VERSION 5.8 ;
BUSBITCHARS "[]" ;
DIVIDERCHAR "/" ;
UNITS
    DATABASE MICRONS 1000 ;
END UNITS

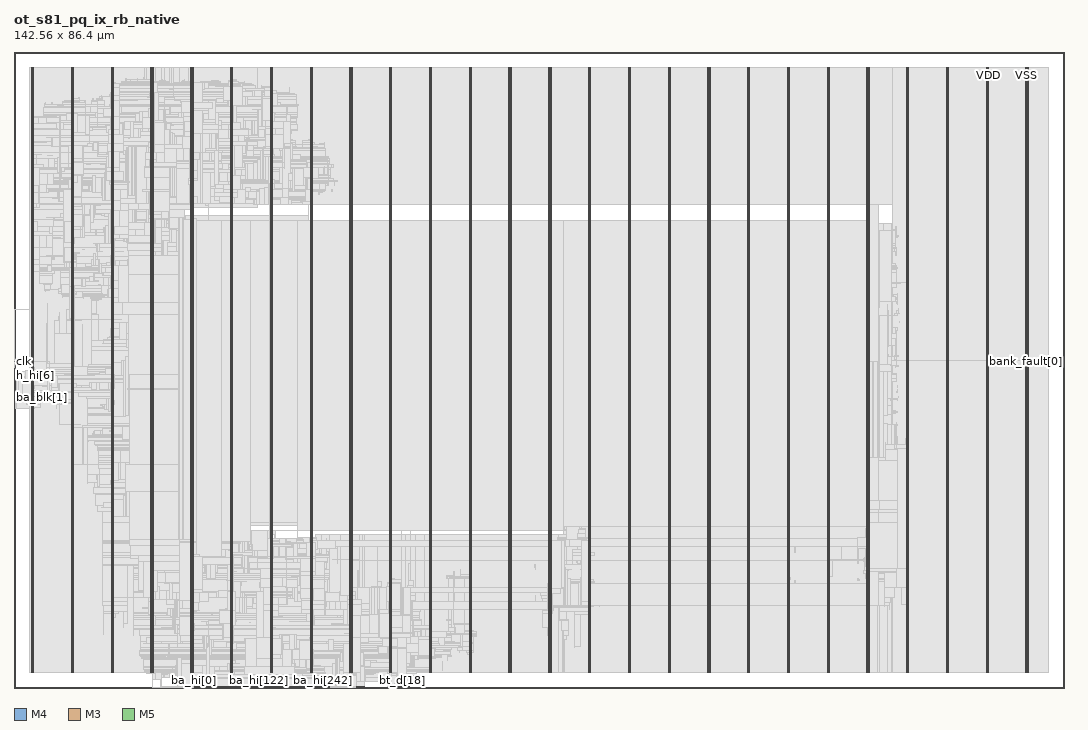
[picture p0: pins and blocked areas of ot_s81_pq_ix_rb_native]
MACRO ot_s81_pq_ix_rb_native
  FOREIGN ot_s81_pq_ix_rb_native 0 0 ;
  CLASS BLOCK ;
  SIZE 142.56 BY 86.4 ;
  PIN ba_blk[0]
    DIRECTION INPUT ;
    USE SIGNAL ;
    PORT
      LAYER M4 ;
        RECT  0 39.312 0.192 39.336 ;
    END
  END ba_blk[0]
  PIN ba_blk[1]
    DIRECTION INPUT ;
    USE SIGNAL ;
    PORT
      LAYER M4 ;
        RECT  0 39.456 0.192 39.48 ;
    END
  END ba_blk[1]
  PIN ba_blk[2]
    DIRECTION INPUT ;
    USE SIGNAL ;
    PORT
      LAYER M4 ;
        RECT  0 39.6 0.192 39.624 ;
    END
  END ba_blk[2]
  PIN ba_blk[3]
    DIRECTION INPUT ;
    USE SIGNAL ;
    PORT
      LAYER M4 ;
        RECT  0 39.744 0.192 39.768 ;
    END
  END ba_blk[3]
  PIN ba_blk[4]
    DIRECTION INPUT ;
    USE SIGNAL ;
    PORT
      LAYER M4 ;
        RECT  0 39.888 0.192 39.912 ;
    END
  END ba_blk[4]
  PIN ba_blk[5]
    DIRECTION INPUT ;
    USE SIGNAL ;
    PORT
      LAYER M4 ;
        RECT  0 40.032 0.192 40.056 ;
    END
  END ba_blk[5]
  PIN ba_blk[6]
    DIRECTION INPUT ;
    USE SIGNAL ;
    PORT
      LAYER M4 ;
        RECT  0 40.176 0.192 40.2 ;
    END
  END ba_blk[6]
  PIN ba_blk[7]
    DIRECTION INPUT ;
    USE SIGNAL ;
    PORT
      LAYER M4 ;
        RECT  0 40.32 0.192 40.344 ;
    END
  END ba_blk[7]
  PIN ba_hi[0]
    DIRECTION INPUT ;
    USE SIGNAL ;
    PORT
      LAYER M3 ;
        RECT  24.48 0 24.498 0.144 ;
    END
  END ba_hi[0]
  PIN ba_hi[100]
    DIRECTION INPUT ;
    USE SIGNAL ;
    PORT
      LAYER M3 ;
        RECT  31.68 0 31.698 0.144 ;
    END
  END ba_hi[100]
  PIN ba_hi[101]
    DIRECTION INPUT ;
    USE SIGNAL ;
    PORT
      LAYER M5 ;
        RECT  31.728 0 31.752 0.192 ;
    END
  END ba_hi[101]
  PIN ba_hi[102]
    DIRECTION INPUT ;
    USE SIGNAL ;
    PORT
      LAYER M3 ;
        RECT  31.824 0 31.842 0.144 ;
    END
  END ba_hi[102]
  PIN ba_hi[103]
    DIRECTION INPUT ;
    USE SIGNAL ;
    PORT
      LAYER M5 ;
        RECT  31.872 0 31.896 0.192 ;
    END
  END ba_hi[103]
  PIN ba_hi[104]
    DIRECTION INPUT ;
    USE SIGNAL ;
    PORT
      LAYER M3 ;
        RECT  31.968 0 31.986 0.144 ;
    END
  END ba_hi[104]
  PIN ba_hi[105]
    DIRECTION INPUT ;
    USE SIGNAL ;
    PORT
      LAYER M5 ;
        RECT  32.016 0 32.04 0.192 ;
    END
  END ba_hi[105]
  PIN ba_hi[106]
    DIRECTION INPUT ;
    USE SIGNAL ;
    PORT
      LAYER M3 ;
        RECT  32.112 0 32.13 0.144 ;
    END
  END ba_hi[106]
  PIN ba_hi[107]
    DIRECTION INPUT ;
    USE SIGNAL ;
    PORT
      LAYER M5 ;
        RECT  32.16 0 32.184 0.192 ;
    END
  END ba_hi[107]
  PIN ba_hi[108]
    DIRECTION INPUT ;
    USE SIGNAL ;
    PORT
      LAYER M3 ;
        RECT  32.256 0 32.274 0.144 ;
    END
  END ba_hi[108]
  PIN ba_hi[109]
    DIRECTION INPUT ;
    USE SIGNAL ;
    PORT
      LAYER M5 ;
        RECT  32.304 0 32.328 0.192 ;
    END
  END ba_hi[109]
  PIN ba_hi[10]
    DIRECTION INPUT ;
    USE SIGNAL ;
    PORT
      LAYER M3 ;
        RECT  25.2 0 25.218 0.144 ;
    END
  END ba_hi[10]
  PIN ba_hi[110]
    DIRECTION INPUT ;
    USE SIGNAL ;
    PORT
      LAYER M3 ;
        RECT  32.4 0 32.418 0.144 ;
    END
  END ba_hi[110]
  PIN ba_hi[111]
    DIRECTION INPUT ;
    USE SIGNAL ;
    PORT
      LAYER M5 ;
        RECT  32.448 0 32.472 0.192 ;
    END
  END ba_hi[111]
  PIN ba_hi[112]
    DIRECTION INPUT ;
    USE SIGNAL ;
    PORT
      LAYER M3 ;
        RECT  32.544 0 32.562 0.144 ;
    END
  END ba_hi[112]
  PIN ba_hi[113]
    DIRECTION INPUT ;
    USE SIGNAL ;
    PORT
      LAYER M5 ;
        RECT  32.592 0 32.616 0.192 ;
    END
  END ba_hi[113]
  PIN ba_hi[114]
    DIRECTION INPUT ;
    USE SIGNAL ;
    PORT
      LAYER M3 ;
        RECT  32.688 0 32.706 0.144 ;
    END
  END ba_hi[114]
  PIN ba_hi[115]
    DIRECTION INPUT ;
    USE SIGNAL ;
    PORT
      LAYER M5 ;
        RECT  32.736 0 32.76 0.192 ;
    END
  END ba_hi[115]
  PIN ba_hi[116]
    DIRECTION INPUT ;
    USE SIGNAL ;
    PORT
      LAYER M3 ;
        RECT  32.832 0 32.85 0.144 ;
    END
  END ba_hi[116]
  PIN ba_hi[117]
    DIRECTION INPUT ;
    USE SIGNAL ;
    PORT
      LAYER M5 ;
        RECT  32.88 0 32.904 0.192 ;
    END
  END ba_hi[117]
  PIN ba_hi[118]
    DIRECTION INPUT ;
    USE SIGNAL ;
    PORT
      LAYER M3 ;
        RECT  32.976 0 32.994 0.144 ;
    END
  END ba_hi[118]
  PIN ba_hi[119]
    DIRECTION INPUT ;
    USE SIGNAL ;
    PORT
      LAYER M5 ;
        RECT  33.024 0 33.048 0.192 ;
    END
  END ba_hi[119]
  PIN ba_hi[11]
    DIRECTION INPUT ;
    USE SIGNAL ;
    PORT
      LAYER M5 ;
        RECT  25.248 0 25.272 0.192 ;
    END
  END ba_hi[11]
  PIN ba_hi[120]
    DIRECTION INPUT ;
    USE SIGNAL ;
    PORT
      LAYER M3 ;
        RECT  33.12 0 33.138 0.144 ;
    END
  END ba_hi[120]
  PIN ba_hi[121]
    DIRECTION INPUT ;
    USE SIGNAL ;
    PORT
      LAYER M5 ;
        RECT  33.168 0 33.192 0.192 ;
    END
  END ba_hi[121]
  PIN ba_hi[122]
    DIRECTION INPUT ;
    USE SIGNAL ;
    PORT
      LAYER M3 ;
        RECT  33.264 0 33.282 0.144 ;
    END
  END ba_hi[122]
  PIN ba_hi[123]
    DIRECTION INPUT ;
    USE SIGNAL ;
    PORT
      LAYER M5 ;
        RECT  33.312 0 33.336 0.192 ;
    END
  END ba_hi[123]
  PIN ba_hi[124]
    DIRECTION INPUT ;
    USE SIGNAL ;
    PORT
      LAYER M3 ;
        RECT  33.408 0 33.426 0.144 ;
    END
  END ba_hi[124]
  PIN ba_hi[125]
    DIRECTION INPUT ;
    USE SIGNAL ;
    PORT
      LAYER M5 ;
        RECT  33.456 0 33.48 0.192 ;
    END
  END ba_hi[125]
  PIN ba_hi[126]
    DIRECTION INPUT ;
    USE SIGNAL ;
    PORT
      LAYER M3 ;
        RECT  33.552 0 33.57 0.144 ;
    END
  END ba_hi[126]
  PIN ba_hi[127]
    DIRECTION INPUT ;
    USE SIGNAL ;
    PORT
      LAYER M5 ;
        RECT  33.6 0 33.624 0.192 ;
    END
  END ba_hi[127]
  PIN ba_hi[128]
    DIRECTION INPUT ;
    USE SIGNAL ;
    PORT
      LAYER M3 ;
        RECT  33.696 0 33.714 0.144 ;
    END
  END ba_hi[128]
  PIN ba_hi[129]
    DIRECTION INPUT ;
    USE SIGNAL ;
    PORT
      LAYER M5 ;
        RECT  33.744 0 33.768 0.192 ;
    END
  END ba_hi[129]
  PIN ba_hi[12]
    DIRECTION INPUT ;
    USE SIGNAL ;
    PORT
      LAYER M3 ;
        RECT  25.344 0 25.362 0.144 ;
    END
  END ba_hi[12]
  PIN ba_hi[130]
    DIRECTION INPUT ;
    USE SIGNAL ;
    PORT
      LAYER M3 ;
        RECT  33.84 0 33.858 0.144 ;
    END
  END ba_hi[130]
  PIN ba_hi[131]
    DIRECTION INPUT ;
    USE SIGNAL ;
    PORT
      LAYER M5 ;
        RECT  33.888 0 33.912 0.192 ;
    END
  END ba_hi[131]
  PIN ba_hi[132]
    DIRECTION INPUT ;
    USE SIGNAL ;
    PORT
      LAYER M3 ;
        RECT  33.984 0 34.002 0.144 ;
    END
  END ba_hi[132]
  PIN ba_hi[133]
    DIRECTION INPUT ;
    USE SIGNAL ;
    PORT
      LAYER M5 ;
        RECT  34.032 0 34.056 0.192 ;
    END
  END ba_hi[133]
  PIN ba_hi[134]
    DIRECTION INPUT ;
    USE SIGNAL ;
    PORT
      LAYER M3 ;
        RECT  34.128 0 34.146 0.144 ;
    END
  END ba_hi[134]
  PIN ba_hi[135]
    DIRECTION INPUT ;
    USE SIGNAL ;
    PORT
      LAYER M5 ;
        RECT  34.176 0 34.2 0.192 ;
    END
  END ba_hi[135]
  PIN ba_hi[136]
    DIRECTION INPUT ;
    USE SIGNAL ;
    PORT
      LAYER M3 ;
        RECT  34.272 0 34.29 0.144 ;
    END
  END ba_hi[136]
  PIN ba_hi[137]
    DIRECTION INPUT ;
    USE SIGNAL ;
    PORT
      LAYER M5 ;
        RECT  34.32 0 34.344 0.192 ;
    END
  END ba_hi[137]
  PIN ba_hi[138]
    DIRECTION INPUT ;
    USE SIGNAL ;
    PORT
      LAYER M3 ;
        RECT  34.416 0 34.434 0.144 ;
    END
  END ba_hi[138]
  PIN ba_hi[139]
    DIRECTION INPUT ;
    USE SIGNAL ;
    PORT
      LAYER M5 ;
        RECT  34.464 0 34.488 0.192 ;
    END
  END ba_hi[139]
  PIN ba_hi[13]
    DIRECTION INPUT ;
    USE SIGNAL ;
    PORT
      LAYER M5 ;
        RECT  25.392 0 25.416 0.192 ;
    END
  END ba_hi[13]
  PIN ba_hi[140]
    DIRECTION INPUT ;
    USE SIGNAL ;
    PORT
      LAYER M3 ;
        RECT  34.56 0 34.578 0.144 ;
    END
  END ba_hi[140]
  PIN ba_hi[141]
    DIRECTION INPUT ;
    USE SIGNAL ;
    PORT
      LAYER M5 ;
        RECT  34.608 0 34.632 0.192 ;
    END
  END ba_hi[141]
  PIN ba_hi[142]
    DIRECTION INPUT ;
    USE SIGNAL ;
    PORT
      LAYER M3 ;
        RECT  34.704 0 34.722 0.144 ;
    END
  END ba_hi[142]
  PIN ba_hi[143]
    DIRECTION INPUT ;
    USE SIGNAL ;
    PORT
      LAYER M5 ;
        RECT  34.752 0 34.776 0.192 ;
    END
  END ba_hi[143]
  PIN ba_hi[144]
    DIRECTION INPUT ;
    USE SIGNAL ;
    PORT
      LAYER M3 ;
        RECT  34.848 0 34.866 0.144 ;
    END
  END ba_hi[144]
  PIN ba_hi[145]
    DIRECTION INPUT ;
    USE SIGNAL ;
    PORT
      LAYER M5 ;
        RECT  34.896 0 34.92 0.192 ;
    END
  END ba_hi[145]
  PIN ba_hi[146]
    DIRECTION INPUT ;
    USE SIGNAL ;
    PORT
      LAYER M3 ;
        RECT  34.992 0 35.01 0.144 ;
    END
  END ba_hi[146]
  PIN ba_hi[147]
    DIRECTION INPUT ;
    USE SIGNAL ;
    PORT
      LAYER M5 ;
        RECT  35.04 0 35.064 0.192 ;
    END
  END ba_hi[147]
  PIN ba_hi[148]
    DIRECTION INPUT ;
    USE SIGNAL ;
    PORT
      LAYER M3 ;
        RECT  35.136 0 35.154 0.144 ;
    END
  END ba_hi[148]
  PIN ba_hi[149]
    DIRECTION INPUT ;
    USE SIGNAL ;
    PORT
      LAYER M5 ;
        RECT  35.184 0 35.208 0.192 ;
    END
  END ba_hi[149]
  PIN ba_hi[14]
    DIRECTION INPUT ;
    USE SIGNAL ;
    PORT
      LAYER M3 ;
        RECT  25.488 0 25.506 0.144 ;
    END
  END ba_hi[14]
  PIN ba_hi[150]
    DIRECTION INPUT ;
    USE SIGNAL ;
    PORT
      LAYER M3 ;
        RECT  35.28 0 35.298 0.144 ;
    END
  END ba_hi[150]
  PIN ba_hi[151]
    DIRECTION INPUT ;
    USE SIGNAL ;
    PORT
      LAYER M5 ;
        RECT  35.328 0 35.352 0.192 ;
    END
  END ba_hi[151]
  PIN ba_hi[152]
    DIRECTION INPUT ;
    USE SIGNAL ;
    PORT
      LAYER M3 ;
        RECT  35.424 0 35.442 0.144 ;
    END
  END ba_hi[152]
  PIN ba_hi[153]
    DIRECTION INPUT ;
    USE SIGNAL ;
    PORT
      LAYER M5 ;
        RECT  35.472 0 35.496 0.192 ;
    END
  END ba_hi[153]
  PIN ba_hi[154]
    DIRECTION INPUT ;
    USE SIGNAL ;
    PORT
      LAYER M3 ;
        RECT  35.568 0 35.586 0.144 ;
    END
  END ba_hi[154]
  PIN ba_hi[155]
    DIRECTION INPUT ;
    USE SIGNAL ;
    PORT
      LAYER M5 ;
        RECT  35.616 0 35.64 0.192 ;
    END
  END ba_hi[155]
  PIN ba_hi[156]
    DIRECTION INPUT ;
    USE SIGNAL ;
    PORT
      LAYER M3 ;
        RECT  35.712 0 35.73 0.144 ;
    END
  END ba_hi[156]
  PIN ba_hi[157]
    DIRECTION INPUT ;
    USE SIGNAL ;
    PORT
      LAYER M5 ;
        RECT  35.76 0 35.784 0.192 ;
    END
  END ba_hi[157]
  PIN ba_hi[158]
    DIRECTION INPUT ;
    USE SIGNAL ;
    PORT
      LAYER M3 ;
        RECT  35.856 0 35.874 0.144 ;
    END
  END ba_hi[158]
  PIN ba_hi[159]
    DIRECTION INPUT ;
    USE SIGNAL ;
    PORT
      LAYER M5 ;
        RECT  35.904 0 35.928 0.192 ;
    END
  END ba_hi[159]
  PIN ba_hi[15]
    DIRECTION INPUT ;
    USE SIGNAL ;
    PORT
      LAYER M5 ;
        RECT  25.536 0 25.56 0.192 ;
    END
  END ba_hi[15]
  PIN ba_hi[160]
    DIRECTION INPUT ;
    USE SIGNAL ;
    PORT
      LAYER M3 ;
        RECT  36 0 36.018 0.144 ;
    END
  END ba_hi[160]
  PIN ba_hi[161]
    DIRECTION INPUT ;
    USE SIGNAL ;
    PORT
      LAYER M5 ;
        RECT  36.048 0 36.072 0.192 ;
    END
  END ba_hi[161]
  PIN ba_hi[162]
    DIRECTION INPUT ;
    USE SIGNAL ;
    PORT
      LAYER M3 ;
        RECT  36.144 0 36.162 0.144 ;
    END
  END ba_hi[162]
  PIN ba_hi[163]
    DIRECTION INPUT ;
    USE SIGNAL ;
    PORT
      LAYER M5 ;
        RECT  36.192 0 36.216 0.192 ;
    END
  END ba_hi[163]
  PIN ba_hi[164]
    DIRECTION INPUT ;
    USE SIGNAL ;
    PORT
      LAYER M3 ;
        RECT  36.288 0 36.306 0.144 ;
    END
  END ba_hi[164]
  PIN ba_hi[165]
    DIRECTION INPUT ;
    USE SIGNAL ;
    PORT
      LAYER M5 ;
        RECT  36.336 0 36.36 0.192 ;
    END
  END ba_hi[165]
  PIN ba_hi[166]
    DIRECTION INPUT ;
    USE SIGNAL ;
    PORT
      LAYER M3 ;
        RECT  36.432 0 36.45 0.144 ;
    END
  END ba_hi[166]
  PIN ba_hi[167]
    DIRECTION INPUT ;
    USE SIGNAL ;
    PORT
      LAYER M5 ;
        RECT  36.48 0 36.504 0.192 ;
    END
  END ba_hi[167]
  PIN ba_hi[168]
    DIRECTION INPUT ;
    USE SIGNAL ;
    PORT
      LAYER M3 ;
        RECT  36.576 0 36.594 0.144 ;
    END
  END ba_hi[168]
  PIN ba_hi[169]
    DIRECTION INPUT ;
    USE SIGNAL ;
    PORT
      LAYER M5 ;
        RECT  36.624 0 36.648 0.192 ;
    END
  END ba_hi[169]
  PIN ba_hi[16]
    DIRECTION INPUT ;
    USE SIGNAL ;
    PORT
      LAYER M3 ;
        RECT  25.632 0 25.65 0.144 ;
    END
  END ba_hi[16]
  PIN ba_hi[170]
    DIRECTION INPUT ;
    USE SIGNAL ;
    PORT
      LAYER M3 ;
        RECT  36.72 0 36.738 0.144 ;
    END
  END ba_hi[170]
  PIN ba_hi[171]
    DIRECTION INPUT ;
    USE SIGNAL ;
    PORT
      LAYER M5 ;
        RECT  36.768 0 36.792 0.192 ;
    END
  END ba_hi[171]
  PIN ba_hi[172]
    DIRECTION INPUT ;
    USE SIGNAL ;
    PORT
      LAYER M3 ;
        RECT  36.864 0 36.882 0.144 ;
    END
  END ba_hi[172]
  PIN ba_hi[173]
    DIRECTION INPUT ;
    USE SIGNAL ;
    PORT
      LAYER M5 ;
        RECT  36.912 0 36.936 0.192 ;
    END
  END ba_hi[173]
  PIN ba_hi[174]
    DIRECTION INPUT ;
    USE SIGNAL ;
    PORT
      LAYER M3 ;
        RECT  37.008 0 37.026 0.144 ;
    END
  END ba_hi[174]
  PIN ba_hi[175]
    DIRECTION INPUT ;
    USE SIGNAL ;
    PORT
      LAYER M5 ;
        RECT  37.056 0 37.08 0.192 ;
    END
  END ba_hi[175]
  PIN ba_hi[176]
    DIRECTION INPUT ;
    USE SIGNAL ;
    PORT
      LAYER M3 ;
        RECT  37.152 0 37.17 0.144 ;
    END
  END ba_hi[176]
  PIN ba_hi[177]
    DIRECTION INPUT ;
    USE SIGNAL ;
    PORT
      LAYER M5 ;
        RECT  37.2 0 37.224 0.192 ;
    END
  END ba_hi[177]
  PIN ba_hi[178]
    DIRECTION INPUT ;
    USE SIGNAL ;
    PORT
      LAYER M3 ;
        RECT  37.296 0 37.314 0.144 ;
    END
  END ba_hi[178]
  PIN ba_hi[179]
    DIRECTION INPUT ;
    USE SIGNAL ;
    PORT
      LAYER M5 ;
        RECT  37.344 0 37.368 0.192 ;
    END
  END ba_hi[179]
  PIN ba_hi[17]
    DIRECTION INPUT ;
    USE SIGNAL ;
    PORT
      LAYER M5 ;
        RECT  25.68 0 25.704 0.192 ;
    END
  END ba_hi[17]
  PIN ba_hi[180]
    DIRECTION INPUT ;
    USE SIGNAL ;
    PORT
      LAYER M3 ;
        RECT  37.44 0 37.458 0.144 ;
    END
  END ba_hi[180]
  PIN ba_hi[181]
    DIRECTION INPUT ;
    USE SIGNAL ;
    PORT
      LAYER M5 ;
        RECT  37.488 0 37.512 0.192 ;
    END
  END ba_hi[181]
  PIN ba_hi[182]
    DIRECTION INPUT ;
    USE SIGNAL ;
    PORT
      LAYER M3 ;
        RECT  37.584 0 37.602 0.144 ;
    END
  END ba_hi[182]
  PIN ba_hi[183]
    DIRECTION INPUT ;
    USE SIGNAL ;
    PORT
      LAYER M5 ;
        RECT  37.632 0 37.656 0.192 ;
    END
  END ba_hi[183]
  PIN ba_hi[184]
    DIRECTION INPUT ;
    USE SIGNAL ;
    PORT
      LAYER M3 ;
        RECT  37.728 0 37.746 0.144 ;
    END
  END ba_hi[184]
  PIN ba_hi[185]
    DIRECTION INPUT ;
    USE SIGNAL ;
    PORT
      LAYER M5 ;
        RECT  37.776 0 37.8 0.192 ;
    END
  END ba_hi[185]
  PIN ba_hi[186]
    DIRECTION INPUT ;
    USE SIGNAL ;
    PORT
      LAYER M3 ;
        RECT  37.872 0 37.89 0.144 ;
    END
  END ba_hi[186]
  PIN ba_hi[187]
    DIRECTION INPUT ;
    USE SIGNAL ;
    PORT
      LAYER M5 ;
        RECT  37.92 0 37.944 0.192 ;
    END
  END ba_hi[187]
  PIN ba_hi[188]
    DIRECTION INPUT ;
    USE SIGNAL ;
    PORT
      LAYER M3 ;
        RECT  38.016 0 38.034 0.144 ;
    END
  END ba_hi[188]
  PIN ba_hi[189]
    DIRECTION INPUT ;
    USE SIGNAL ;
    PORT
      LAYER M5 ;
        RECT  38.064 0 38.088 0.192 ;
    END
  END ba_hi[189]
  PIN ba_hi[18]
    DIRECTION INPUT ;
    USE SIGNAL ;
    PORT
      LAYER M3 ;
        RECT  25.776 0 25.794 0.144 ;
    END
  END ba_hi[18]
  PIN ba_hi[190]
    DIRECTION INPUT ;
    USE SIGNAL ;
    PORT
      LAYER M3 ;
        RECT  38.16 0 38.178 0.144 ;
    END
  END ba_hi[190]
  PIN ba_hi[191]
    DIRECTION INPUT ;
    USE SIGNAL ;
    PORT
      LAYER M5 ;
        RECT  38.208 0 38.232 0.192 ;
    END
  END ba_hi[191]
  PIN ba_hi[192]
    DIRECTION INPUT ;
    USE SIGNAL ;
    PORT
      LAYER M3 ;
        RECT  38.304 0 38.322 0.144 ;
    END
  END ba_hi[192]
  PIN ba_hi[193]
    DIRECTION INPUT ;
    USE SIGNAL ;
    PORT
      LAYER M5 ;
        RECT  38.352 0 38.376 0.192 ;
    END
  END ba_hi[193]
  PIN ba_hi[194]
    DIRECTION INPUT ;
    USE SIGNAL ;
    PORT
      LAYER M3 ;
        RECT  38.448 0 38.466 0.144 ;
    END
  END ba_hi[194]
  PIN ba_hi[195]
    DIRECTION INPUT ;
    USE SIGNAL ;
    PORT
      LAYER M5 ;
        RECT  38.496 0 38.52 0.192 ;
    END
  END ba_hi[195]
  PIN ba_hi[196]
    DIRECTION INPUT ;
    USE SIGNAL ;
    PORT
      LAYER M3 ;
        RECT  38.592 0 38.61 0.144 ;
    END
  END ba_hi[196]
  PIN ba_hi[197]
    DIRECTION INPUT ;
    USE SIGNAL ;
    PORT
      LAYER M5 ;
        RECT  38.64 0 38.664 0.192 ;
    END
  END ba_hi[197]
  PIN ba_hi[198]
    DIRECTION INPUT ;
    USE SIGNAL ;
    PORT
      LAYER M3 ;
        RECT  38.736 0 38.754 0.144 ;
    END
  END ba_hi[198]
  PIN ba_hi[199]
    DIRECTION INPUT ;
    USE SIGNAL ;
    PORT
      LAYER M5 ;
        RECT  38.784 0 38.808 0.192 ;
    END
  END ba_hi[199]
  PIN ba_hi[19]
    DIRECTION INPUT ;
    USE SIGNAL ;
    PORT
      LAYER M5 ;
        RECT  25.824 0 25.848 0.192 ;
    END
  END ba_hi[19]
  PIN ba_hi[1]
    DIRECTION INPUT ;
    USE SIGNAL ;
    PORT
      LAYER M5 ;
        RECT  24.528 0 24.552 0.192 ;
    END
  END ba_hi[1]
  PIN ba_hi[200]
    DIRECTION INPUT ;
    USE SIGNAL ;
    PORT
      LAYER M3 ;
        RECT  38.88 0 38.898 0.144 ;
    END
  END ba_hi[200]
  PIN ba_hi[201]
    DIRECTION INPUT ;
    USE SIGNAL ;
    PORT
      LAYER M5 ;
        RECT  38.928 0 38.952 0.192 ;
    END
  END ba_hi[201]
  PIN ba_hi[202]
    DIRECTION INPUT ;
    USE SIGNAL ;
    PORT
      LAYER M3 ;
        RECT  39.024 0 39.042 0.144 ;
    END
  END ba_hi[202]
  PIN ba_hi[203]
    DIRECTION INPUT ;
    USE SIGNAL ;
    PORT
      LAYER M5 ;
        RECT  39.072 0 39.096 0.192 ;
    END
  END ba_hi[203]
  PIN ba_hi[204]
    DIRECTION INPUT ;
    USE SIGNAL ;
    PORT
      LAYER M3 ;
        RECT  39.168 0 39.186 0.144 ;
    END
  END ba_hi[204]
  PIN ba_hi[205]
    DIRECTION INPUT ;
    USE SIGNAL ;
    PORT
      LAYER M5 ;
        RECT  39.216 0 39.24 0.192 ;
    END
  END ba_hi[205]
  PIN ba_hi[206]
    DIRECTION INPUT ;
    USE SIGNAL ;
    PORT
      LAYER M3 ;
        RECT  39.312 0 39.33 0.144 ;
    END
  END ba_hi[206]
  PIN ba_hi[207]
    DIRECTION INPUT ;
    USE SIGNAL ;
    PORT
      LAYER M5 ;
        RECT  39.36 0 39.384 0.192 ;
    END
  END ba_hi[207]
  PIN ba_hi[208]
    DIRECTION INPUT ;
    USE SIGNAL ;
    PORT
      LAYER M3 ;
        RECT  39.456 0 39.474 0.144 ;
    END
  END ba_hi[208]
  PIN ba_hi[209]
    DIRECTION INPUT ;
    USE SIGNAL ;
    PORT
      LAYER M5 ;
        RECT  39.504 0 39.528 0.192 ;
    END
  END ba_hi[209]
  PIN ba_hi[20]
    DIRECTION INPUT ;
    USE SIGNAL ;
    PORT
      LAYER M3 ;
        RECT  25.92 0 25.938 0.144 ;
    END
  END ba_hi[20]
  PIN ba_hi[210]
    DIRECTION INPUT ;
    USE SIGNAL ;
    PORT
      LAYER M3 ;
        RECT  39.6 0 39.618 0.144 ;
    END
  END ba_hi[210]
  PIN ba_hi[211]
    DIRECTION INPUT ;
    USE SIGNAL ;
    PORT
      LAYER M5 ;
        RECT  39.648 0 39.672 0.192 ;
    END
  END ba_hi[211]
  PIN ba_hi[212]
    DIRECTION INPUT ;
    USE SIGNAL ;
    PORT
      LAYER M3 ;
        RECT  39.744 0 39.762 0.144 ;
    END
  END ba_hi[212]
  PIN ba_hi[213]
    DIRECTION INPUT ;
    USE SIGNAL ;
    PORT
      LAYER M5 ;
        RECT  39.792 0 39.816 0.192 ;
    END
  END ba_hi[213]
  PIN ba_hi[214]
    DIRECTION INPUT ;
    USE SIGNAL ;
    PORT
      LAYER M3 ;
        RECT  39.888 0 39.906 0.144 ;
    END
  END ba_hi[214]
  PIN ba_hi[215]
    DIRECTION INPUT ;
    USE SIGNAL ;
    PORT
      LAYER M5 ;
        RECT  39.936 0 39.96 0.192 ;
    END
  END ba_hi[215]
  PIN ba_hi[216]
    DIRECTION INPUT ;
    USE SIGNAL ;
    PORT
      LAYER M3 ;
        RECT  40.032 0 40.05 0.144 ;
    END
  END ba_hi[216]
  PIN ba_hi[217]
    DIRECTION INPUT ;
    USE SIGNAL ;
    PORT
      LAYER M5 ;
        RECT  40.08 0 40.104 0.192 ;
    END
  END ba_hi[217]
  PIN ba_hi[218]
    DIRECTION INPUT ;
    USE SIGNAL ;
    PORT
      LAYER M3 ;
        RECT  40.176 0 40.194 0.144 ;
    END
  END ba_hi[218]
  PIN ba_hi[219]
    DIRECTION INPUT ;
    USE SIGNAL ;
    PORT
      LAYER M5 ;
        RECT  40.224 0 40.248 0.192 ;
    END
  END ba_hi[219]
  PIN ba_hi[21]
    DIRECTION INPUT ;
    USE SIGNAL ;
    PORT
      LAYER M5 ;
        RECT  25.968 0 25.992 0.192 ;
    END
  END ba_hi[21]
  PIN ba_hi[220]
    DIRECTION INPUT ;
    USE SIGNAL ;
    PORT
      LAYER M3 ;
        RECT  40.32 0 40.338 0.144 ;
    END
  END ba_hi[220]
  PIN ba_hi[221]
    DIRECTION INPUT ;
    USE SIGNAL ;
    PORT
      LAYER M5 ;
        RECT  40.368 0 40.392 0.192 ;
    END
  END ba_hi[221]
  PIN ba_hi[222]
    DIRECTION INPUT ;
    USE SIGNAL ;
    PORT
      LAYER M3 ;
        RECT  40.464 0 40.482 0.144 ;
    END
  END ba_hi[222]
  PIN ba_hi[223]
    DIRECTION INPUT ;
    USE SIGNAL ;
    PORT
      LAYER M5 ;
        RECT  40.512 0 40.536 0.192 ;
    END
  END ba_hi[223]
  PIN ba_hi[224]
    DIRECTION INPUT ;
    USE SIGNAL ;
    PORT
      LAYER M3 ;
        RECT  40.608 0 40.626 0.144 ;
    END
  END ba_hi[224]
  PIN ba_hi[225]
    DIRECTION INPUT ;
    USE SIGNAL ;
    PORT
      LAYER M5 ;
        RECT  40.656 0 40.68 0.192 ;
    END
  END ba_hi[225]
  PIN ba_hi[226]
    DIRECTION INPUT ;
    USE SIGNAL ;
    PORT
      LAYER M3 ;
        RECT  40.752 0 40.77 0.144 ;
    END
  END ba_hi[226]
  PIN ba_hi[227]
    DIRECTION INPUT ;
    USE SIGNAL ;
    PORT
      LAYER M5 ;
        RECT  40.8 0 40.824 0.192 ;
    END
  END ba_hi[227]
  PIN ba_hi[228]
    DIRECTION INPUT ;
    USE SIGNAL ;
    PORT
      LAYER M3 ;
        RECT  40.896 0 40.914 0.144 ;
    END
  END ba_hi[228]
  PIN ba_hi[229]
    DIRECTION INPUT ;
    USE SIGNAL ;
    PORT
      LAYER M5 ;
        RECT  40.944 0 40.968 0.192 ;
    END
  END ba_hi[229]
  PIN ba_hi[22]
    DIRECTION INPUT ;
    USE SIGNAL ;
    PORT
      LAYER M3 ;
        RECT  26.064 0 26.082 0.144 ;
    END
  END ba_hi[22]
  PIN ba_hi[230]
    DIRECTION INPUT ;
    USE SIGNAL ;
    PORT
      LAYER M3 ;
        RECT  41.04 0 41.058 0.144 ;
    END
  END ba_hi[230]
  PIN ba_hi[231]
    DIRECTION INPUT ;
    USE SIGNAL ;
    PORT
      LAYER M5 ;
        RECT  41.088 0 41.112 0.192 ;
    END
  END ba_hi[231]
  PIN ba_hi[232]
    DIRECTION INPUT ;
    USE SIGNAL ;
    PORT
      LAYER M3 ;
        RECT  41.184 0 41.202 0.144 ;
    END
  END ba_hi[232]
  PIN ba_hi[233]
    DIRECTION INPUT ;
    USE SIGNAL ;
    PORT
      LAYER M5 ;
        RECT  41.232 0 41.256 0.192 ;
    END
  END ba_hi[233]
  PIN ba_hi[234]
    DIRECTION INPUT ;
    USE SIGNAL ;
    PORT
      LAYER M3 ;
        RECT  41.328 0 41.346 0.144 ;
    END
  END ba_hi[234]
  PIN ba_hi[235]
    DIRECTION INPUT ;
    USE SIGNAL ;
    PORT
      LAYER M5 ;
        RECT  41.376 0 41.4 0.192 ;
    END
  END ba_hi[235]
  PIN ba_hi[236]
    DIRECTION INPUT ;
    USE SIGNAL ;
    PORT
      LAYER M3 ;
        RECT  41.472 0 41.49 0.144 ;
    END
  END ba_hi[236]
  PIN ba_hi[237]
    DIRECTION INPUT ;
    USE SIGNAL ;
    PORT
      LAYER M5 ;
        RECT  41.52 0 41.544 0.192 ;
    END
  END ba_hi[237]
  PIN ba_hi[238]
    DIRECTION INPUT ;
    USE SIGNAL ;
    PORT
      LAYER M3 ;
        RECT  41.616 0 41.634 0.144 ;
    END
  END ba_hi[238]
  PIN ba_hi[239]
    DIRECTION INPUT ;
    USE SIGNAL ;
    PORT
      LAYER M5 ;
        RECT  41.664 0 41.688 0.192 ;
    END
  END ba_hi[239]
  PIN ba_hi[23]
    DIRECTION INPUT ;
    USE SIGNAL ;
    PORT
      LAYER M5 ;
        RECT  26.112 0 26.136 0.192 ;
    END
  END ba_hi[23]
  PIN ba_hi[240]
    DIRECTION INPUT ;
    USE SIGNAL ;
    PORT
      LAYER M3 ;
        RECT  41.76 0 41.778 0.144 ;
    END
  END ba_hi[240]
  PIN ba_hi[241]
    DIRECTION INPUT ;
    USE SIGNAL ;
    PORT
      LAYER M5 ;
        RECT  41.808 0 41.832 0.192 ;
    END
  END ba_hi[241]
  PIN ba_hi[242]
    DIRECTION INPUT ;
    USE SIGNAL ;
    PORT
      LAYER M3 ;
        RECT  41.904 0 41.922 0.144 ;
    END
  END ba_hi[242]
  PIN ba_hi[243]
    DIRECTION INPUT ;
    USE SIGNAL ;
    PORT
      LAYER M5 ;
        RECT  41.952 0 41.976 0.192 ;
    END
  END ba_hi[243]
  PIN ba_hi[244]
    DIRECTION INPUT ;
    USE SIGNAL ;
    PORT
      LAYER M3 ;
        RECT  42.048 0 42.066 0.144 ;
    END
  END ba_hi[244]
  PIN ba_hi[245]
    DIRECTION INPUT ;
    USE SIGNAL ;
    PORT
      LAYER M5 ;
        RECT  42.096 0 42.12 0.192 ;
    END
  END ba_hi[245]
  PIN ba_hi[246]
    DIRECTION INPUT ;
    USE SIGNAL ;
    PORT
      LAYER M3 ;
        RECT  42.192 0 42.21 0.144 ;
    END
  END ba_hi[246]
  PIN ba_hi[247]
    DIRECTION INPUT ;
    USE SIGNAL ;
    PORT
      LAYER M5 ;
        RECT  42.24 0 42.264 0.192 ;
    END
  END ba_hi[247]
  PIN ba_hi[248]
    DIRECTION INPUT ;
    USE SIGNAL ;
    PORT
      LAYER M3 ;
        RECT  42.336 0 42.354 0.144 ;
    END
  END ba_hi[248]
  PIN ba_hi[249]
    DIRECTION INPUT ;
    USE SIGNAL ;
    PORT
      LAYER M5 ;
        RECT  42.384 0 42.408 0.192 ;
    END
  END ba_hi[249]
  PIN ba_hi[24]
    DIRECTION INPUT ;
    USE SIGNAL ;
    PORT
      LAYER M3 ;
        RECT  26.208 0 26.226 0.144 ;
    END
  END ba_hi[24]
  PIN ba_hi[250]
    DIRECTION INPUT ;
    USE SIGNAL ;
    PORT
      LAYER M3 ;
        RECT  42.48 0 42.498 0.144 ;
    END
  END ba_hi[250]
  PIN ba_hi[251]
    DIRECTION INPUT ;
    USE SIGNAL ;
    PORT
      LAYER M5 ;
        RECT  42.528 0 42.552 0.192 ;
    END
  END ba_hi[251]
  PIN ba_hi[252]
    DIRECTION INPUT ;
    USE SIGNAL ;
    PORT
      LAYER M3 ;
        RECT  42.624 0 42.642 0.144 ;
    END
  END ba_hi[252]
  PIN ba_hi[253]
    DIRECTION INPUT ;
    USE SIGNAL ;
    PORT
      LAYER M5 ;
        RECT  42.672 0 42.696 0.192 ;
    END
  END ba_hi[253]
  PIN ba_hi[254]
    DIRECTION INPUT ;
    USE SIGNAL ;
    PORT
      LAYER M3 ;
        RECT  42.768 0 42.786 0.144 ;
    END
  END ba_hi[254]
  PIN ba_hi[255]
    DIRECTION INPUT ;
    USE SIGNAL ;
    PORT
      LAYER M5 ;
        RECT  42.816 0 42.84 0.192 ;
    END
  END ba_hi[255]
  PIN ba_hi[25]
    DIRECTION INPUT ;
    USE SIGNAL ;
    PORT
      LAYER M5 ;
        RECT  26.256 0 26.28 0.192 ;
    END
  END ba_hi[25]
  PIN ba_hi[26]
    DIRECTION INPUT ;
    USE SIGNAL ;
    PORT
      LAYER M3 ;
        RECT  26.352 0 26.37 0.144 ;
    END
  END ba_hi[26]
  PIN ba_hi[27]
    DIRECTION INPUT ;
    USE SIGNAL ;
    PORT
      LAYER M5 ;
        RECT  26.4 0 26.424 0.192 ;
    END
  END ba_hi[27]
  PIN ba_hi[28]
    DIRECTION INPUT ;
    USE SIGNAL ;
    PORT
      LAYER M3 ;
        RECT  26.496 0 26.514 0.144 ;
    END
  END ba_hi[28]
  PIN ba_hi[29]
    DIRECTION INPUT ;
    USE SIGNAL ;
    PORT
      LAYER M5 ;
        RECT  26.544 0 26.568 0.192 ;
    END
  END ba_hi[29]
  PIN ba_hi[2]
    DIRECTION INPUT ;
    USE SIGNAL ;
    PORT
      LAYER M3 ;
        RECT  24.624 0 24.642 0.144 ;
    END
  END ba_hi[2]
  PIN ba_hi[30]
    DIRECTION INPUT ;
    USE SIGNAL ;
    PORT
      LAYER M3 ;
        RECT  26.64 0 26.658 0.144 ;
    END
  END ba_hi[30]
  PIN ba_hi[31]
    DIRECTION INPUT ;
    USE SIGNAL ;
    PORT
      LAYER M5 ;
        RECT  26.688 0 26.712 0.192 ;
    END
  END ba_hi[31]
  PIN ba_hi[32]
    DIRECTION INPUT ;
    USE SIGNAL ;
    PORT
      LAYER M3 ;
        RECT  26.784 0 26.802 0.144 ;
    END
  END ba_hi[32]
  PIN ba_hi[33]
    DIRECTION INPUT ;
    USE SIGNAL ;
    PORT
      LAYER M5 ;
        RECT  26.832 0 26.856 0.192 ;
    END
  END ba_hi[33]
  PIN ba_hi[34]
    DIRECTION INPUT ;
    USE SIGNAL ;
    PORT
      LAYER M3 ;
        RECT  26.928 0 26.946 0.144 ;
    END
  END ba_hi[34]
  PIN ba_hi[35]
    DIRECTION INPUT ;
    USE SIGNAL ;
    PORT
      LAYER M5 ;
        RECT  26.976 0 27 0.192 ;
    END
  END ba_hi[35]
  PIN ba_hi[36]
    DIRECTION INPUT ;
    USE SIGNAL ;
    PORT
      LAYER M3 ;
        RECT  27.072 0 27.09 0.144 ;
    END
  END ba_hi[36]
  PIN ba_hi[37]
    DIRECTION INPUT ;
    USE SIGNAL ;
    PORT
      LAYER M5 ;
        RECT  27.12 0 27.144 0.192 ;
    END
  END ba_hi[37]
  PIN ba_hi[38]
    DIRECTION INPUT ;
    USE SIGNAL ;
    PORT
      LAYER M3 ;
        RECT  27.216 0 27.234 0.144 ;
    END
  END ba_hi[38]
  PIN ba_hi[39]
    DIRECTION INPUT ;
    USE SIGNAL ;
    PORT
      LAYER M5 ;
        RECT  27.264 0 27.288 0.192 ;
    END
  END ba_hi[39]
  PIN ba_hi[3]
    DIRECTION INPUT ;
    USE SIGNAL ;
    PORT
      LAYER M5 ;
        RECT  24.672 0 24.696 0.192 ;
    END
  END ba_hi[3]
  PIN ba_hi[40]
    DIRECTION INPUT ;
    USE SIGNAL ;
    PORT
      LAYER M3 ;
        RECT  27.36 0 27.378 0.144 ;
    END
  END ba_hi[40]
  PIN ba_hi[41]
    DIRECTION INPUT ;
    USE SIGNAL ;
    PORT
      LAYER M5 ;
        RECT  27.408 0 27.432 0.192 ;
    END
  END ba_hi[41]
  PIN ba_hi[42]
    DIRECTION INPUT ;
    USE SIGNAL ;
    PORT
      LAYER M3 ;
        RECT  27.504 0 27.522 0.144 ;
    END
  END ba_hi[42]
  PIN ba_hi[43]
    DIRECTION INPUT ;
    USE SIGNAL ;
    PORT
      LAYER M5 ;
        RECT  27.552 0 27.576 0.192 ;
    END
  END ba_hi[43]
  PIN ba_hi[44]
    DIRECTION INPUT ;
    USE SIGNAL ;
    PORT
      LAYER M3 ;
        RECT  27.648 0 27.666 0.144 ;
    END
  END ba_hi[44]
  PIN ba_hi[45]
    DIRECTION INPUT ;
    USE SIGNAL ;
    PORT
      LAYER M5 ;
        RECT  27.696 0 27.72 0.192 ;
    END
  END ba_hi[45]
  PIN ba_hi[46]
    DIRECTION INPUT ;
    USE SIGNAL ;
    PORT
      LAYER M3 ;
        RECT  27.792 0 27.81 0.144 ;
    END
  END ba_hi[46]
  PIN ba_hi[47]
    DIRECTION INPUT ;
    USE SIGNAL ;
    PORT
      LAYER M5 ;
        RECT  27.84 0 27.864 0.192 ;
    END
  END ba_hi[47]
  PIN ba_hi[48]
    DIRECTION INPUT ;
    USE SIGNAL ;
    PORT
      LAYER M3 ;
        RECT  27.936 0 27.954 0.144 ;
    END
  END ba_hi[48]
  PIN ba_hi[49]
    DIRECTION INPUT ;
    USE SIGNAL ;
    PORT
      LAYER M5 ;
        RECT  27.984 0 28.008 0.192 ;
    END
  END ba_hi[49]
  PIN ba_hi[4]
    DIRECTION INPUT ;
    USE SIGNAL ;
    PORT
      LAYER M3 ;
        RECT  24.768 0 24.786 0.144 ;
    END
  END ba_hi[4]
  PIN ba_hi[50]
    DIRECTION INPUT ;
    USE SIGNAL ;
    PORT
      LAYER M3 ;
        RECT  28.08 0 28.098 0.144 ;
    END
  END ba_hi[50]
  PIN ba_hi[51]
    DIRECTION INPUT ;
    USE SIGNAL ;
    PORT
      LAYER M5 ;
        RECT  28.128 0 28.152 0.192 ;
    END
  END ba_hi[51]
  PIN ba_hi[52]
    DIRECTION INPUT ;
    USE SIGNAL ;
    PORT
      LAYER M3 ;
        RECT  28.224 0 28.242 0.144 ;
    END
  END ba_hi[52]
  PIN ba_hi[53]
    DIRECTION INPUT ;
    USE SIGNAL ;
    PORT
      LAYER M5 ;
        RECT  28.272 0 28.296 0.192 ;
    END
  END ba_hi[53]
  PIN ba_hi[54]
    DIRECTION INPUT ;
    USE SIGNAL ;
    PORT
      LAYER M3 ;
        RECT  28.368 0 28.386 0.144 ;
    END
  END ba_hi[54]
  PIN ba_hi[55]
    DIRECTION INPUT ;
    USE SIGNAL ;
    PORT
      LAYER M5 ;
        RECT  28.416 0 28.44 0.192 ;
    END
  END ba_hi[55]
  PIN ba_hi[56]
    DIRECTION INPUT ;
    USE SIGNAL ;
    PORT
      LAYER M3 ;
        RECT  28.512 0 28.53 0.144 ;
    END
  END ba_hi[56]
  PIN ba_hi[57]
    DIRECTION INPUT ;
    USE SIGNAL ;
    PORT
      LAYER M5 ;
        RECT  28.56 0 28.584 0.192 ;
    END
  END ba_hi[57]
  PIN ba_hi[58]
    DIRECTION INPUT ;
    USE SIGNAL ;
    PORT
      LAYER M3 ;
        RECT  28.656 0 28.674 0.144 ;
    END
  END ba_hi[58]
  PIN ba_hi[59]
    DIRECTION INPUT ;
    USE SIGNAL ;
    PORT
      LAYER M5 ;
        RECT  28.704 0 28.728 0.192 ;
    END
  END ba_hi[59]
  PIN ba_hi[5]
    DIRECTION INPUT ;
    USE SIGNAL ;
    PORT
      LAYER M5 ;
        RECT  24.816 0 24.84 0.192 ;
    END
  END ba_hi[5]
  PIN ba_hi[60]
    DIRECTION INPUT ;
    USE SIGNAL ;
    PORT
      LAYER M3 ;
        RECT  28.8 0 28.818 0.144 ;
    END
  END ba_hi[60]
  PIN ba_hi[61]
    DIRECTION INPUT ;
    USE SIGNAL ;
    PORT
      LAYER M5 ;
        RECT  28.848 0 28.872 0.192 ;
    END
  END ba_hi[61]
  PIN ba_hi[62]
    DIRECTION INPUT ;
    USE SIGNAL ;
    PORT
      LAYER M3 ;
        RECT  28.944 0 28.962 0.144 ;
    END
  END ba_hi[62]
  PIN ba_hi[63]
    DIRECTION INPUT ;
    USE SIGNAL ;
    PORT
      LAYER M5 ;
        RECT  28.992 0 29.016 0.192 ;
    END
  END ba_hi[63]
  PIN ba_hi[64]
    DIRECTION INPUT ;
    USE SIGNAL ;
    PORT
      LAYER M3 ;
        RECT  29.088 0 29.106 0.144 ;
    END
  END ba_hi[64]
  PIN ba_hi[65]
    DIRECTION INPUT ;
    USE SIGNAL ;
    PORT
      LAYER M5 ;
        RECT  29.136 0 29.16 0.192 ;
    END
  END ba_hi[65]
  PIN ba_hi[66]
    DIRECTION INPUT ;
    USE SIGNAL ;
    PORT
      LAYER M3 ;
        RECT  29.232 0 29.25 0.144 ;
    END
  END ba_hi[66]
  PIN ba_hi[67]
    DIRECTION INPUT ;
    USE SIGNAL ;
    PORT
      LAYER M5 ;
        RECT  29.28 0 29.304 0.192 ;
    END
  END ba_hi[67]
  PIN ba_hi[68]
    DIRECTION INPUT ;
    USE SIGNAL ;
    PORT
      LAYER M3 ;
        RECT  29.376 0 29.394 0.144 ;
    END
  END ba_hi[68]
  PIN ba_hi[69]
    DIRECTION INPUT ;
    USE SIGNAL ;
    PORT
      LAYER M5 ;
        RECT  29.424 0 29.448 0.192 ;
    END
  END ba_hi[69]
  PIN ba_hi[6]
    DIRECTION INPUT ;
    USE SIGNAL ;
    PORT
      LAYER M3 ;
        RECT  24.912 0 24.93 0.144 ;
    END
  END ba_hi[6]
  PIN ba_hi[70]
    DIRECTION INPUT ;
    USE SIGNAL ;
    PORT
      LAYER M3 ;
        RECT  29.52 0 29.538 0.144 ;
    END
  END ba_hi[70]
  PIN ba_hi[71]
    DIRECTION INPUT ;
    USE SIGNAL ;
    PORT
      LAYER M5 ;
        RECT  29.568 0 29.592 0.192 ;
    END
  END ba_hi[71]
  PIN ba_hi[72]
    DIRECTION INPUT ;
    USE SIGNAL ;
    PORT
      LAYER M3 ;
        RECT  29.664 0 29.682 0.144 ;
    END
  END ba_hi[72]
  PIN ba_hi[73]
    DIRECTION INPUT ;
    USE SIGNAL ;
    PORT
      LAYER M5 ;
        RECT  29.712 0 29.736 0.192 ;
    END
  END ba_hi[73]
  PIN ba_hi[74]
    DIRECTION INPUT ;
    USE SIGNAL ;
    PORT
      LAYER M3 ;
        RECT  29.808 0 29.826 0.144 ;
    END
  END ba_hi[74]
  PIN ba_hi[75]
    DIRECTION INPUT ;
    USE SIGNAL ;
    PORT
      LAYER M5 ;
        RECT  29.856 0 29.88 0.192 ;
    END
  END ba_hi[75]
  PIN ba_hi[76]
    DIRECTION INPUT ;
    USE SIGNAL ;
    PORT
      LAYER M3 ;
        RECT  29.952 0 29.97 0.144 ;
    END
  END ba_hi[76]
  PIN ba_hi[77]
    DIRECTION INPUT ;
    USE SIGNAL ;
    PORT
      LAYER M5 ;
        RECT  30 0 30.024 0.192 ;
    END
  END ba_hi[77]
  PIN ba_hi[78]
    DIRECTION INPUT ;
    USE SIGNAL ;
    PORT
      LAYER M3 ;
        RECT  30.096 0 30.114 0.144 ;
    END
  END ba_hi[78]
  PIN ba_hi[79]
    DIRECTION INPUT ;
    USE SIGNAL ;
    PORT
      LAYER M5 ;
        RECT  30.144 0 30.168 0.192 ;
    END
  END ba_hi[79]
  PIN ba_hi[7]
    DIRECTION INPUT ;
    USE SIGNAL ;
    PORT
      LAYER M5 ;
        RECT  24.96 0 24.984 0.192 ;
    END
  END ba_hi[7]
  PIN ba_hi[80]
    DIRECTION INPUT ;
    USE SIGNAL ;
    PORT
      LAYER M3 ;
        RECT  30.24 0 30.258 0.144 ;
    END
  END ba_hi[80]
  PIN ba_hi[81]
    DIRECTION INPUT ;
    USE SIGNAL ;
    PORT
      LAYER M5 ;
        RECT  30.288 0 30.312 0.192 ;
    END
  END ba_hi[81]
  PIN ba_hi[82]
    DIRECTION INPUT ;
    USE SIGNAL ;
    PORT
      LAYER M3 ;
        RECT  30.384 0 30.402 0.144 ;
    END
  END ba_hi[82]
  PIN ba_hi[83]
    DIRECTION INPUT ;
    USE SIGNAL ;
    PORT
      LAYER M5 ;
        RECT  30.432 0 30.456 0.192 ;
    END
  END ba_hi[83]
  PIN ba_hi[84]
    DIRECTION INPUT ;
    USE SIGNAL ;
    PORT
      LAYER M3 ;
        RECT  30.528 0 30.546 0.144 ;
    END
  END ba_hi[84]
  PIN ba_hi[85]
    DIRECTION INPUT ;
    USE SIGNAL ;
    PORT
      LAYER M5 ;
        RECT  30.576 0 30.6 0.192 ;
    END
  END ba_hi[85]
  PIN ba_hi[86]
    DIRECTION INPUT ;
    USE SIGNAL ;
    PORT
      LAYER M3 ;
        RECT  30.672 0 30.69 0.144 ;
    END
  END ba_hi[86]
  PIN ba_hi[87]
    DIRECTION INPUT ;
    USE SIGNAL ;
    PORT
      LAYER M5 ;
        RECT  30.72 0 30.744 0.192 ;
    END
  END ba_hi[87]
  PIN ba_hi[88]
    DIRECTION INPUT ;
    USE SIGNAL ;
    PORT
      LAYER M3 ;
        RECT  30.816 0 30.834 0.144 ;
    END
  END ba_hi[88]
  PIN ba_hi[89]
    DIRECTION INPUT ;
    USE SIGNAL ;
    PORT
      LAYER M5 ;
        RECT  30.864 0 30.888 0.192 ;
    END
  END ba_hi[89]
  PIN ba_hi[8]
    DIRECTION INPUT ;
    USE SIGNAL ;
    PORT
      LAYER M3 ;
        RECT  25.056 0 25.074 0.144 ;
    END
  END ba_hi[8]
  PIN ba_hi[90]
    DIRECTION INPUT ;
    USE SIGNAL ;
    PORT
      LAYER M3 ;
        RECT  30.96 0 30.978 0.144 ;
    END
  END ba_hi[90]
  PIN ba_hi[91]
    DIRECTION INPUT ;
    USE SIGNAL ;
    PORT
      LAYER M5 ;
        RECT  31.008 0 31.032 0.192 ;
    END
  END ba_hi[91]
  PIN ba_hi[92]
    DIRECTION INPUT ;
    USE SIGNAL ;
    PORT
      LAYER M3 ;
        RECT  31.104 0 31.122 0.144 ;
    END
  END ba_hi[92]
  PIN ba_hi[93]
    DIRECTION INPUT ;
    USE SIGNAL ;
    PORT
      LAYER M5 ;
        RECT  31.152 0 31.176 0.192 ;
    END
  END ba_hi[93]
  PIN ba_hi[94]
    DIRECTION INPUT ;
    USE SIGNAL ;
    PORT
      LAYER M3 ;
        RECT  31.248 0 31.266 0.144 ;
    END
  END ba_hi[94]
  PIN ba_hi[95]
    DIRECTION INPUT ;
    USE SIGNAL ;
    PORT
      LAYER M5 ;
        RECT  31.296 0 31.32 0.192 ;
    END
  END ba_hi[95]
  PIN ba_hi[96]
    DIRECTION INPUT ;
    USE SIGNAL ;
    PORT
      LAYER M3 ;
        RECT  31.392 0 31.41 0.144 ;
    END
  END ba_hi[96]
  PIN ba_hi[97]
    DIRECTION INPUT ;
    USE SIGNAL ;
    PORT
      LAYER M5 ;
        RECT  31.44 0 31.464 0.192 ;
    END
  END ba_hi[97]
  PIN ba_hi[98]
    DIRECTION INPUT ;
    USE SIGNAL ;
    PORT
      LAYER M3 ;
        RECT  31.536 0 31.554 0.144 ;
    END
  END ba_hi[98]
  PIN ba_hi[99]
    DIRECTION INPUT ;
    USE SIGNAL ;
    PORT
      LAYER M5 ;
        RECT  31.584 0 31.608 0.192 ;
    END
  END ba_hi[99]
  PIN ba_hi[9]
    DIRECTION INPUT ;
    USE SIGNAL ;
    PORT
      LAYER M5 ;
        RECT  25.104 0 25.128 0.192 ;
    END
  END ba_hi[9]
  PIN ba_inc[0]
    DIRECTION INPUT ;
    USE SIGNAL ;
    PORT
      LAYER M3 ;
        RECT  46.512 0 46.53 0.144 ;
    END
  END ba_inc[0]
  PIN ba_inc[10]
    DIRECTION INPUT ;
    USE SIGNAL ;
    PORT
      LAYER M3 ;
        RECT  47.232 0 47.25 0.144 ;
    END
  END ba_inc[10]
  PIN ba_inc[11]
    DIRECTION INPUT ;
    USE SIGNAL ;
    PORT
      LAYER M5 ;
        RECT  47.28 0 47.304 0.192 ;
    END
  END ba_inc[11]
  PIN ba_inc[12]
    DIRECTION INPUT ;
    USE SIGNAL ;
    PORT
      LAYER M3 ;
        RECT  47.376 0 47.394 0.144 ;
    END
  END ba_inc[12]
  PIN ba_inc[13]
    DIRECTION INPUT ;
    USE SIGNAL ;
    PORT
      LAYER M5 ;
        RECT  47.424 0 47.448 0.192 ;
    END
  END ba_inc[13]
  PIN ba_inc[14]
    DIRECTION INPUT ;
    USE SIGNAL ;
    PORT
      LAYER M3 ;
        RECT  47.52 0 47.538 0.144 ;
    END
  END ba_inc[14]
  PIN ba_inc[15]
    DIRECTION INPUT ;
    USE SIGNAL ;
    PORT
      LAYER M5 ;
        RECT  47.568 0 47.592 0.192 ;
    END
  END ba_inc[15]
  PIN ba_inc[1]
    DIRECTION INPUT ;
    USE SIGNAL ;
    PORT
      LAYER M5 ;
        RECT  46.56 0 46.584 0.192 ;
    END
  END ba_inc[1]
  PIN ba_inc[2]
    DIRECTION INPUT ;
    USE SIGNAL ;
    PORT
      LAYER M3 ;
        RECT  46.656 0 46.674 0.144 ;
    END
  END ba_inc[2]
  PIN ba_inc[3]
    DIRECTION INPUT ;
    USE SIGNAL ;
    PORT
      LAYER M5 ;
        RECT  46.704 0 46.728 0.192 ;
    END
  END ba_inc[3]
  PIN ba_inc[4]
    DIRECTION INPUT ;
    USE SIGNAL ;
    PORT
      LAYER M3 ;
        RECT  46.8 0 46.818 0.144 ;
    END
  END ba_inc[4]
  PIN ba_inc[5]
    DIRECTION INPUT ;
    USE SIGNAL ;
    PORT
      LAYER M5 ;
        RECT  46.848 0 46.872 0.192 ;
    END
  END ba_inc[5]
  PIN ba_inc[6]
    DIRECTION INPUT ;
    USE SIGNAL ;
    PORT
      LAYER M3 ;
        RECT  46.944 0 46.962 0.144 ;
    END
  END ba_inc[6]
  PIN ba_inc[7]
    DIRECTION INPUT ;
    USE SIGNAL ;
    PORT
      LAYER M5 ;
        RECT  46.992 0 47.016 0.192 ;
    END
  END ba_inc[7]
  PIN ba_inc[8]
    DIRECTION INPUT ;
    USE SIGNAL ;
    PORT
      LAYER M3 ;
        RECT  47.088 0 47.106 0.144 ;
    END
  END ba_inc[8]
  PIN ba_inc[9]
    DIRECTION INPUT ;
    USE SIGNAL ;
    PORT
      LAYER M5 ;
        RECT  47.136 0 47.16 0.192 ;
    END
  END ba_inc[9]
  PIN ba_v
    DIRECTION INPUT ;
    USE SIGNAL ;
    PORT
      LAYER M4 ;
        RECT  0 39.168 0.192 39.192 ;
    END
  END ba_v
  PIN bank_fault[0]
    DIRECTION OUTPUT ;
    USE SIGNAL ;
    PORT
      LAYER M4 ;
        RECT  142.368 44.304 142.56 44.328 ;
    END
    PORT
      LAYER M4 ;
        RECT  140.785 44.304 142.38 44.328 ;
    END
  END bank_fault[0]
  PIN bt_d[0]
    DIRECTION OUTPUT ;
    USE SIGNAL ;
    PORT
      LAYER M3 ;
        RECT  51.48 0 51.498 0.144 ;
    END
  END bt_d[0]
  PIN bt_d[10]
    DIRECTION OUTPUT ;
    USE SIGNAL ;
    PORT
      LAYER M3 ;
        RECT  52.2 0 52.218 0.144 ;
    END
  END bt_d[10]
  PIN bt_d[11]
    DIRECTION OUTPUT ;
    USE SIGNAL ;
    PORT
      LAYER M5 ;
        RECT  52.224 0 52.248 0.192 ;
    END
  END bt_d[11]
  PIN bt_d[12]
    DIRECTION OUTPUT ;
    USE SIGNAL ;
    PORT
      LAYER M3 ;
        RECT  52.344 0 52.362 0.144 ;
    END
  END bt_d[12]
  PIN bt_d[13]
    DIRECTION OUTPUT ;
    USE SIGNAL ;
    PORT
      LAYER M5 ;
        RECT  52.368 0 52.392 0.192 ;
    END
  END bt_d[13]
  PIN bt_d[14]
    DIRECTION OUTPUT ;
    USE SIGNAL ;
    PORT
      LAYER M3 ;
        RECT  52.488 0 52.506 0.144 ;
    END
  END bt_d[14]
  PIN bt_d[15]
    DIRECTION OUTPUT ;
    USE SIGNAL ;
    PORT
      LAYER M5 ;
        RECT  52.512 0 52.536 0.192 ;
    END
  END bt_d[15]
  PIN bt_d[16]
    DIRECTION OUTPUT ;
    USE SIGNAL ;
    PORT
      LAYER M3 ;
        RECT  52.632 0 52.65 0.144 ;
    END
  END bt_d[16]
  PIN bt_d[17]
    DIRECTION OUTPUT ;
    USE SIGNAL ;
    PORT
      LAYER M5 ;
        RECT  52.656 0 52.68 0.192 ;
    END
  END bt_d[17]
  PIN bt_d[18]
    DIRECTION OUTPUT ;
    USE SIGNAL ;
    PORT
      LAYER M3 ;
        RECT  52.776 0 52.794 0.144 ;
    END
  END bt_d[18]
  PIN bt_d[19]
    DIRECTION OUTPUT ;
    USE SIGNAL ;
    PORT
      LAYER M5 ;
        RECT  52.8 0 52.824 0.192 ;
    END
  END bt_d[19]
  PIN bt_d[1]
    DIRECTION OUTPUT ;
    USE SIGNAL ;
    PORT
      LAYER M5 ;
        RECT  51.504 0 51.528 0.192 ;
    END
  END bt_d[1]
  PIN bt_d[20]
    DIRECTION OUTPUT ;
    USE SIGNAL ;
    PORT
      LAYER M3 ;
        RECT  52.92 0 52.938 0.144 ;
    END
  END bt_d[20]
  PIN bt_d[21]
    DIRECTION OUTPUT ;
    USE SIGNAL ;
    PORT
      LAYER M5 ;
        RECT  52.944 0 52.968 0.192 ;
    END
  END bt_d[21]
  PIN bt_d[22]
    DIRECTION OUTPUT ;
    USE SIGNAL ;
    PORT
      LAYER M3 ;
        RECT  53.064 0 53.082 0.144 ;
    END
  END bt_d[22]
  PIN bt_d[23]
    DIRECTION OUTPUT ;
    USE SIGNAL ;
    PORT
      LAYER M5 ;
        RECT  53.088 0 53.112 0.192 ;
    END
  END bt_d[23]
  PIN bt_d[24]
    DIRECTION OUTPUT ;
    USE SIGNAL ;
    PORT
      LAYER M3 ;
        RECT  53.208 0 53.226 0.144 ;
    END
  END bt_d[24]
  PIN bt_d[25]
    DIRECTION OUTPUT ;
    USE SIGNAL ;
    PORT
      LAYER M5 ;
        RECT  53.232 0 53.256 0.192 ;
    END
  END bt_d[25]
  PIN bt_d[26]
    DIRECTION OUTPUT ;
    USE SIGNAL ;
    PORT
      LAYER M3 ;
        RECT  53.352 0 53.37 0.144 ;
    END
  END bt_d[26]
  PIN bt_d[27]
    DIRECTION OUTPUT ;
    USE SIGNAL ;
    PORT
      LAYER M5 ;
        RECT  53.376 0 53.4 0.192 ;
    END
  END bt_d[27]
  PIN bt_d[28]
    DIRECTION OUTPUT ;
    USE SIGNAL ;
    PORT
      LAYER M3 ;
        RECT  53.496 0 53.514 0.144 ;
    END
  END bt_d[28]
  PIN bt_d[29]
    DIRECTION OUTPUT ;
    USE SIGNAL ;
    PORT
      LAYER M5 ;
        RECT  53.52 0 53.544 0.192 ;
    END
  END bt_d[29]
  PIN bt_d[2]
    DIRECTION OUTPUT ;
    USE SIGNAL ;
    PORT
      LAYER M3 ;
        RECT  51.624 0 51.642 0.144 ;
    END
  END bt_d[2]
  PIN bt_d[30]
    DIRECTION OUTPUT ;
    USE SIGNAL ;
    PORT
      LAYER M3 ;
        RECT  53.64 0 53.658 0.144 ;
    END
  END bt_d[30]
  PIN bt_d[31]
    DIRECTION OUTPUT ;
    USE SIGNAL ;
    PORT
      LAYER M5 ;
        RECT  53.664 0 53.688 0.192 ;
    END
  END bt_d[31]
  PIN bt_d[3]
    DIRECTION OUTPUT ;
    USE SIGNAL ;
    PORT
      LAYER M5 ;
        RECT  51.648 0 51.672 0.192 ;
    END
  END bt_d[3]
  PIN bt_d[4]
    DIRECTION OUTPUT ;
    USE SIGNAL ;
    PORT
      LAYER M3 ;
        RECT  51.768 0 51.786 0.144 ;
    END
  END bt_d[4]
  PIN bt_d[5]
    DIRECTION OUTPUT ;
    USE SIGNAL ;
    PORT
      LAYER M5 ;
        RECT  51.792 0 51.816 0.192 ;
    END
  END bt_d[5]
  PIN bt_d[6]
    DIRECTION OUTPUT ;
    USE SIGNAL ;
    PORT
      LAYER M3 ;
        RECT  51.912 0 51.93 0.144 ;
    END
  END bt_d[6]
  PIN bt_d[7]
    DIRECTION OUTPUT ;
    USE SIGNAL ;
    PORT
      LAYER M5 ;
        RECT  51.936 0 51.96 0.192 ;
    END
  END bt_d[7]
  PIN bt_d[8]
    DIRECTION OUTPUT ;
    USE SIGNAL ;
    PORT
      LAYER M3 ;
        RECT  52.056 0 52.074 0.144 ;
    END
  END bt_d[8]
  PIN bt_d[9]
    DIRECTION OUTPUT ;
    USE SIGNAL ;
    PORT
      LAYER M5 ;
        RECT  52.08 0 52.104 0.192 ;
    END
  END bt_d[9]
  PIN clk
    DIRECTION INPUT ;
    USE SIGNAL ;
    PORT
      LAYER M4 ;
        RECT  0 44.304 0.192 44.328 ;
    END
    PORT
      LAYER M4 ;
        RECT  0.156 44.304 0.205 44.328 ;
    END
  END clk
  PIN consume
    DIRECTION INPUT ;
    USE SIGNAL ;
    PORT
      LAYER M4 ;
        RECT  0 38.88 0.192 38.904 ;
    END
  END consume
  PIN h_hi[0]
    DIRECTION INPUT ;
    USE SIGNAL ;
    PORT
      LAYER M4 ;
        RECT  0 40.464 0.192 40.488 ;
    END
  END h_hi[0]
  PIN h_hi[1]
    DIRECTION INPUT ;
    USE SIGNAL ;
    PORT
      LAYER M4 ;
        RECT  0 40.608 0.192 40.632 ;
    END
  END h_hi[1]
  PIN h_hi[2]
    DIRECTION INPUT ;
    USE SIGNAL ;
    PORT
      LAYER M4 ;
        RECT  0 40.752 0.192 40.776 ;
    END
  END h_hi[2]
  PIN h_hi[3]
    DIRECTION INPUT ;
    USE SIGNAL ;
    PORT
      LAYER M4 ;
        RECT  0 40.896 0.192 40.92 ;
    END
  END h_hi[3]
  PIN h_hi[4]
    DIRECTION INPUT ;
    USE SIGNAL ;
    PORT
      LAYER M4 ;
        RECT  0 41.04 0.192 41.064 ;
    END
  END h_hi[4]
  PIN h_hi[5]
    DIRECTION INPUT ;
    USE SIGNAL ;
    PORT
      LAYER M4 ;
        RECT  0 41.184 0.192 41.208 ;
    END
  END h_hi[5]
  PIN h_hi[6]
    DIRECTION INPUT ;
    USE SIGNAL ;
    PORT
      LAYER M4 ;
        RECT  0 41.328 0.192 41.352 ;
    END
  END h_hi[6]
  PIN h_hi[7]
    DIRECTION INPUT ;
    USE SIGNAL ;
    PORT
      LAYER M4 ;
        RECT  0 41.472 0.192 41.496 ;
    END
  END h_hi[7]
  PIN h_hi[8]
    DIRECTION INPUT ;
    USE SIGNAL ;
    PORT
      LAYER M4 ;
        RECT  0 41.616 0.192 41.64 ;
    END
  END h_hi[8]
  PIN hw_gate
    DIRECTION INPUT ;
    USE SIGNAL ;
    PORT
      LAYER M4 ;
        RECT  0 42.192 0.192 42.216 ;
    END
  END hw_gate
  PIN hw_low[0]
    DIRECTION INPUT ;
    USE SIGNAL ;
    PORT
      LAYER M4 ;
        RECT  0 41.76 0.192 41.784 ;
    END
  END hw_low[0]
  PIN hw_low[1]
    DIRECTION INPUT ;
    USE SIGNAL ;
    PORT
      LAYER M4 ;
        RECT  0 41.904 0.192 41.928 ;
    END
  END hw_low[1]
  PIN hw_low[2]
    DIRECTION INPUT ;
    USE SIGNAL ;
    PORT
      LAYER M4 ;
        RECT  0 42.048 0.192 42.072 ;
    END
  END hw_low[2]
  PIN par
    DIRECTION INPUT ;
    USE SIGNAL ;
    PORT
      LAYER M4 ;
        RECT  0 39.024 0.192 39.048 ;
    END
  END par
  PIN rst_n
    DIRECTION INPUT ;
    USE SIGNAL ;
    PORT
      LAYER M4 ;
        RECT  0 43.296 0.192 43.32 ;
    END
    PORT
      LAYER M4 ;
        RECT  0.156 43.2 0.245 43.32 ;
    END
  END rst_n
  PIN VSS
    DIRECTION INOUT ;
    USE GROUND ;
    PORT
      LAYER M5 ;
        RECT  137.4 2.137 137.52 84.263 ;
        RECT  132 2.137 132.12 84.263 ;
        RECT  126.6 2.137 126.72 84.263 ;
        RECT  121.2 2.137 121.32 84.263 ;
        RECT  115.8 2.137 115.92 84.263 ;
        RECT  110.4 2.137 110.52 84.263 ;
        RECT  105 2.137 105.12 84.263 ;
        RECT  99.6 2.137 99.72 84.263 ;
        RECT  94.2 2.137 94.32 84.263 ;
        RECT  88.8 2.137 88.92 84.263 ;
        RECT  83.4 2.137 83.52 84.263 ;
        RECT  78 2.137 78.12 84.263 ;
        RECT  72.6 2.137 72.72 84.263 ;
        RECT  67.2 2.137 67.32 84.263 ;
        RECT  61.8 2.137 61.92 84.263 ;
        RECT  56.4 2.137 56.52 84.263 ;
        RECT  51 2.137 51.12 84.263 ;
        RECT  45.6 2.137 45.72 84.263 ;
        RECT  40.2 2.137 40.32 84.263 ;
        RECT  34.8 2.137 34.92 84.263 ;
        RECT  29.4 2.137 29.52 84.263 ;
        RECT  24 2.137 24.12 84.263 ;
        RECT  18.6 2.137 18.72 84.263 ;
        RECT  13.2 2.137 13.32 84.263 ;
        RECT  7.8 2.137 7.92 84.263 ;
        RECT  2.4 2.137 2.52 84.263 ;
    END
  END VSS
  PIN VDD
    DIRECTION INOUT ;
    USE POWER ;
    PORT
      LAYER M5 ;
        RECT  137.592 2.151 137.712 84.249 ;
        RECT  132.192 2.151 132.312 84.249 ;
        RECT  126.792 2.151 126.912 84.249 ;
        RECT  121.392 2.151 121.512 84.249 ;
        RECT  115.992 2.151 116.112 84.249 ;
        RECT  110.592 2.151 110.712 84.249 ;
        RECT  105.192 2.151 105.312 84.249 ;
        RECT  99.792 2.151 99.912 84.249 ;
        RECT  94.392 2.151 94.512 84.249 ;
        RECT  88.992 2.151 89.112 84.249 ;
        RECT  83.592 2.151 83.712 84.249 ;
        RECT  78.192 2.151 78.312 84.249 ;
        RECT  72.792 2.151 72.912 84.249 ;
        RECT  67.392 2.151 67.512 84.249 ;
        RECT  61.992 2.151 62.112 84.249 ;
        RECT  56.592 2.151 56.712 84.249 ;
        RECT  51.192 2.151 51.312 84.249 ;
        RECT  45.792 2.151 45.912 84.249 ;
        RECT  40.392 2.151 40.512 84.249 ;
        RECT  34.992 2.151 35.112 84.249 ;
        RECT  29.592 2.151 29.712 84.249 ;
        RECT  24.192 2.151 24.312 84.249 ;
        RECT  18.792 2.151 18.912 84.249 ;
        RECT  13.392 2.151 13.512 84.249 ;
        RECT  7.992 2.151 8.112 84.249 ;
        RECT  2.592 2.151 2.712 84.249 ;
    END
  END VDD
  # OT_OBS_CLOSED layer=M5 d_um=1.536 added=170
  OBS
    LAYER RVTN ;
     RECT  2.16 2.16 140.4 2.295 ;
     RECT  2.16 2.565 140.4 2.835 ;
     RECT  2.16 3.105 140.4 3.375 ;
     RECT  2.16 3.645 140.4 3.915 ;
     RECT  2.16 4.185 140.4 4.455 ;
     RECT  2.16 4.725 140.4 4.995 ;
     RECT  2.16 5.265 140.4 5.535 ;
     RECT  2.16 5.805 140.4 6.075 ;
     RECT  2.16 6.345 140.4 6.615 ;
     RECT  2.16 6.885 140.4 7.155 ;
     RECT  2.16 7.425 140.4 7.695 ;
     RECT  2.16 7.965 140.4 8.235 ;
     RECT  2.16 8.505 140.4 8.775 ;
     RECT  2.16 9.045 140.4 9.315 ;
     RECT  2.16 9.585 140.4 9.855 ;
     RECT  2.16 10.125 140.4 10.395 ;
     RECT  2.16 10.665 140.4 10.935 ;
     RECT  2.16 11.205 140.4 11.475 ;
     RECT  2.16 11.745 140.4 12.015 ;
     RECT  2.16 12.285 140.4 12.555 ;
     RECT  2.16 12.825 140.4 13.095 ;
     RECT  2.16 13.365 140.4 13.635 ;
     RECT  2.16 13.905 140.4 14.175 ;
     RECT  2.16 14.445 140.4 14.715 ;
     RECT  2.16 14.985 140.4 15.255 ;
     RECT  2.16 15.525 140.4 15.795 ;
     RECT  2.16 16.065 140.4 16.335 ;
     RECT  2.16 16.605 140.4 16.875 ;
     RECT  2.16 17.145 140.4 17.415 ;
     RECT  2.16 17.685 140.4 17.955 ;
     RECT  2.16 18.225 140.4 18.495 ;
     RECT  2.16 18.765 140.4 19.035 ;
     RECT  2.16 19.305 140.4 19.575 ;
     RECT  2.16 19.845 140.4 20.115 ;
     RECT  2.16 20.385 20.412 20.655 ;
     RECT  119.34 20.385 140.4 20.655 ;
     RECT  2.16 20.925 20.412 21.195 ;
     RECT  119.34 20.925 140.4 21.195 ;
     RECT  2.16 21.465 20.412 21.735 ;
     RECT  119.34 21.465 140.4 21.735 ;
     RECT  2.16 22.005 20.412 22.275 ;
     RECT  119.34 22.005 140.4 22.275 ;
     RECT  2.16 22.545 20.412 22.815 ;
     RECT  119.34 22.545 140.4 22.815 ;
     RECT  2.16 23.085 20.412 23.355 ;
     RECT  119.34 23.085 140.4 23.355 ;
     RECT  2.16 23.625 20.412 23.895 ;
     RECT  119.34 23.625 140.4 23.895 ;
     RECT  2.16 24.165 20.412 24.435 ;
     RECT  119.34 24.165 140.4 24.435 ;
     RECT  2.16 24.705 20.412 24.975 ;
     RECT  119.34 24.705 140.4 24.975 ;
     RECT  2.16 25.245 20.412 25.515 ;
     RECT  119.34 25.245 140.4 25.515 ;
     RECT  2.16 25.785 20.412 26.055 ;
     RECT  119.34 25.785 140.4 26.055 ;
     RECT  2.16 26.325 20.412 26.595 ;
     RECT  119.34 26.325 140.4 26.595 ;
     RECT  2.16 26.865 20.412 27.135 ;
     RECT  119.34 26.865 140.4 27.135 ;
     RECT  2.16 27.405 20.412 27.675 ;
     RECT  119.34 27.405 140.4 27.675 ;
     RECT  2.16 27.945 20.412 28.215 ;
     RECT  119.34 27.945 140.4 28.215 ;
     RECT  2.16 28.485 20.412 28.755 ;
     RECT  119.34 28.485 140.4 28.755 ;
     RECT  2.16 29.025 20.412 29.295 ;
     RECT  119.34 29.025 140.4 29.295 ;
     RECT  2.16 29.565 20.412 29.835 ;
     RECT  119.34 29.565 140.4 29.835 ;
     RECT  2.16 30.105 20.412 30.375 ;
     RECT  119.34 30.105 140.4 30.375 ;
     RECT  2.16 30.645 20.412 30.915 ;
     RECT  119.34 30.645 140.4 30.915 ;
     RECT  2.16 31.185 20.412 31.455 ;
     RECT  119.34 31.185 140.4 31.455 ;
     RECT  2.16 31.725 20.412 31.995 ;
     RECT  119.34 31.725 140.4 31.995 ;
     RECT  2.16 32.265 20.412 32.535 ;
     RECT  119.34 32.265 140.4 32.535 ;
     RECT  2.16 32.805 20.412 33.075 ;
     RECT  119.34 32.805 140.4 33.075 ;
     RECT  2.16 33.345 20.412 33.615 ;
     RECT  119.34 33.345 140.4 33.615 ;
     RECT  2.16 33.885 20.412 34.155 ;
     RECT  119.34 33.885 140.4 34.155 ;
     RECT  2.16 34.425 20.412 34.695 ;
     RECT  119.34 34.425 140.4 34.695 ;
     RECT  2.16 34.965 20.412 35.235 ;
     RECT  119.34 34.965 140.4 35.235 ;
     RECT  2.16 35.505 20.412 35.775 ;
     RECT  119.34 35.505 140.4 35.775 ;
     RECT  2.16 36.045 20.412 36.315 ;
     RECT  119.34 36.045 140.4 36.315 ;
     RECT  2.16 36.585 20.412 36.855 ;
     RECT  119.34 36.585 140.4 36.855 ;
     RECT  2.16 37.125 20.412 37.395 ;
     RECT  119.34 37.125 140.4 37.395 ;
     RECT  2.16 37.665 20.412 37.935 ;
     RECT  119.34 37.665 140.4 37.935 ;
     RECT  2.16 38.205 20.412 38.475 ;
     RECT  119.34 38.205 140.4 38.475 ;
     RECT  2.16 38.745 20.412 39.015 ;
     RECT  119.34 38.745 140.4 39.015 ;
     RECT  2.16 39.285 20.412 39.555 ;
     RECT  119.34 39.285 140.4 39.555 ;
     RECT  2.16 39.825 20.412 40.095 ;
     RECT  119.34 39.825 140.4 40.095 ;
     RECT  2.16 40.365 20.412 40.635 ;
     RECT  119.34 40.365 140.4 40.635 ;
     RECT  2.16 40.905 20.412 41.175 ;
     RECT  119.34 40.905 140.4 41.175 ;
     RECT  2.16 41.445 20.412 41.715 ;
     RECT  119.34 41.445 140.4 41.715 ;
     RECT  2.16 41.985 20.412 42.255 ;
     RECT  119.34 41.985 140.4 42.255 ;
     RECT  2.16 42.525 20.412 42.795 ;
     RECT  119.34 42.525 140.4 42.795 ;
     RECT  2.16 43.065 20.412 43.335 ;
     RECT  119.34 43.065 140.4 43.335 ;
     RECT  2.16 43.605 20.412 43.875 ;
     RECT  119.34 43.605 140.4 43.875 ;
     RECT  2.16 44.145 20.412 44.415 ;
     RECT  119.34 44.145 140.4 44.415 ;
     RECT  2.16 44.685 20.412 44.955 ;
     RECT  119.34 44.685 140.4 44.955 ;
     RECT  2.16 45.225 20.412 45.495 ;
     RECT  119.34 45.225 140.4 45.495 ;
     RECT  2.16 45.765 20.412 46.035 ;
     RECT  119.34 45.765 140.4 46.035 ;
     RECT  2.16 46.305 20.412 46.575 ;
     RECT  119.34 46.305 140.4 46.575 ;
     RECT  2.16 46.845 20.412 47.115 ;
     RECT  119.34 46.845 140.4 47.115 ;
     RECT  2.16 47.385 20.412 47.655 ;
     RECT  119.34 47.385 140.4 47.655 ;
     RECT  2.16 47.925 20.412 48.195 ;
     RECT  119.34 47.925 140.4 48.195 ;
     RECT  2.16 48.465 20.412 48.735 ;
     RECT  119.34 48.465 140.4 48.735 ;
     RECT  2.16 49.005 20.412 49.275 ;
     RECT  119.34 49.005 140.4 49.275 ;
     RECT  2.16 49.545 20.412 49.815 ;
     RECT  119.34 49.545 140.4 49.815 ;
     RECT  2.16 50.085 20.412 50.355 ;
     RECT  119.34 50.085 140.4 50.355 ;
     RECT  2.16 50.625 20.412 50.895 ;
     RECT  119.34 50.625 140.4 50.895 ;
     RECT  2.16 51.165 20.412 51.435 ;
     RECT  119.34 51.165 140.4 51.435 ;
     RECT  2.16 51.705 20.412 51.975 ;
     RECT  119.34 51.705 140.4 51.975 ;
     RECT  2.16 52.245 20.412 52.515 ;
     RECT  119.34 52.245 140.4 52.515 ;
     RECT  2.16 52.785 20.412 53.055 ;
     RECT  119.34 52.785 140.4 53.055 ;
     RECT  2.16 53.325 20.412 53.595 ;
     RECT  119.34 53.325 140.4 53.595 ;
     RECT  2.16 53.865 20.412 54.135 ;
     RECT  119.34 53.865 140.4 54.135 ;
     RECT  2.16 54.405 20.412 54.675 ;
     RECT  119.34 54.405 140.4 54.675 ;
     RECT  2.16 54.945 20.412 55.215 ;
     RECT  119.34 54.945 140.4 55.215 ;
     RECT  2.16 55.485 20.412 55.755 ;
     RECT  119.34 55.485 140.4 55.755 ;
     RECT  2.16 56.025 20.412 56.295 ;
     RECT  119.34 56.025 140.4 56.295 ;
     RECT  2.16 56.565 20.412 56.835 ;
     RECT  119.34 56.565 140.4 56.835 ;
     RECT  2.16 57.105 20.412 57.375 ;
     RECT  119.34 57.105 140.4 57.375 ;
     RECT  2.16 57.645 20.412 57.915 ;
     RECT  119.34 57.645 140.4 57.915 ;
     RECT  2.16 58.185 20.412 58.455 ;
     RECT  119.34 58.185 140.4 58.455 ;
     RECT  2.16 58.725 20.412 58.995 ;
     RECT  119.34 58.725 140.4 58.995 ;
     RECT  2.16 59.265 20.412 59.535 ;
     RECT  119.34 59.265 140.4 59.535 ;
     RECT  2.16 59.805 20.412 60.075 ;
     RECT  119.34 59.805 140.4 60.075 ;
     RECT  2.16 60.345 20.412 60.615 ;
     RECT  119.34 60.345 140.4 60.615 ;
     RECT  2.16 60.885 20.412 61.155 ;
     RECT  119.34 60.885 140.4 61.155 ;
     RECT  2.16 61.425 20.412 61.695 ;
     RECT  119.34 61.425 140.4 61.695 ;
     RECT  2.16 61.965 20.412 62.235 ;
     RECT  119.34 61.965 140.4 62.235 ;
     RECT  2.16 62.505 20.412 62.775 ;
     RECT  119.34 62.505 140.4 62.775 ;
     RECT  2.16 63.045 20.412 63.315 ;
     RECT  119.34 63.045 140.4 63.315 ;
     RECT  2.16 63.585 20.412 63.855 ;
     RECT  119.34 63.585 140.4 63.855 ;
     RECT  2.16 64.125 20.412 64.395 ;
     RECT  119.34 64.125 140.4 64.395 ;
     RECT  2.16 64.665 20.412 64.935 ;
     RECT  119.34 64.665 140.4 64.935 ;
     RECT  2.16 65.205 20.412 65.475 ;
     RECT  119.34 65.205 140.4 65.475 ;
     RECT  2.16 65.745 140.4 66.015 ;
     RECT  2.16 66.285 140.4 66.555 ;
     RECT  2.16 66.825 140.4 67.095 ;
     RECT  2.16 67.365 140.4 67.635 ;
     RECT  2.16 67.905 140.4 68.175 ;
     RECT  2.16 68.445 140.4 68.715 ;
     RECT  2.16 68.985 140.4 69.255 ;
     RECT  2.16 69.525 140.4 69.795 ;
     RECT  2.16 70.065 140.4 70.335 ;
     RECT  2.16 70.605 140.4 70.875 ;
     RECT  2.16 71.145 140.4 71.415 ;
     RECT  2.16 71.685 140.4 71.955 ;
     RECT  2.16 72.225 140.4 72.495 ;
     RECT  2.16 72.765 140.4 73.035 ;
     RECT  2.16 73.305 140.4 73.575 ;
     RECT  2.16 73.845 140.4 74.115 ;
     RECT  2.16 74.385 140.4 74.655 ;
     RECT  2.16 74.925 140.4 75.195 ;
     RECT  2.16 75.465 140.4 75.735 ;
     RECT  2.16 76.005 140.4 76.275 ;
     RECT  2.16 76.545 140.4 76.815 ;
     RECT  2.16 77.085 140.4 77.355 ;
     RECT  2.16 77.625 140.4 77.895 ;
     RECT  2.16 78.165 140.4 78.435 ;
     RECT  2.16 78.705 140.4 78.975 ;
     RECT  2.16 79.245 140.4 79.515 ;
     RECT  2.16 79.785 140.4 80.055 ;
     RECT  2.16 80.325 140.4 80.595 ;
     RECT  2.16 80.865 140.4 81.135 ;
     RECT  2.16 81.405 140.4 81.675 ;
     RECT  2.16 81.945 140.4 82.215 ;
     RECT  2.16 82.485 140.4 82.755 ;
     RECT  2.16 83.025 140.4 83.295 ;
     RECT  2.16 83.565 140.4 83.835 ;
     RECT  2.16 84.105 140.4 84.24 ;
    LAYER RVTP ;
     RECT  2.16 2.295 140.4 2.565 ;
     RECT  2.16 2.835 140.4 3.105 ;
     RECT  2.16 3.375 140.4 3.645 ;
     RECT  2.16 3.915 140.4 4.185 ;
     RECT  2.16 4.455 140.4 4.725 ;
     RECT  2.16 4.995 140.4 5.265 ;
     RECT  2.16 5.535 140.4 5.805 ;
     RECT  2.16 6.075 140.4 6.345 ;
     RECT  2.16 6.615 140.4 6.885 ;
     RECT  2.16 7.155 140.4 7.425 ;
     RECT  2.16 7.695 140.4 7.965 ;
     RECT  2.16 8.235 140.4 8.505 ;
     RECT  2.16 8.775 140.4 9.045 ;
     RECT  2.16 9.315 140.4 9.585 ;
     RECT  2.16 9.855 140.4 10.125 ;
     RECT  2.16 10.395 140.4 10.665 ;
     RECT  2.16 10.935 140.4 11.205 ;
     RECT  2.16 11.475 140.4 11.745 ;
     RECT  2.16 12.015 140.4 12.285 ;
     RECT  2.16 12.555 140.4 12.825 ;
     RECT  2.16 13.095 140.4 13.365 ;
     RECT  2.16 13.635 140.4 13.905 ;
     RECT  2.16 14.175 140.4 14.445 ;
     RECT  2.16 14.715 140.4 14.985 ;
     RECT  2.16 15.255 140.4 15.525 ;
     RECT  2.16 15.795 140.4 16.065 ;
     RECT  2.16 16.335 140.4 16.605 ;
     RECT  2.16 16.875 140.4 17.145 ;
     RECT  2.16 17.415 140.4 17.685 ;
     RECT  2.16 17.955 140.4 18.225 ;
     RECT  2.16 18.495 140.4 18.765 ;
     RECT  2.16 19.035 140.4 19.305 ;
     RECT  2.16 19.575 140.4 19.845 ;
     RECT  2.16 20.115 140.4 20.25 ;
     RECT  2.16 20.25 20.412 20.385 ;
     RECT  119.34 20.25 140.4 20.385 ;
     RECT  2.16 20.655 20.412 20.925 ;
     RECT  119.34 20.655 140.4 20.925 ;
     RECT  2.16 21.195 20.412 21.465 ;
     RECT  119.34 21.195 140.4 21.465 ;
     RECT  2.16 21.735 20.412 22.005 ;
     RECT  119.34 21.735 140.4 22.005 ;
     RECT  2.16 22.275 20.412 22.545 ;
     RECT  119.34 22.275 140.4 22.545 ;
     RECT  2.16 22.815 20.412 23.085 ;
     RECT  119.34 22.815 140.4 23.085 ;
     RECT  2.16 23.355 20.412 23.625 ;
     RECT  119.34 23.355 140.4 23.625 ;
     RECT  2.16 23.895 20.412 24.165 ;
     RECT  119.34 23.895 140.4 24.165 ;
     RECT  2.16 24.435 20.412 24.705 ;
     RECT  119.34 24.435 140.4 24.705 ;
     RECT  2.16 24.975 20.412 25.245 ;
     RECT  119.34 24.975 140.4 25.245 ;
     RECT  2.16 25.515 20.412 25.785 ;
     RECT  119.34 25.515 140.4 25.785 ;
     RECT  2.16 26.055 20.412 26.325 ;
     RECT  119.34 26.055 140.4 26.325 ;
     RECT  2.16 26.595 20.412 26.865 ;
     RECT  119.34 26.595 140.4 26.865 ;
     RECT  2.16 27.135 20.412 27.405 ;
     RECT  119.34 27.135 140.4 27.405 ;
     RECT  2.16 27.675 20.412 27.945 ;
     RECT  119.34 27.675 140.4 27.945 ;
     RECT  2.16 28.215 20.412 28.485 ;
     RECT  119.34 28.215 140.4 28.485 ;
     RECT  2.16 28.755 20.412 29.025 ;
     RECT  119.34 28.755 140.4 29.025 ;
     RECT  2.16 29.295 20.412 29.565 ;
     RECT  119.34 29.295 140.4 29.565 ;
     RECT  2.16 29.835 20.412 30.105 ;
     RECT  119.34 29.835 140.4 30.105 ;
     RECT  2.16 30.375 20.412 30.645 ;
     RECT  119.34 30.375 140.4 30.645 ;
     RECT  2.16 30.915 20.412 31.185 ;
     RECT  119.34 30.915 140.4 31.185 ;
     RECT  2.16 31.455 20.412 31.725 ;
     RECT  119.34 31.455 140.4 31.725 ;
     RECT  2.16 31.995 20.412 32.265 ;
     RECT  119.34 31.995 140.4 32.265 ;
     RECT  2.16 32.535 20.412 32.805 ;
     RECT  119.34 32.535 140.4 32.805 ;
     RECT  2.16 33.075 20.412 33.345 ;
     RECT  119.34 33.075 140.4 33.345 ;
     RECT  2.16 33.615 20.412 33.885 ;
     RECT  119.34 33.615 140.4 33.885 ;
     RECT  2.16 34.155 20.412 34.425 ;
     RECT  119.34 34.155 140.4 34.425 ;
     RECT  2.16 34.695 20.412 34.965 ;
     RECT  119.34 34.695 140.4 34.965 ;
     RECT  2.16 35.235 20.412 35.505 ;
     RECT  119.34 35.235 140.4 35.505 ;
     RECT  2.16 35.775 20.412 36.045 ;
     RECT  119.34 35.775 140.4 36.045 ;
     RECT  2.16 36.315 20.412 36.585 ;
     RECT  119.34 36.315 140.4 36.585 ;
     RECT  2.16 36.855 20.412 37.125 ;
     RECT  119.34 36.855 140.4 37.125 ;
     RECT  2.16 37.395 20.412 37.665 ;
     RECT  119.34 37.395 140.4 37.665 ;
     RECT  2.16 37.935 20.412 38.205 ;
     RECT  119.34 37.935 140.4 38.205 ;
     RECT  2.16 38.475 20.412 38.745 ;
     RECT  119.34 38.475 140.4 38.745 ;
     RECT  2.16 39.015 20.412 39.285 ;
     RECT  119.34 39.015 140.4 39.285 ;
     RECT  2.16 39.555 20.412 39.825 ;
     RECT  119.34 39.555 140.4 39.825 ;
     RECT  2.16 40.095 20.412 40.365 ;
     RECT  119.34 40.095 140.4 40.365 ;
     RECT  2.16 40.635 20.412 40.905 ;
     RECT  119.34 40.635 140.4 40.905 ;
     RECT  2.16 41.175 20.412 41.445 ;
     RECT  119.34 41.175 140.4 41.445 ;
     RECT  2.16 41.715 20.412 41.985 ;
     RECT  119.34 41.715 140.4 41.985 ;
     RECT  2.16 42.255 20.412 42.525 ;
     RECT  119.34 42.255 140.4 42.525 ;
     RECT  2.16 42.795 20.412 43.065 ;
     RECT  119.34 42.795 140.4 43.065 ;
     RECT  2.16 43.335 20.412 43.605 ;
     RECT  119.34 43.335 140.4 43.605 ;
     RECT  2.16 43.875 20.412 44.145 ;
     RECT  119.34 43.875 140.4 44.145 ;
     RECT  2.16 44.415 20.412 44.685 ;
     RECT  119.34 44.415 140.4 44.685 ;
     RECT  2.16 44.955 20.412 45.225 ;
     RECT  119.34 44.955 140.4 45.225 ;
     RECT  2.16 45.495 20.412 45.765 ;
     RECT  119.34 45.495 140.4 45.765 ;
     RECT  2.16 46.035 20.412 46.305 ;
     RECT  119.34 46.035 140.4 46.305 ;
     RECT  2.16 46.575 20.412 46.845 ;
     RECT  119.34 46.575 140.4 46.845 ;
     RECT  2.16 47.115 20.412 47.385 ;
     RECT  119.34 47.115 140.4 47.385 ;
     RECT  2.16 47.655 20.412 47.925 ;
     RECT  119.34 47.655 140.4 47.925 ;
     RECT  2.16 48.195 20.412 48.465 ;
     RECT  119.34 48.195 140.4 48.465 ;
     RECT  2.16 48.735 20.412 49.005 ;
     RECT  119.34 48.735 140.4 49.005 ;
     RECT  2.16 49.275 20.412 49.545 ;
     RECT  119.34 49.275 140.4 49.545 ;
     RECT  2.16 49.815 20.412 50.085 ;
     RECT  119.34 49.815 140.4 50.085 ;
     RECT  2.16 50.355 20.412 50.625 ;
     RECT  119.34 50.355 140.4 50.625 ;
     RECT  2.16 50.895 20.412 51.165 ;
     RECT  119.34 50.895 140.4 51.165 ;
     RECT  2.16 51.435 20.412 51.705 ;
     RECT  119.34 51.435 140.4 51.705 ;
     RECT  2.16 51.975 20.412 52.245 ;
     RECT  119.34 51.975 140.4 52.245 ;
     RECT  2.16 52.515 20.412 52.785 ;
     RECT  119.34 52.515 140.4 52.785 ;
     RECT  2.16 53.055 20.412 53.325 ;
     RECT  119.34 53.055 140.4 53.325 ;
     RECT  2.16 53.595 20.412 53.865 ;
     RECT  119.34 53.595 140.4 53.865 ;
     RECT  2.16 54.135 20.412 54.405 ;
     RECT  119.34 54.135 140.4 54.405 ;
     RECT  2.16 54.675 20.412 54.945 ;
     RECT  119.34 54.675 140.4 54.945 ;
     RECT  2.16 55.215 20.412 55.485 ;
     RECT  119.34 55.215 140.4 55.485 ;
     RECT  2.16 55.755 20.412 56.025 ;
     RECT  119.34 55.755 140.4 56.025 ;
     RECT  2.16 56.295 20.412 56.565 ;
     RECT  119.34 56.295 140.4 56.565 ;
     RECT  2.16 56.835 20.412 57.105 ;
     RECT  119.34 56.835 140.4 57.105 ;
     RECT  2.16 57.375 20.412 57.645 ;
     RECT  119.34 57.375 140.4 57.645 ;
     RECT  2.16 57.915 20.412 58.185 ;
     RECT  119.34 57.915 140.4 58.185 ;
     RECT  2.16 58.455 20.412 58.725 ;
     RECT  119.34 58.455 140.4 58.725 ;
     RECT  2.16 58.995 20.412 59.265 ;
     RECT  119.34 58.995 140.4 59.265 ;
     RECT  2.16 59.535 20.412 59.805 ;
     RECT  119.34 59.535 140.4 59.805 ;
     RECT  2.16 60.075 20.412 60.345 ;
     RECT  119.34 60.075 140.4 60.345 ;
     RECT  2.16 60.615 20.412 60.885 ;
     RECT  119.34 60.615 140.4 60.885 ;
     RECT  2.16 61.155 20.412 61.425 ;
     RECT  119.34 61.155 140.4 61.425 ;
     RECT  2.16 61.695 20.412 61.965 ;
     RECT  119.34 61.695 140.4 61.965 ;
     RECT  2.16 62.235 20.412 62.505 ;
     RECT  119.34 62.235 140.4 62.505 ;
     RECT  2.16 62.775 20.412 63.045 ;
     RECT  119.34 62.775 140.4 63.045 ;
     RECT  2.16 63.315 20.412 63.585 ;
     RECT  119.34 63.315 140.4 63.585 ;
     RECT  2.16 63.855 20.412 64.125 ;
     RECT  119.34 63.855 140.4 64.125 ;
     RECT  2.16 64.395 20.412 64.665 ;
     RECT  119.34 64.395 140.4 64.665 ;
     RECT  2.16 64.935 20.412 65.205 ;
     RECT  119.34 64.935 140.4 65.205 ;
     RECT  2.16 65.475 20.412 65.61 ;
     RECT  119.34 65.475 140.4 65.61 ;
     RECT  2.16 65.61 140.4 65.745 ;
     RECT  2.16 66.015 140.4 66.285 ;
     RECT  2.16 66.555 140.4 66.825 ;
     RECT  2.16 67.095 140.4 67.365 ;
     RECT  2.16 67.635 140.4 67.905 ;
     RECT  2.16 68.175 140.4 68.445 ;
     RECT  2.16 68.715 140.4 68.985 ;
     RECT  2.16 69.255 140.4 69.525 ;
     RECT  2.16 69.795 140.4 70.065 ;
     RECT  2.16 70.335 140.4 70.605 ;
     RECT  2.16 70.875 140.4 71.145 ;
     RECT  2.16 71.415 140.4 71.685 ;
     RECT  2.16 71.955 140.4 72.225 ;
     RECT  2.16 72.495 140.4 72.765 ;
     RECT  2.16 73.035 140.4 73.305 ;
     RECT  2.16 73.575 140.4 73.845 ;
     RECT  2.16 74.115 140.4 74.385 ;
     RECT  2.16 74.655 140.4 74.925 ;
     RECT  2.16 75.195 140.4 75.465 ;
     RECT  2.16 75.735 140.4 76.005 ;
     RECT  2.16 76.275 140.4 76.545 ;
     RECT  2.16 76.815 140.4 77.085 ;
     RECT  2.16 77.355 140.4 77.625 ;
     RECT  2.16 77.895 140.4 78.165 ;
     RECT  2.16 78.435 140.4 78.705 ;
     RECT  2.16 78.975 140.4 79.245 ;
     RECT  2.16 79.515 140.4 79.785 ;
     RECT  2.16 80.055 140.4 80.325 ;
     RECT  2.16 80.595 140.4 80.865 ;
     RECT  2.16 81.135 140.4 81.405 ;
     RECT  2.16 81.675 140.4 81.945 ;
     RECT  2.16 82.215 140.4 82.485 ;
     RECT  2.16 82.755 140.4 83.025 ;
     RECT  2.16 83.295 140.4 83.565 ;
     RECT  2.16 83.835 140.4 84.105 ;
    LAYER M1 ;
     RECT  2.16 2.151 140.4 20.259 ;
     RECT  22.464 22.464 117.288 63.528 ;
     RECT  2.16 20.259 20.412 65.601 ;
     RECT  119.34 20.259 140.4 65.601 ;
     RECT  2.16 65.601 140.4 84.249 ;
    LAYER M2 ;
     RECT  0.211 39.6 0.283 40.05 ;
     RECT  0.211 37.98 0.319 37.998 ;
     RECT  0.283 39.06 0.319 40.05 ;
     RECT  0.319 37.98 0.355 40.05 ;
     RECT  0.211 42.192 0.535 42.21 ;
     RECT  0.535 41.994 1.147 42.318 ;
     RECT  1.147 41.922 1.543 43.02 ;
     RECT  0.355 37.908 2.16 40.05 ;
     RECT  0.247 41.112 2.16 41.13 ;
     RECT  1.543 41.922 2.16 43.092 ;
     RECT  0.031 51.372 2.16 51.39 ;
     RECT  2.16 2.151 17.671 84.249 ;
     RECT  17.671 2.106 17.995 84.249 ;
     RECT  17.995 2.034 18.535 84.249 ;
     RECT  18.535 1.962 18.823 84.249 ;
     RECT  18.823 1.8 19.255 84.249 ;
     RECT  19.255 1.116 19.967 84.249 ;
     RECT  19.967 1.422 20.412 84.249 ;
     RECT  20.412 24.102 20.435 25.812 ;
     RECT  20.412 30.852 20.507 48.186 ;
     RECT  20.507 33.93 20.543 48.186 ;
     RECT  20.412 1.422 21.119 22.806 ;
     RECT  20.435 24.102 21.119 25.272 ;
     RECT  20.412 27.036 21.119 29.862 ;
     RECT  20.507 30.852 21.119 32.949 ;
     RECT  20.543 33.93 21.119 40.428 ;
     RECT  20.543 41.184 21.119 48.186 ;
     RECT  20.412 49.356 21.155 84.249 ;
     RECT  21.119 38.178 21.227 40.428 ;
     RECT  21.155 49.356 21.263 59.256 ;
     RECT  21.155 60.048 21.371 84.249 ;
     RECT  21.119 1.422 21.551 22.536 ;
     RECT  21.119 30.852 21.551 32.904 ;
     RECT  21.227 38.178 21.551 38.196 ;
     RECT  21.227 38.952 21.551 40.428 ;
     RECT  21.371 60.156 21.659 84.249 ;
     RECT  21.119 24.246 21.695 25.272 ;
     RECT  21.551 30.852 21.695 32.832 ;
     RECT  21.119 33.93 21.695 37.422 ;
     RECT  21.551 39.33 21.695 40.428 ;
     RECT  21.119 41.184 21.695 41.814 ;
     RECT  21.119 42.876 21.695 48.186 ;
     RECT  21.263 50.13 21.695 59.256 ;
     RECT  21.659 60.156 21.695 61.452 ;
     RECT  21.695 56.106 21.731 59.256 ;
     RECT  21.263 49.356 21.955 49.374 ;
     RECT  21.551 1.422 21.983 21.024 ;
     RECT  21.551 21.942 22.207 22.536 ;
     RECT  21.695 39.636 22.243 40.428 ;
     RECT  21.695 41.184 22.243 41.202 ;
     RECT  21.119 27.036 22.279 29.016 ;
     RECT  21.659 62.208 22.415 84.249 ;
     RECT  22.207 21.942 22.464 22.806 ;
     RECT  21.695 24.48 22.464 24.498 ;
     RECT  22.279 27.036 22.464 29.664 ;
     RECT  21.695 31.464 22.464 31.869 ;
     RECT  21.695 33.93 22.464 34.65 ;
     RECT  21.695 35.784 22.464 35.802 ;
     RECT  21.695 36.936 22.464 37.422 ;
     RECT  22.243 39.636 22.464 41.202 ;
     RECT  21.695 43.11 22.464 43.902 ;
     RECT  21.695 44.694 22.464 47.034 ;
     RECT  21.695 48.168 22.464 48.186 ;
     RECT  21.955 49.014 22.464 49.374 ;
     RECT  21.695 50.13 22.464 50.148 ;
     RECT  21.695 50.904 22.464 55.206 ;
     RECT  21.731 56.232 22.464 57.402 ;
     RECT  21.731 58.356 22.464 59.256 ;
     RECT  21.695 60.282 22.464 60.984 ;
     RECT  22.415 62.208 22.464 64.152 ;
     RECT  22.464 21.942 23.351 64.152 ;
     RECT  22.415 64.908 23.747 84.249 ;
     RECT  18.751 0.036 23.899 0.054 ;
     RECT  23.899 0.036 24.511 0.162 ;
     RECT  24.511 0.036 24.539 0.198 ;
     RECT  21.983 1.422 24.539 20.952 ;
     RECT  24.539 0.144 24.935 0.198 ;
     RECT  24.935 0.144 25.511 0.162 ;
     RECT  24.539 1.422 26.239 20.916 ;
     RECT  26.239 1.152 26.663 20.916 ;
     RECT  26.663 1.422 28.175 20.916 ;
     RECT  28.175 1.422 28.903 20.844 ;
     RECT  28.903 1.152 29.039 20.844 ;
     RECT  29.039 1.422 30.559 20.844 ;
     RECT  30.559 0.846 31.091 20.844 ;
     RECT  31.091 0.846 31.243 20.259 ;
     RECT  31.243 0.216 31.351 20.259 ;
     RECT  31.351 0.144 31.703 20.259 ;
     RECT  31.703 0.216 31.811 20.259 ;
     RECT  31.811 0.846 32.711 20.259 ;
     RECT  23.747 65.25 33.035 84.249 ;
     RECT  32.935 0.144 33.143 0.162 ;
     RECT  33.943 0.144 34.007 0.162 ;
     RECT  32.711 1.152 34.043 20.259 ;
     RECT  34.771 0.144 35.591 0.162 ;
     RECT  34.043 1.422 36.031 20.259 ;
     RECT  36.031 1.422 37.039 20.304 ;
     RECT  37.435 0.144 38.003 0.162 ;
     RECT  38.011 0.216 38.111 0.234 ;
     RECT  37.039 1.341 38.443 20.304 ;
     RECT  38.443 0.846 38.767 20.304 ;
     RECT  23.351 22.05 39.947 64.152 ;
     RECT  39.919 0.036 40.135 0.054 ;
     RECT  38.767 0.846 40.135 20.376 ;
     RECT  40.135 0.036 40.595 20.376 ;
     RECT  40.595 0.846 40.891 20.376 ;
     RECT  40.595 0.036 41.755 0.054 ;
     RECT  40.891 0.846 41.755 20.799 ;
     RECT  41.755 0.036 42.899 20.799 ;
     RECT  42.899 0.036 44.311 0.054 ;
     RECT  42.899 0.846 44.311 20.799 ;
     RECT  44.311 0.036 46.895 20.799 ;
     RECT  46.895 0.144 47.255 20.799 ;
     RECT  47.255 1.152 47.543 20.799 ;
     RECT  47.255 0.144 47.615 0.162 ;
     RECT  39.947 22.05 52.583 63.528 ;
     RECT  47.543 1.422 53.159 20.799 ;
     RECT  52.583 22.086 53.843 63.528 ;
     RECT  53.159 2.034 54.455 20.799 ;
     RECT  54.455 2.07 55.715 20.799 ;
     RECT  55.715 2.151 73.939 20.799 ;
     RECT  73.939 2.151 74.443 20.844 ;
     RECT  74.443 2.151 74.551 20.88 ;
     RECT  74.551 2.151 74.731 21.42 ;
     RECT  74.731 2.151 74.803 21.456 ;
     RECT  53.843 22.464 74.803 63.528 ;
     RECT  74.803 2.151 117.288 63.528 ;
     RECT  117.288 2.151 117.563 23.922 ;
     RECT  117.288 29.034 118.039 30.132 ;
     RECT  117.288 30.888 118.039 33.606 ;
     RECT  117.563 2.151 118.579 22.464 ;
     RECT  117.563 23.328 118.579 23.922 ;
     RECT  118.039 29.034 118.579 33.606 ;
     RECT  117.288 34.47 118.579 34.65 ;
     RECT  118.579 29.034 118.759 34.65 ;
     RECT  117.288 25.326 118.939 27.864 ;
     RECT  118.759 28.926 118.939 34.65 ;
     RECT  118.939 24.786 119.047 27.864 ;
     RECT  118.939 28.836 119.047 34.65 ;
     RECT  119.047 24.786 119.083 34.65 ;
     RECT  117.288 35.55 119.083 63 ;
     RECT  118.579 2.151 119.155 23.922 ;
     RECT  119.083 24.786 119.155 63 ;
     RECT  119.155 2.151 119.34 63 ;
     RECT  33.035 65.601 119.34 84.249 ;
     RECT  119.34 2.151 140.4 84.249 ;
     RECT  140.4 44.226 140.819 44.244 ;
    LAYER M3 ;
     RECT  24.516 0.031 24.534 0.108 ;
     RECT  39.924 0.031 39.942 0.108 ;
     RECT  46.872 0.031 46.89 0.108 ;
     RECT  24.48 0.108 42.786 0.139 ;
     RECT  46.512 0.108 47.538 0.139 ;
     RECT  23.904 0.139 42.894 0.187 ;
     RECT  43.704 0.139 43.722 0.187 ;
     RECT  51.48 0.108 53.658 0.187 ;
     RECT  46.512 0.139 47.61 0.283 ;
     RECT  23.904 0.187 43.722 0.331 ;
     RECT  23.868 0.331 43.722 0.571 ;
     RECT  45.972 0.283 47.61 0.877 ;
     RECT  23.868 0.571 44.334 0.955 ;
     RECT  18.756 0.031 18.774 1.111 ;
     RECT  19.944 0.187 19.962 1.111 ;
     RECT  18.756 1.111 19.962 1.139 ;
     RECT  22.932 1.099 22.95 1.147 ;
     RECT  23.868 0.955 44.442 1.147 ;
     RECT  45.756 0.877 47.61 1.147 ;
     RECT  50.76 0.187 53.658 1.147 ;
     RECT  50.76 1.147 53.694 1.195 ;
     RECT  21.78 0.859 21.798 1.387 ;
     RECT  22.932 1.147 44.514 1.387 ;
     RECT  21.78 1.387 44.514 1.489 ;
     RECT  45.576 1.147 47.61 1.489 ;
     RECT  21.78 1.489 47.61 1.723 ;
     RECT  50.76 1.195 54.378 1.723 ;
     RECT  20.052 1.417 20.25 1.831 ;
     RECT  21.78 1.723 47.718 1.876 ;
     RECT  48.78 1.831 48.798 1.876 ;
     RECT  18.756 1.139 19.278 1.957 ;
     RECT  50.76 1.723 54.702 1.957 ;
     RECT  20.052 1.831 20.826 1.993 ;
     RECT  21.78 1.876 48.798 1.993 ;
     RECT  18.54 1.957 19.278 2.029 ;
     RECT  20.052 1.993 48.798 2.029 ;
     RECT  18 2.029 19.278 2.101 ;
     RECT  20.052 2.029 49.014 2.101 ;
     RECT  55.692 2.065 55.71 2.143 ;
     RECT  50.724 1.957 54.702 2.191 ;
     RECT  17.676 2.101 49.554 2.263 ;
     RECT  50.724 2.191 54.774 2.263 ;
     RECT  55.692 2.143 56.505 2.263 ;
     RECT  2.415 2.143 2.505 2.413 ;
     RECT  7.815 2.143 7.905 2.413 ;
     RECT  13.215 2.143 13.305 2.413 ;
     RECT  17.676 2.263 56.505 2.413 ;
     RECT  61.815 2.143 61.905 2.413 ;
     RECT  67.215 2.143 67.305 2.413 ;
     RECT  72.615 2.143 72.705 2.413 ;
     RECT  78.015 2.143 78.105 2.413 ;
     RECT  83.415 2.143 83.505 2.413 ;
     RECT  88.815 2.143 88.905 2.413 ;
     RECT  94.215 2.143 94.305 2.413 ;
     RECT  99.615 2.143 99.705 2.413 ;
     RECT  105.015 2.143 105.105 2.413 ;
     RECT  110.415 2.143 110.505 2.413 ;
     RECT  115.815 2.143 115.905 2.413 ;
     RECT  121.215 2.143 121.305 2.413 ;
     RECT  126.615 2.143 126.705 2.413 ;
     RECT  132.015 2.143 132.105 2.413 ;
     RECT  137.415 2.143 137.505 2.413 ;
     RECT  17.676 2.413 56.697 2.497 ;
     RECT  17.568 2.497 56.697 2.795 ;
     RECT  17.568 2.795 38.79 2.911 ;
     RECT  58.176 2.371 58.194 3.605 ;
     RECT  17.532 2.911 38.79 3.811 ;
     RECT  17.532 3.811 38.826 3.991 ;
     RECT  39.6 2.795 56.697 3.991 ;
     RECT  17.316 3.991 38.826 4.081 ;
     RECT  39.6 3.991 57.294 4.081 ;
     RECT  17.316 4.081 58.086 4.225 ;
     RECT  58.896 3.721 58.914 4.261 ;
     RECT  58.896 4.261 59.382 4.415 ;
     RECT  17.208 4.225 58.086 4.459 ;
     RECT  17.064 4.459 58.086 4.495 ;
     RECT  17.064 4.495 58.122 4.531 ;
     RECT  58.896 4.415 59.274 4.531 ;
     RECT  61.815 2.413 62.097 4.531 ;
     RECT  61.524 4.531 62.097 4.765 ;
     RECT  61.416 4.765 62.097 4.801 ;
     RECT  17.064 4.531 59.274 4.991 ;
     RECT  60.444 4.801 60.462 5.071 ;
     RECT  60.228 5.071 60.462 5.083 ;
     RECT  61.416 4.801 62.406 5.083 ;
     RECT  17.1 4.991 59.274 5.099 ;
     RECT  60.228 5.083 62.406 5.117 ;
     RECT  17.136 5.099 59.274 5.179 ;
     RECT  17.136 5.179 59.454 5.225 ;
     RECT  43.164 5.225 59.454 5.431 ;
     RECT  60.228 5.117 60.894 5.431 ;
     RECT  17.136 5.225 42.426 5.495 ;
     RECT  76.068 5.431 76.086 5.701 ;
     RECT  76.896 5.611 76.914 5.701 ;
     RECT  43.164 5.431 60.894 5.729 ;
     RECT  58.5 5.729 60.894 6.043 ;
     RECT  61.632 5.117 62.406 6.043 ;
     RECT  43.164 5.729 57.726 6.107 ;
     RECT  58.5 6.043 62.406 6.143 ;
     RECT  58.5 6.143 59.814 6.269 ;
     RECT  17.208 5.495 42.426 6.277 ;
     RECT  43.164 6.107 57.69 6.277 ;
     RECT  58.5 6.269 59.454 6.341 ;
     RECT  74.628 6.241 74.646 6.547 ;
     RECT  58.5 6.341 59.418 6.907 ;
     RECT  60.66 6.143 62.406 6.961 ;
     RECT  17.208 6.277 57.69 7.079 ;
     RECT  60.66 6.961 62.766 7.087 ;
     RECT  72.615 2.413 72.897 7.087 ;
     RECT  17.208 7.079 56.754 7.115 ;
     RECT  58.464 6.907 59.418 7.115 ;
     RECT  74.628 6.547 75.078 7.123 ;
     RECT  17.208 7.115 55.458 7.151 ;
     RECT  17.208 7.151 55.386 7.195 ;
     RECT  58.572 7.115 59.418 7.231 ;
     RECT  60.624 7.087 62.766 7.231 ;
     RECT  56.196 7.115 56.754 7.259 ;
     RECT  58.572 7.231 62.838 7.259 ;
     RECT  58.68 7.259 62.838 7.349 ;
     RECT  58.752 7.349 59.922 7.421 ;
     RECT  60.66 7.349 62.766 7.421 ;
     RECT  57.672 7.079 57.69 7.493 ;
     RECT  56.304 7.259 56.754 7.619 ;
     RECT  58.932 7.421 59.922 7.691 ;
     RECT  61.164 7.421 62.766 7.727 ;
     RECT  61.164 7.727 62.406 7.763 ;
     RECT  74.628 7.123 75.258 7.861 ;
     RECT  16.272 7.159 16.29 7.933 ;
     RECT  17.028 7.195 55.386 7.933 ;
     RECT  16.272 7.933 55.386 8.041 ;
     RECT  56.304 7.619 56.697 8.041 ;
     RECT  58.932 7.691 59.886 8.267 ;
     RECT  72.396 7.087 72.897 8.275 ;
     RECT  16.272 8.041 56.697 8.465 ;
     RECT  61.164 7.763 62.097 8.581 ;
     RECT  58.932 8.267 59.418 8.609 ;
     RECT  60.66 8.581 62.097 8.683 ;
     RECT  60.516 8.683 62.097 8.735 ;
     RECT  14.904 8.239 14.922 8.815 ;
     RECT  58.932 8.609 59.346 9.121 ;
     RECT  74.304 7.861 75.258 9.211 ;
     RECT  58.68 9.121 59.346 9.239 ;
     RECT  74.016 9.211 75.258 9.239 ;
     RECT  16.272 8.465 55.314 9.275 ;
     RECT  16.272 9.275 55.062 9.545 ;
     RECT  16.272 9.545 44.154 9.581 ;
     RECT  13.215 2.413 13.497 9.589 ;
     RECT  45 9.545 55.062 9.815 ;
     RECT  16.272 9.581 43.902 9.869 ;
     RECT  76.068 5.701 76.914 10.021 ;
     RECT  78.015 2.413 78.297 10.021 ;
     RECT  16.272 9.869 41.886 10.049 ;
     RECT  42.66 9.869 43.902 10.085 ;
     RECT  42.768 10.085 43.902 10.121 ;
     RECT  13.215 9.589 13.77 10.129 ;
     RECT  71.712 8.275 72.897 10.129 ;
     RECT  12.096 7.231 12.114 10.165 ;
     RECT  13.215 10.129 14.166 10.165 ;
     RECT  16.272 10.049 30.798 10.193 ;
     RECT  43.596 10.121 43.902 10.229 ;
     RECT  74.016 9.239 75.078 10.327 ;
     RECT  76.068 10.021 78.297 10.327 ;
     RECT  12.096 10.165 14.166 10.363 ;
     RECT  14.904 8.815 15.354 10.363 ;
     RECT  45.216 9.815 55.062 10.363 ;
     RECT  71.712 10.129 73.17 10.471 ;
     RECT  45.216 10.363 55.134 10.661 ;
     RECT  42.768 10.121 42.786 10.697 ;
     RECT  45.216 10.661 55.062 10.697 ;
     RECT  71.712 10.471 73.242 10.741 ;
     RECT  58.932 9.239 59.346 10.895 ;
     RECT  71.712 10.741 73.278 10.903 ;
     RECT  74.016 10.327 78.297 10.903 ;
     RECT  31.608 10.049 41.886 11.011 ;
     RECT  71.712 10.903 78.297 11.128 ;
     RECT  71.712 11.128 78.678 11.165 ;
     RECT  79.452 11.128 79.47 11.165 ;
     RECT  12.096 10.363 15.354 11.209 ;
     RECT  121.215 2.413 121.497 11.281 ;
     RECT  70.704 11.209 70.722 11.309 ;
     RECT  88.815 2.413 89.097 11.371 ;
     RECT  99.615 2.413 99.897 11.371 ;
     RECT  110.415 2.413 110.697 11.371 ;
     RECT  120.6 11.281 121.497 11.371 ;
     RECT  114.588 11.227 114.606 11.405 ;
     RECT  88.704 11.371 89.097 11.435 ;
     RECT  99.504 11.371 99.897 11.435 ;
     RECT  110.304 11.371 110.697 11.435 ;
     RECT  12.06 11.209 15.354 11.749 ;
     RECT  45.216 10.697 54.558 11.849 ;
     RECT  70.74 11.749 70.794 11.984 ;
     RECT  71.712 11.165 78.642 12.091 ;
     RECT  114.588 12.187 114.606 12.317 ;
     RECT  115.815 2.413 116.097 12.361 ;
     RECT  115.815 12.361 116.334 12.487 ;
     RECT  43.596 10.229 43.614 12.523 ;
     RECT  70.74 11.984 70.758 12.551 ;
     RECT  31.608 11.011 42.39 12.559 ;
     RECT  71.64 12.091 78.642 12.559 ;
     RECT  45.54 11.849 54.558 12.587 ;
     RECT  45.54 12.587 50.058 12.659 ;
     RECT  31.392 12.559 42.39 12.721 ;
     RECT  70.704 12.631 70.722 12.749 ;
     RECT  118.836 10.705 118.854 12.793 ;
     RECT  43.596 12.523 44.154 12.929 ;
     RECT  71.532 12.559 78.642 12.929 ;
     RECT  16.272 10.193 30.582 12.991 ;
     RECT  31.356 12.721 42.39 12.991 ;
     RECT  56.415 8.465 56.697 12.991 ;
     RECT  67.215 2.413 67.497 12.991 ;
     RECT  45.615 12.659 50.058 13.019 ;
     RECT  44.136 12.929 44.154 13.037 ;
     RECT  56.304 12.991 56.697 13.037 ;
     RECT  67.104 12.991 67.497 13.037 ;
     RECT  72 12.929 78.642 13.055 ;
     RECT  16.272 12.991 42.39 13.063 ;
     RECT  72.216 13.055 78.642 13.091 ;
     RECT  118.008 11.677 118.026 13.133 ;
     RECT  45.615 13.019 47.322 13.199 ;
     RECT  72.396 13.091 78.642 13.261 ;
     RECT  115.815 12.487 116.874 13.333 ;
     RECT  72.396 13.261 78.678 13.361 ;
     RECT  51.015 12.587 54.558 13.397 ;
     RECT  51.015 13.397 54.234 13.433 ;
     RECT  118.836 12.793 119.538 13.441 ;
     RECT  72.396 13.361 78.642 13.469 ;
     RECT  45.615 13.199 46.854 13.559 ;
     RECT  48.492 13.019 50.058 13.559 ;
     RECT  51.015 13.433 52.65 13.603 ;
     RECT  46.692 13.559 46.854 13.667 ;
     RECT  70.704 13.531 70.722 13.667 ;
     RECT  50.616 13.603 52.65 13.709 ;
     RECT  48.492 13.559 49.878 13.829 ;
     RECT  53.388 13.433 54.234 13.973 ;
     RECT  50.724 13.709 52.65 14.099 ;
     RECT  115.815 13.333 117.198 14.107 ;
     RECT  118.26 13.441 119.538 14.107 ;
     RECT  72.396 13.469 78.354 14.144 ;
     RECT  50.76 14.099 52.65 14.237 ;
     RECT  72.396 14.144 72.99 14.243 ;
     RECT  73.728 14.144 78.354 14.341 ;
     RECT  50.76 14.237 52.578 14.369 ;
     RECT  115.815 14.107 119.538 14.449 ;
     RECT  73.728 14.341 78.75 14.477 ;
     RECT  49.356 13.829 49.878 14.513 ;
     RECT  115.74 14.449 119.538 14.521 ;
     RECT  120.564 11.371 121.497 14.521 ;
     RECT  106.02 13.711 106.038 14.549 ;
     RECT  46.692 13.667 46.782 14.639 ;
     RECT  53.604 13.973 54.234 14.639 ;
     RECT  72.615 14.243 72.99 14.639 ;
     RECT  114.588 14.611 114.606 14.647 ;
     RECT  16.272 13.063 42.57 14.683 ;
     RECT  105.015 2.413 105.297 14.683 ;
     RECT  51.015 14.369 52.578 14.711 ;
     RECT  73.728 14.477 78.678 14.711 ;
     RECT  114.588 14.647 114.75 14.747 ;
     RECT  115.74 14.521 121.497 14.791 ;
     RECT  51.015 14.711 51.678 14.819 ;
     RECT  114.588 14.747 114.678 14.819 ;
     RECT  115.704 14.791 121.497 14.881 ;
     RECT  58.932 10.895 58.95 14.917 ;
     RECT  59.76 11.011 59.778 14.917 ;
     RECT  61.164 8.735 62.097 14.923 ;
     RECT  16.272 14.683 42.642 14.953 ;
     RECT  105.015 14.683 105.462 14.981 ;
     RECT  58.716 14.917 59.778 14.989 ;
     RECT  60.984 14.923 62.097 14.989 ;
     RECT  58.716 14.989 62.097 15.089 ;
     RECT  110.415 11.435 110.697 15.187 ;
     RECT  58.716 15.089 59.814 15.215 ;
     RECT  16.272 14.953 42.858 15.251 ;
     RECT  59.724 15.215 59.814 15.359 ;
     RECT  60.588 15.089 62.097 15.359 ;
     RECT  16.272 15.251 42.822 15.485 ;
     RECT  115.56 14.881 121.497 15.565 ;
     RECT  59.724 15.359 59.742 15.755 ;
     RECT  46.692 14.639 46.71 15.899 ;
     RECT  61.815 15.359 62.097 15.961 ;
     RECT  115.38 15.565 121.497 15.989 ;
     RECT  31.968 15.485 42.822 16.097 ;
     RECT  60.588 15.359 60.606 16.133 ;
     RECT  16.272 15.485 31.158 16.219 ;
     RECT  31.968 16.097 42.39 16.219 ;
     RECT  16.272 16.219 42.39 16.259 ;
     RECT  70.74 16.141 70.758 16.303 ;
     RECT  16.272 16.259 31.158 16.331 ;
     RECT  70.74 16.303 70.794 16.411 ;
     RECT  70.704 16.411 70.794 16.439 ;
     RECT  61.815 15.961 62.154 16.673 ;
     RECT  12.06 11.749 15.39 16.681 ;
     RECT  16.272 16.331 30.942 16.681 ;
     RECT  12.06 16.681 30.942 16.799 ;
     RECT  70.704 16.439 70.758 16.799 ;
     RECT  70.74 16.799 70.758 16.835 ;
     RECT  73.728 14.711 78.297 16.835 ;
     RECT  53.604 14.639 53.838 16.871 ;
     RECT  31.932 16.259 42.39 17.077 ;
     RECT  31.896 17.077 42.39 17.083 ;
     RECT  115.452 15.989 121.497 17.221 ;
     RECT  56.415 13.037 56.697 17.311 ;
     RECT  67.215 13.037 67.497 17.311 ;
     RECT  88.815 11.435 89.097 17.311 ;
     RECT  99.615 11.435 99.897 17.311 ;
     RECT  110.415 15.187 111.186 17.311 ;
     RECT  56.304 17.311 56.697 17.357 ;
     RECT  67.104 17.311 67.497 17.357 ;
     RECT  88.704 17.311 89.097 17.357 ;
     RECT  99.504 17.311 99.897 17.357 ;
     RECT  110.304 17.311 111.186 17.357 ;
     RECT  110.415 17.357 111.186 17.405 ;
     RECT  43.884 16.879 43.902 17.419 ;
     RECT  46.728 17.323 46.746 17.453 ;
     RECT  43.272 17.419 43.902 17.456 ;
     RECT  115.38 17.221 121.497 17.609 ;
     RECT  31.896 17.083 42.498 17.681 ;
     RECT  36.9 17.681 42.498 17.689 ;
     RECT  115.452 17.609 121.497 17.693 ;
     RECT  12.06 16.799 30.87 17.725 ;
     RECT  31.896 17.681 36.09 17.915 ;
     RECT  75.78 16.835 78.297 17.923 ;
     RECT  114.588 16.879 114.606 17.959 ;
     RECT  36.9 17.689 42.786 18.023 ;
     RECT  12.06 17.725 30.978 18.031 ;
     RECT  31.896 17.915 32.418 18.031 ;
     RECT  36.9 18.023 42.678 18.185 ;
     RECT  36.9 18.185 41.634 18.221 ;
     RECT  12.06 18.031 32.418 18.419 ;
     RECT  75.78 17.923 78.75 18.419 ;
     RECT  42.372 18.185 42.678 18.491 ;
     RECT  114.588 17.959 114.678 18.499 ;
     RECT  31.356 18.419 32.418 18.667 ;
     RECT  33.156 17.915 36.09 18.667 ;
     RECT  31.356 18.667 36.09 18.725 ;
     RECT  75.78 18.419 78.297 18.761 ;
     RECT  31.932 18.725 36.09 18.797 ;
     RECT  114.588 18.499 114.714 18.967 ;
     RECT  115.56 17.693 121.497 18.967 ;
     RECT  43.884 17.456 43.902 19.003 ;
     RECT  36.9 18.221 41.526 19.111 ;
     RECT  42.372 18.491 42.39 19.111 ;
     RECT  32.04 18.797 36.09 19.201 ;
     RECT  36.864 19.111 42.39 19.201 ;
     RECT  43.596 19.003 43.902 19.201 ;
     RECT  32.04 19.201 42.39 19.229 ;
     RECT  43.596 19.201 44.298 19.229 ;
     RECT  112.284 17.491 112.302 19.229 ;
     RECT  43.812 19.229 44.298 19.277 ;
     RECT  49.356 14.513 49.374 19.309 ;
     RECT  106.02 18.463 106.038 19.409 ;
     RECT  45.615 13.559 45.897 19.471 ;
     RECT  56.415 17.357 56.697 19.471 ;
     RECT  67.215 17.357 67.497 19.471 ;
     RECT  88.815 17.357 89.097 19.471 ;
     RECT  99.615 17.357 99.897 19.471 ;
     RECT  110.415 17.405 110.697 19.471 ;
     RECT  32.04 19.229 41.526 19.499 ;
     RECT  43.812 19.277 43.938 19.571 ;
     RECT  32.148 19.499 41.49 19.607 ;
     RECT  12.06 18.419 30.546 19.615 ;
     RECT  43.812 19.571 43.83 19.616 ;
     RECT  72.615 14.639 72.954 19.661 ;
     RECT  49.356 19.309 49.518 19.679 ;
     RECT  49.5 19.679 49.518 19.741 ;
     RECT  12.06 19.615 30.798 19.769 ;
     RECT  36.9 19.607 41.49 19.769 ;
     RECT  49.5 19.741 49.59 19.769 ;
     RECT  12.06 19.769 29.697 19.841 ;
     RECT  36.9 19.769 37.494 19.841 ;
     RECT  32.148 19.607 36.054 19.853 ;
     RECT  49.572 19.769 49.59 19.853 ;
     RECT  36.9 19.841 37.386 19.877 ;
     RECT  30.528 19.769 30.798 19.921 ;
     RECT  12.06 19.841 28.458 19.949 ;
     RECT  12.06 19.949 26.874 19.997 ;
     RECT  34.092 19.853 36.054 19.997 ;
     RECT  51.015 14.819 51.297 19.997 ;
     RECT  61.815 16.673 62.097 19.997 ;
     RECT  72.615 19.661 72.897 19.997 ;
     RECT  83.415 2.413 83.697 19.997 ;
     RECT  94.215 2.413 94.497 19.997 ;
     RECT  105.015 14.981 105.297 19.997 ;
     RECT  38.304 19.769 39.366 20.039 ;
     RECT  40.104 19.769 41.49 20.039 ;
     RECT  114.588 18.967 121.497 20.039 ;
     RECT  110.304 19.471 110.697 20.045 ;
     RECT  32.148 19.853 33.246 20.048 ;
     RECT  45.504 19.471 45.897 20.048 ;
     RECT  56.304 19.471 56.697 20.048 ;
     RECT  67.104 19.471 67.497 20.048 ;
     RECT  88.704 19.471 89.097 20.048 ;
     RECT  99.504 19.471 99.897 20.048 ;
     RECT  33.228 20.048 33.246 20.075 ;
     RECT  40.407 20.039 41.49 20.093 ;
     RECT  30.528 19.921 31.086 20.111 ;
     RECT  73.728 16.835 74.97 20.119 ;
     RECT  24.192 19.997 26.874 20.147 ;
     RECT  36.9 19.877 36.918 20.147 ;
     RECT  38.304 20.039 39.258 20.147 ;
     RECT  24.192 20.147 25.11 20.189 ;
     RECT  73.728 20.119 75.474 20.189 ;
     RECT  38.304 20.147 39.222 20.219 ;
     RECT  34.092 19.997 34.11 20.237 ;
     RECT  24.207 20.189 25.11 20.267 ;
     RECT  29.196 19.841 29.697 20.267 ;
     RECT  35.007 19.997 36.054 20.267 ;
     RECT  40.407 20.093 41.13 20.267 ;
     RECT  45.807 20.048 45.897 20.267 ;
     RECT  51.207 19.997 51.297 20.267 ;
     RECT  56.607 20.048 56.697 20.267 ;
     RECT  62.007 19.997 62.097 20.267 ;
     RECT  67.407 20.048 67.497 20.267 ;
     RECT  72.807 19.997 72.897 20.267 ;
     RECT  76.5 18.761 78.297 20.267 ;
     RECT  83.607 19.997 83.697 20.267 ;
     RECT  89.007 20.048 89.097 20.267 ;
     RECT  94.407 19.997 94.497 20.267 ;
     RECT  99.807 20.048 99.897 20.267 ;
     RECT  105.207 19.997 105.297 20.267 ;
     RECT  110.607 20.045 110.697 20.267 ;
     RECT  115.56 20.039 121.497 20.267 ;
     RECT  35.424 20.267 36.054 20.309 ;
     RECT  38.448 20.219 39.222 20.309 ;
     RECT  42.372 19.229 42.39 20.309 ;
     RECT  27.684 19.949 28.386 20.333 ;
     RECT  73.728 20.189 74.97 20.345 ;
     RECT  38.448 20.309 38.79 20.381 ;
     RECT  40.896 20.267 41.13 20.381 ;
     RECT  73.764 20.345 74.97 20.381 ;
     RECT  76.5 20.267 77.814 20.381 ;
     RECT  114.588 20.039 114.606 20.381 ;
     RECT  25.992 20.147 26.874 20.417 ;
     RECT  40.896 20.381 40.914 20.804 ;
     RECT  35.424 20.309 35.442 20.813 ;
     RECT  31.068 20.111 31.086 20.849 ;
     RECT  73.944 20.381 74.97 20.849 ;
     RECT  26.244 20.417 26.874 20.861 ;
     RECT  74.448 20.849 74.97 20.885 ;
     RECT  27.864 20.333 28.386 20.909 ;
     RECT  27.864 20.909 28.17 20.921 ;
     RECT  76.5 20.381 77.598 20.921 ;
     RECT  24.516 20.267 25.11 20.957 ;
     RECT  116.424 20.267 121.497 21.299 ;
     RECT  74.556 20.885 74.97 21.425 ;
     RECT  29.196 20.267 29.394 21.437 ;
     RECT  74.736 21.425 74.97 21.461 ;
     RECT  27.864 20.921 27.882 21.485 ;
     RECT  76.608 20.921 77.598 21.497 ;
     RECT  76.788 21.497 77.598 21.533 ;
     RECT  76.824 21.533 77.598 21.659 ;
     RECT  24.696 20.957 24.714 21.677 ;
     RECT  115.56 20.267 115.578 21.695 ;
     RECT  12.06 19.997 23.346 22.464 ;
     RECT  26.244 20.861 26.262 22.464 ;
     RECT  29.376 21.437 29.394 22.464 ;
     RECT  32.148 20.048 32.166 22.464 ;
     RECT  38.448 20.381 38.466 22.464 ;
     RECT  52.56 14.711 52.578 22.464 ;
     RECT  53.82 16.871 53.838 22.464 ;
     RECT  74.808 21.461 74.97 22.464 ;
     RECT  76.824 21.659 77.022 22.464 ;
     RECT  116.46 21.299 121.497 22.464 ;
     RECT  12.06 22.464 121.497 23.899 ;
     RECT  11.7 23.899 121.497 23.971 ;
     RECT  11.304 23.971 121.497 24.781 ;
     RECT  11.124 24.781 121.497 26.293 ;
     RECT  11.088 26.293 121.497 26.401 ;
     RECT  10.836 26.401 121.497 27.167 ;
     RECT  9.936 27.751 9.954 27.913 ;
     RECT  10.872 27.167 121.497 27.913 ;
     RECT  9.936 27.913 121.497 29.021 ;
     RECT  11.556 29.021 121.497 29.839 ;
     RECT  11.52 29.839 121.497 30.577 ;
     RECT  11.484 30.577 121.497 30.941 ;
     RECT  11.484 30.941 120.078 31.261 ;
     RECT  11.412 31.261 120.078 31.517 ;
     RECT  118.584 31.517 120.078 31.915 ;
     RECT  11.412 31.517 117.738 32.197 ;
     RECT  11.304 32.197 117.738 32.341 ;
     RECT  118.584 31.915 120.15 32.341 ;
     RECT  11.304 32.341 120.15 32.459 ;
     RECT  11.304 32.459 120.078 32.603 ;
     RECT  11.304 32.603 119.97 32.669 ;
     RECT  11.304 32.669 117.954 32.881 ;
     RECT  11.088 32.881 117.954 33.115 ;
     RECT  9.936 29.021 9.954 33.421 ;
     RECT  10.98 33.115 117.954 33.421 ;
     RECT  9.936 33.421 10.17 33.583 ;
     RECT  10.98 33.421 118.062 33.583 ;
     RECT  121.032 30.941 121.497 33.809 ;
     RECT  9.936 33.583 118.062 33.961 ;
     RECT  118.872 32.669 119.97 33.961 ;
     RECT  9.936 33.961 119.97 34.079 ;
     RECT  9.936 34.079 119.826 34.301 ;
     RECT  119.052 34.301 119.826 34.493 ;
     RECT  119.124 34.493 119.826 34.781 ;
     RECT  119.124 34.781 119.754 35.311 ;
     RECT  9.936 34.301 117.99 35.323 ;
     RECT  119.088 35.311 119.754 35.357 ;
     RECT  119.736 35.357 119.754 35.465 ;
     RECT  9.36 35.323 117.99 35.699 ;
     RECT  9.936 35.699 117.99 35.707 ;
     RECT  119.844 35.515 119.862 35.707 ;
     RECT  119.844 35.707 119.934 35.744 ;
     RECT  9.036 35.743 9.054 35.789 ;
     RECT  9.936 35.707 118.602 35.933 ;
     RECT  119.844 35.744 119.862 36.113 ;
     RECT  9.936 35.933 117.99 37.021 ;
     RECT  9.936 37.021 118.602 37.147 ;
     RECT  9.936 37.147 119.106 37.277 ;
     RECT  118.584 37.277 119.106 37.327 ;
     RECT  118.584 37.327 119.646 37.435 ;
     RECT  118.584 37.435 119.898 37.589 ;
     RECT  118.584 37.589 119.646 37.625 ;
     RECT  0.36 37.903 0.378 37.975 ;
     RECT  9.936 37.277 117.414 38.005 ;
     RECT  118.584 37.625 119.106 38.005 ;
     RECT  2.415 2.413 2.697 38.011 ;
     RECT  9.936 38.005 119.106 38.045 ;
     RECT  2.415 38.011 2.754 38.137 ;
     RECT  3.6 38.101 3.618 38.137 ;
     RECT  118.584 38.045 119.106 38.333 ;
     RECT  2.415 38.137 3.618 38.515 ;
     RECT  5.724 38.011 5.742 38.551 ;
     RECT  7.815 2.413 8.097 38.677 ;
     RECT  5.724 38.551 6.426 38.713 ;
     RECT  7.272 38.677 8.097 38.713 ;
     RECT  118.584 38.333 118.602 38.813 ;
     RECT  1.728 38.515 3.618 39.019 ;
     RECT  0.216 37.975 0.378 39.053 ;
     RECT  1.728 39.019 4.194 39.091 ;
     RECT  1.728 39.091 4.626 39.163 ;
     RECT  119.052 39.055 119.07 39.181 ;
     RECT  119.988 39.055 120.006 39.181 ;
     RECT  1.728 39.163 4.878 39.217 ;
     RECT  5.652 38.713 8.097 39.217 ;
     RECT  119.052 39.181 120.006 39.281 ;
     RECT  9.936 38.045 117.414 39.289 ;
     RECT  119.052 39.281 119.106 39.485 ;
     RECT  120.06 39.487 120.078 39.587 ;
     RECT  8.928 39.559 8.946 39.595 ;
     RECT  0.216 39.053 0.342 39.629 ;
     RECT  8.82 39.595 8.946 39.631 ;
     RECT  9.9 39.289 117.414 39.631 ;
     RECT  0.216 39.629 0.306 39.917 ;
     RECT  0.216 39.917 0.234 40.064 ;
     RECT  1.728 39.217 8.097 40.171 ;
     RECT  8.82 39.631 117.414 40.171 ;
     RECT  119.88 40.063 119.898 40.199 ;
     RECT  119.088 39.485 119.106 40.261 ;
     RECT  1.728 40.171 117.414 40.349 ;
     RECT  119.952 40.369 119.97 40.469 ;
     RECT  119.052 40.261 119.106 40.541 ;
     RECT  119.052 40.541 119.07 40.733 ;
     RECT  119.988 40.801 120.006 41.009 ;
     RECT  0.216 40.891 0.234 41.035 ;
     RECT  1.152 40.747 1.17 41.179 ;
     RECT  1.152 41.179 1.422 41.611 ;
     RECT  119.124 41.563 119.142 41.647 ;
     RECT  0.216 41.035 0.27 41.755 ;
     RECT  1.152 41.611 1.566 41.755 ;
     RECT  2.304 40.349 117.414 41.881 ;
     RECT  119.124 41.647 119.862 41.981 ;
     RECT  2.304 41.881 117.45 42.077 ;
     RECT  0.216 41.755 1.566 42.215 ;
     RECT  0.54 42.215 1.566 42.323 ;
     RECT  119.124 41.981 119.754 42.601 ;
     RECT  2.304 42.077 117.414 42.755 ;
     RECT  119.088 42.601 119.754 42.755 ;
     RECT  119.088 42.755 119.106 42.941 ;
     RECT  2.415 42.755 117.414 42.961 ;
     RECT  1.152 42.323 1.566 43.025 ;
     RECT  1.548 43.025 1.566 43.097 ;
     RECT  2.415 42.961 117.45 43.259 ;
     RECT  0.036 43.195 0.234 43.325 ;
     RECT  4.428 43.259 117.45 43.501 ;
     RECT  2.415 43.259 2.754 43.529 ;
     RECT  4.428 43.501 117.486 43.529 ;
     RECT  8.82 43.529 9.306 43.565 ;
     RECT  119.628 43.501 119.646 43.681 ;
     RECT  8.928 43.565 9.306 43.709 ;
     RECT  10.116 43.529 117.486 43.709 ;
     RECT  119.628 43.681 120.15 43.835 ;
     RECT  119.628 43.835 119.754 43.843 ;
     RECT  10.116 43.709 117.414 43.871 ;
     RECT  4.428 43.529 8.097 44.069 ;
     RECT  0.036 43.325 0.054 44.299 ;
     RECT  139.464 44.221 139.482 44.311 ;
     RECT  140.796 44.221 140.814 44.333 ;
     RECT  138.96 44.311 139.482 44.339 ;
     RECT  138.96 44.339 138.978 44.383 ;
     RECT  138.528 44.383 138.978 44.411 ;
     RECT  0.036 44.299 0.234 44.429 ;
     RECT  138.528 44.411 138.546 44.429 ;
     RECT  119.052 43.843 119.754 44.573 ;
     RECT  119.556 44.573 119.754 45.031 ;
     RECT  119.556 45.031 120.114 45.149 ;
     RECT  118.584 44.959 118.71 45.329 ;
     RECT  118.584 45.329 118.638 45.527 ;
     RECT  10.584 43.871 117.414 45.769 ;
     RECT  119.7 45.149 119.79 46.301 ;
     RECT  118.584 45.527 118.602 46.345 ;
     RECT  10.584 45.769 117.45 46.397 ;
     RECT  119.7 46.301 119.754 46.459 ;
     RECT  118.584 46.345 118.674 46.615 ;
     RECT  119.628 46.459 119.754 46.615 ;
     RECT  10.584 46.397 117.414 47.183 ;
     RECT  118.584 46.615 119.754 47.281 ;
     RECT  12.168 47.183 117.414 47.345 ;
     RECT  12.672 47.345 117.414 47.381 ;
     RECT  118.584 47.281 119.826 47.453 ;
     RECT  12.672 47.381 14.274 47.615 ;
     RECT  12.744 47.615 14.274 47.651 ;
     RECT  12.996 47.651 14.274 47.723 ;
     RECT  118.584 47.453 119.754 48.125 ;
     RECT  15.264 47.381 117.414 48.163 ;
     RECT  5.472 44.069 8.097 48.191 ;
     RECT  119.736 48.125 119.754 48.541 ;
     RECT  4.428 44.069 4.554 48.767 ;
     RECT  13.104 47.723 14.274 48.839 ;
     RECT  118.584 48.125 118.602 48.901 ;
     RECT  119.736 48.541 119.97 48.901 ;
     RECT  118.584 48.901 120.006 48.929 ;
     RECT  119.988 48.929 120.006 49.001 ;
     RECT  9.288 43.709 9.306 49.379 ;
     RECT  4.428 48.767 4.518 49.469 ;
     RECT  13.215 48.839 14.274 49.621 ;
     RECT  15.228 48.163 117.414 49.621 ;
     RECT  118.584 48.929 119.106 49.661 ;
     RECT  120.168 49.621 120.186 49.775 ;
     RECT  5.472 48.191 6.21 49.919 ;
     RECT  7.092 48.191 8.097 49.963 ;
     RECT  118.584 49.661 118.71 49.964 ;
     RECT  7.092 49.963 9.126 50.009 ;
     RECT  9.108 50.009 9.126 50.045 ;
     RECT  6.012 49.919 6.21 50.459 ;
     RECT  119.52 50.587 119.538 50.629 ;
     RECT  10.584 47.183 11.43 50.657 ;
     RECT  119.52 50.629 119.97 50.791 ;
     RECT  10.584 50.657 11.25 50.819 ;
     RECT  119.52 50.791 120.186 50.855 ;
     RECT  119.844 50.855 120.186 50.891 ;
     RECT  118.62 49.964 118.674 50.923 ;
     RECT  6.192 50.459 6.21 50.999 ;
     RECT  13.215 49.621 117.414 51.089 ;
     RECT  118.584 50.923 118.71 51.097 ;
     RECT  118.584 51.097 118.746 51.233 ;
     RECT  119.844 50.891 120.078 51.269 ;
     RECT  7.092 50.009 8.097 51.359 ;
     RECT  0.036 44.429 0.054 51.395 ;
     RECT  7.56 51.359 8.097 51.503 ;
     RECT  120.06 51.269 120.078 51.503 ;
     RECT  2.415 43.529 2.697 51.511 ;
     RECT  15.012 51.089 117.414 51.601 ;
     RECT  118.62 51.233 118.638 52.043 ;
     RECT  119.952 52.051 119.97 52.141 ;
     RECT  4.5 49.469 4.518 52.205 ;
     RECT  15.012 51.601 117.45 52.349 ;
     RECT  13.215 51.089 14.202 52.363 ;
     RECT  15.012 52.349 117.414 52.363 ;
     RECT  119.772 52.141 119.97 52.411 ;
     RECT  10.584 50.819 11.178 52.555 ;
     RECT  10.584 52.555 11.322 52.591 ;
     RECT  119.592 52.411 119.97 52.681 ;
     RECT  10.584 52.591 11.43 52.717 ;
     RECT  119.592 52.681 120.006 52.817 ;
     RECT  10.584 52.717 11.898 52.861 ;
     RECT  13.215 52.363 117.414 52.861 ;
     RECT  119.592 52.817 119.97 52.951 ;
     RECT  9.468 52.861 9.486 52.981 ;
     RECT  10.404 52.861 11.898 52.981 ;
     RECT  9.036 52.981 9.486 53.021 ;
     RECT  13.176 52.861 117.414 53.059 ;
     RECT  7.815 51.503 8.097 53.083 ;
     RECT  9.288 53.021 9.486 53.095 ;
     RECT  10.404 52.981 12.042 53.095 ;
     RECT  9.288 53.095 12.042 53.131 ;
     RECT  13.104 53.059 117.414 53.131 ;
     RECT  6.588 53.083 6.606 53.329 ;
     RECT  7.668 53.083 8.097 53.329 ;
     RECT  9.288 53.131 12.222 53.329 ;
     RECT  12.96 53.131 117.414 53.329 ;
     RECT  6.552 53.329 8.097 53.365 ;
     RECT  9.288 53.329 117.414 53.429 ;
     RECT  119.448 52.951 119.97 53.429 ;
     RECT  6.552 53.365 8.55 53.491 ;
     RECT  118.584 52.987 118.602 53.491 ;
     RECT  9.288 53.429 12.006 53.519 ;
     RECT  6.408 53.491 8.55 53.563 ;
     RECT  119.952 53.429 119.97 53.591 ;
     RECT  9.288 53.519 11.898 53.789 ;
     RECT  6.048 53.563 8.55 53.833 ;
     RECT  9.288 53.789 11.862 53.833 ;
     RECT  4.284 53.869 4.302 53.941 ;
     RECT  118.584 53.491 119.106 53.969 ;
     RECT  4.176 53.941 4.77 54.067 ;
     RECT  6.048 53.833 11.862 54.173 ;
     RECT  119.052 53.969 119.106 54.373 ;
     RECT  6.372 54.173 11.862 54.607 ;
     RECT  12.78 53.429 117.414 54.607 ;
     RECT  6.372 54.607 117.414 54.701 ;
     RECT  4.176 54.067 5.022 54.751 ;
     RECT  4.032 54.751 5.058 54.985 ;
     RECT  119.052 54.373 119.826 54.985 ;
     RECT  119.052 54.985 120.294 55.037 ;
     RECT  119.052 55.037 119.862 55.219 ;
     RECT  119.016 55.219 119.862 55.517 ;
     RECT  6.372 54.701 12.15 55.795 ;
     RECT  12.888 54.701 117.414 55.795 ;
     RECT  118.62 55.651 118.746 55.831 ;
     RECT  3.528 54.985 5.202 56.065 ;
     RECT  119.592 55.517 119.862 56.093 ;
     RECT  3.528 56.065 5.238 56.299 ;
     RECT  6.372 55.795 117.414 56.399 ;
     RECT  118.584 55.831 118.746 56.461 ;
     RECT  119.592 56.093 119.754 56.461 ;
     RECT  3.528 56.299 5.526 56.641 ;
     RECT  6.372 56.399 11.718 56.641 ;
     RECT  3.528 56.641 11.718 56.767 ;
     RECT  118.584 56.461 119.754 56.795 ;
     RECT  3.456 56.767 11.718 56.911 ;
     RECT  118.62 56.795 119.754 57.001 ;
     RECT  118.62 57.001 120.006 57.137 ;
     RECT  2.376 51.511 2.697 57.145 ;
     RECT  3.42 56.911 11.718 57.145 ;
     RECT  12.456 56.399 117.414 57.145 ;
     RECT  118.62 57.137 119.79 57.209 ;
     RECT  118.62 57.209 119.754 57.407 ;
     RECT  2.376 57.145 117.45 57.485 ;
     RECT  3.456 57.485 117.45 57.533 ;
     RECT  118.62 57.407 119.646 57.629 ;
     RECT  118.62 57.629 119.106 57.847 ;
     RECT  118.584 57.847 119.106 58.493 ;
     RECT  3.456 57.533 117.378 58.531 ;
     RECT  119.736 58.657 119.754 59.227 ;
     RECT  118.584 58.493 118.674 59.567 ;
     RECT  2.376 57.485 2.697 59.611 ;
     RECT  118.62 59.567 118.674 59.611 ;
     RECT  119.556 59.227 119.754 59.611 ;
     RECT  2.34 59.611 2.697 59.809 ;
     RECT  3.456 58.531 117.414 59.809 ;
     RECT  2.34 59.809 117.414 59.837 ;
     RECT  118.62 59.611 119.754 59.837 ;
     RECT  118.62 59.837 119.682 60.071 ;
     RECT  119.628 60.071 119.682 60.305 ;
     RECT  118.62 60.071 118.674 60.313 ;
     RECT  118.584 60.313 118.674 60.917 ;
     RECT  118.584 60.917 118.602 60.989 ;
     RECT  119.628 60.305 119.646 61.231 ;
     RECT  119.628 61.231 119.934 61.357 ;
     RECT  2.34 59.837 3.402 61.465 ;
     RECT  4.356 59.837 117.414 61.465 ;
     RECT  119.628 61.357 120.078 61.493 ;
     RECT  2.34 61.465 117.414 61.915 ;
     RECT  2.34 61.915 118.026 61.961 ;
     RECT  119.628 61.493 119.754 62.011 ;
     RECT  119.16 62.011 119.754 62.303 ;
     RECT  119.736 62.303 119.754 62.699 ;
     RECT  20.772 61.961 118.026 63.005 ;
     RECT  20.772 63.005 117.288 63.528 ;
     RECT  2.34 61.961 19.962 63.625 ;
     RECT  20.772 63.528 23.094 63.625 ;
     RECT  2.34 63.625 23.094 64.903 ;
     RECT  23.904 63.528 23.922 64.903 ;
     RECT  26.352 63.528 26.37 65.551 ;
     RECT  2.34 64.903 23.922 65.593 ;
     RECT  39.924 63.528 39.942 65.593 ;
     RECT  29.607 65.593 29.697 65.641 ;
     RECT  33.012 65.245 33.03 65.641 ;
     RECT  2.34 65.593 24.297 65.785 ;
     RECT  29.556 65.641 29.697 65.785 ;
     RECT  2.34 65.785 24.354 65.821 ;
     RECT  25.992 65.551 26.37 65.821 ;
     RECT  35.007 65.593 35.097 65.863 ;
     RECT  45.807 65.593 45.897 65.863 ;
     RECT  51.207 65.593 51.297 65.863 ;
     RECT  56.607 65.593 56.697 65.863 ;
     RECT  62.007 65.593 62.097 65.863 ;
     RECT  67.407 65.593 67.497 65.863 ;
     RECT  72.807 65.593 72.897 65.863 ;
     RECT  78.207 65.593 78.297 65.863 ;
     RECT  83.607 65.593 83.697 65.863 ;
     RECT  89.007 65.593 89.097 65.863 ;
     RECT  94.407 65.593 94.497 65.863 ;
     RECT  99.807 65.593 99.897 65.863 ;
     RECT  105.207 65.593 105.297 65.863 ;
     RECT  110.607 65.593 110.697 65.863 ;
     RECT  116.007 65.593 116.097 65.863 ;
     RECT  34.815 65.863 35.097 65.941 ;
     RECT  25.992 65.821 26.73 65.947 ;
     RECT  31.608 65.749 31.626 65.947 ;
     RECT  34.815 65.941 35.262 65.947 ;
     RECT  39.924 65.593 40.497 65.947 ;
     RECT  29.376 65.785 29.697 65.983 ;
     RECT  39.132 65.947 40.497 66.055 ;
     RECT  31.608 65.947 31.698 66.091 ;
     RECT  32.472 65.641 33.03 66.091 ;
     RECT  34.164 65.947 35.262 66.091 ;
     RECT  36.792 65.941 36.81 66.091 ;
     RECT  27.72 65.911 27.738 66.181 ;
     RECT  29.34 65.983 29.697 66.181 ;
     RECT  34.164 66.091 35.946 66.187 ;
     RECT  36.792 66.091 37.314 66.187 ;
     RECT  25.992 65.947 26.766 66.217 ;
     RECT  27.648 66.181 27.738 66.217 ;
     RECT  30.78 66.181 30.798 66.217 ;
     RECT  34.164 66.187 37.314 66.217 ;
     RECT  38.844 66.055 40.497 66.217 ;
     RECT  33.768 66.217 37.314 66.235 ;
     RECT  33.768 66.235 37.494 66.253 ;
     RECT  38.376 66.217 40.497 66.253 ;
     RECT  31.608 66.091 33.03 66.283 ;
     RECT  33.768 66.253 40.497 66.283 ;
     RECT  25.992 66.217 27.738 66.289 ;
     RECT  29.304 66.181 29.697 66.289 ;
     RECT  30.708 66.217 30.87 66.289 ;
     RECT  31.608 66.283 40.497 66.289 ;
     RECT  30.708 66.289 40.497 66.325 ;
     RECT  25.992 66.289 29.697 66.451 ;
     RECT  30.492 66.325 40.497 66.451 ;
     RECT  25.992 66.451 40.497 66.515 ;
     RECT  2.34 65.821 25.146 66.595 ;
     RECT  25.992 66.515 31.842 66.595 ;
     RECT  32.976 66.515 40.497 66.623 ;
     RECT  33.012 66.623 40.497 66.701 ;
     RECT  41.4 67.063 41.418 67.261 ;
     RECT  2.34 66.595 31.842 67.369 ;
     RECT  41.4 67.261 41.922 67.369 ;
     RECT  41.292 67.369 41.922 67.405 ;
     RECT  2.34 67.369 31.986 67.441 ;
     RECT  33.048 66.701 40.497 67.441 ;
     RECT  41.292 67.405 42.21 67.441 ;
     RECT  32.868 67.441 42.21 67.567 ;
     RECT  2.34 67.441 32.13 67.595 ;
     RECT  2.415 67.595 32.13 67.675 ;
     RECT  32.868 67.567 42.318 67.675 ;
     RECT  43.164 67.441 43.182 67.703 ;
     RECT  2.415 67.675 42.318 67.709 ;
     RECT  2.415 67.709 41.526 67.739 ;
     RECT  42.3 67.709 42.318 68.251 ;
     RECT  2.415 67.739 30.006 68.405 ;
     RECT  30.996 67.739 41.526 68.449 ;
     RECT  42.3 68.251 42.714 68.449 ;
     RECT  5.364 68.405 30.006 68.521 ;
     RECT  30.996 68.449 42.714 68.521 ;
     RECT  5.364 68.521 42.714 68.683 ;
     RECT  5.364 68.683 42.75 68.719 ;
     RECT  43.524 68.251 43.542 68.719 ;
     RECT  5.364 68.719 43.866 68.909 ;
     RECT  5.364 68.909 43.362 69.215 ;
     RECT  5.364 69.215 43.038 69.323 ;
     RECT  30.816 69.323 43.038 69.581 ;
     RECT  2.415 68.405 4.554 69.835 ;
     RECT  5.364 69.323 30.042 69.835 ;
     RECT  30.888 69.581 43.038 70.375 ;
     RECT  2.415 69.835 30.042 70.403 ;
     RECT  29.124 70.403 30.042 70.411 ;
     RECT  30.78 70.375 43.038 70.411 ;
     RECT  2.415 70.403 28.242 70.601 ;
     RECT  29.124 70.411 43.038 70.681 ;
     RECT  29.124 70.681 43.362 71.117 ;
     RECT  5.544 70.601 28.242 71.149 ;
     RECT  29.124 71.117 42.894 71.149 ;
     RECT  5.544 71.149 42.894 71.447 ;
     RECT  28.188 71.447 42.894 71.609 ;
     RECT  28.224 71.609 42.894 71.879 ;
     RECT  2.415 70.601 4.698 71.887 ;
     RECT  5.544 71.447 27.45 71.887 ;
     RECT  28.224 71.879 42.75 71.987 ;
     RECT  28.224 71.987 35.37 72.149 ;
     RECT  36.18 71.987 42.75 72.149 ;
     RECT  28.224 72.149 31.734 72.185 ;
     RECT  28.224 72.185 31.554 72.257 ;
     RECT  32.472 72.149 35.37 72.419 ;
     RECT  2.415 71.887 27.45 72.667 ;
     RECT  28.224 72.257 31.518 72.667 ;
     RECT  2.415 72.667 31.518 72.689 ;
     RECT  32.472 72.419 35.262 73.003 ;
     RECT  36.18 72.149 42.282 73.039 ;
     RECT  32.4 73.003 35.262 73.229 ;
     RECT  36.036 73.039 42.282 73.229 ;
     RECT  25.92 72.689 31.518 73.243 ;
     RECT  32.4 73.229 34.038 73.243 ;
     RECT  34.776 73.229 35.262 73.291 ;
     RECT  36.036 73.229 42.21 73.291 ;
     RECT  34.776 73.291 42.21 73.301 ;
     RECT  25.92 73.243 34.038 73.373 ;
     RECT  36.36 73.301 42.21 73.409 ;
     RECT  33.912 73.373 34.038 73.499 ;
     RECT  36.36 73.409 38.394 73.499 ;
     RECT  34.02 73.499 34.038 73.522 ;
     RECT  2.415 72.689 25.146 73.615 ;
     RECT  25.92 73.373 33.102 73.615 ;
     RECT  39.132 73.409 42.21 73.805 ;
     RECT  39.132 73.805 40.806 73.811 ;
     RECT  41.544 73.805 42.21 73.949 ;
     RECT  42.12 73.949 42.21 74.039 ;
     RECT  36.36 73.499 38.286 74.075 ;
     RECT  39.168 73.811 40.806 74.075 ;
     RECT  42.12 74.039 42.138 74.075 ;
     RECT  34.776 73.301 35.622 74.107 ;
     RECT  39.168 74.075 40.662 74.111 ;
     RECT  2.415 73.615 33.102 74.219 ;
     RECT  36.36 74.075 38.214 74.309 ;
     RECT  39.168 74.111 40.497 74.309 ;
     RECT  34.272 74.107 35.622 74.317 ;
     RECT  36.36 74.309 38.034 74.317 ;
     RECT  34.128 74.317 38.034 74.345 ;
     RECT  39.168 74.309 39.186 74.381 ;
     RECT  31.32 74.219 33.102 74.389 ;
     RECT  34.128 74.345 37.854 74.389 ;
     RECT  31.32 74.389 37.854 74.417 ;
     RECT  39.96 74.309 40.497 74.453 ;
     RECT  31.32 74.417 37.602 74.759 ;
     RECT  2.415 74.219 30.546 74.965 ;
     RECT  31.32 74.759 33.21 74.965 ;
     RECT  34.02 74.759 37.602 75.271 ;
     RECT  34.02 75.271 37.638 75.739 ;
     RECT  38.484 75.631 38.502 75.739 ;
     RECT  2.415 74.965 33.21 75.775 ;
     RECT  34.02 75.739 38.502 75.775 ;
     RECT  2.412 75.775 38.502 75.839 ;
     RECT  2.412 75.839 5.886 75.929 ;
     RECT  2.412 75.929 5.706 75.965 ;
     RECT  6.66 75.839 38.502 76.505 ;
     RECT  2.415 75.965 5.706 76.613 ;
     RECT  4.356 76.613 5.706 76.819 ;
     RECT  6.66 76.505 38.322 76.819 ;
     RECT  2.415 76.613 3.294 77.395 ;
     RECT  4.356 76.819 38.322 77.395 ;
     RECT  2.415 77.395 38.502 77.521 ;
     RECT  2.376 77.521 38.502 77.549 ;
     RECT  2.376 77.549 3.186 77.585 ;
     RECT  2.376 77.585 3.15 77.597 ;
     RECT  2.415 77.597 3.15 77.621 ;
     RECT  3.996 77.549 38.502 77.855 ;
     RECT  3.996 77.855 13.77 78.089 ;
     RECT  14.544 77.855 38.502 78.089 ;
     RECT  3.996 78.089 9.702 78.773 ;
     RECT  10.44 78.089 13.77 78.907 ;
     RECT  14.544 78.089 38.43 78.907 ;
     RECT  10.44 78.907 38.43 78.935 ;
     RECT  4.14 78.773 9.702 78.979 ;
     RECT  10.44 78.935 12.222 78.979 ;
     RECT  12.996 78.935 38.43 79.051 ;
     RECT  12.996 79.051 38.574 79.079 ;
     RECT  4.14 78.979 12.222 79.169 ;
     RECT  13.032 79.079 38.574 79.169 ;
     RECT  5.112 79.169 12.222 79.181 ;
     RECT  13.032 79.169 38.322 79.205 ;
     RECT  6.624 79.181 12.222 79.241 ;
     RECT  4.14 79.169 4.302 79.313 ;
     RECT  5.112 79.181 5.274 79.439 ;
     RECT  6.624 79.241 9.774 79.439 ;
     RECT  4.284 79.313 4.302 79.475 ;
     RECT  6.624 79.439 8.838 79.619 ;
     RECT  9.576 79.439 9.774 79.709 ;
     RECT  10.584 79.241 12.222 79.709 ;
     RECT  10.584 79.709 12.042 79.715 ;
     RECT  6.804 79.619 8.838 79.745 ;
     RECT  9.576 79.709 9.702 79.745 ;
     RECT  10.62 79.715 12.042 79.745 ;
     RECT  6.804 79.745 6.822 79.757 ;
     RECT  9.684 79.745 9.702 79.757 ;
     RECT  13.215 79.205 38.322 79.853 ;
     RECT  7.815 79.745 8.838 79.979 ;
     RECT  10.62 79.745 10.854 79.979 ;
     RECT  11.628 79.745 12.042 79.979 ;
     RECT  10.62 79.979 10.638 80.015 ;
     RECT  8.82 79.979 8.838 80.123 ;
     RECT  11.628 79.979 11.97 80.285 ;
     RECT  14.22 79.853 38.322 80.321 ;
     RECT  13.215 79.853 13.497 80.347 ;
     RECT  34.812 80.321 38.322 80.357 ;
     RECT  11.844 80.285 11.862 80.381 ;
     RECT  34.815 80.357 38.322 80.519 ;
     RECT  12.924 80.347 13.497 80.591 ;
     RECT  13.104 80.591 13.497 80.599 ;
     RECT  14.22 80.321 34.002 80.599 ;
     RECT  34.815 80.519 38.106 80.663 ;
     RECT  34.815 80.663 37.458 80.789 ;
     RECT  36.468 80.789 36.594 80.825 ;
     RECT  13.104 80.599 34.002 80.861 ;
     RECT  36.576 80.825 36.594 80.861 ;
     RECT  13.215 80.861 34.002 80.933 ;
     RECT  34.815 80.789 35.622 81.101 ;
     RECT  14.292 80.933 34.002 81.329 ;
     RECT  33.588 81.329 34.002 81.481 ;
     RECT  34.815 81.101 35.097 81.481 ;
     RECT  37.44 80.789 37.458 81.509 ;
     RECT  33.588 81.481 35.097 81.707 ;
     RECT  14.292 81.329 32.742 81.779 ;
     RECT  33.588 81.707 33.606 81.779 ;
     RECT  14.292 81.779 32.562 81.941 ;
     RECT  14.292 81.941 32.274 82.013 ;
     RECT  14.292 82.013 31.77 82.049 ;
     RECT  13.215 80.933 13.497 82.075 ;
     RECT  14.292 82.049 21.15 82.075 ;
     RECT  13.215 82.075 21.15 82.139 ;
     RECT  21.888 82.049 31.77 82.139 ;
     RECT  14.652 82.139 21.15 82.175 ;
     RECT  13.215 82.139 13.806 82.211 ;
     RECT  21.888 82.139 21.906 82.211 ;
     RECT  22.752 82.139 28.062 82.211 ;
     RECT  29.088 82.139 31.266 82.247 ;
     RECT  14.652 82.175 21.078 82.283 ;
     RECT  22.752 82.211 24.39 82.283 ;
     RECT  25.38 82.211 28.062 82.283 ;
     RECT  31.248 82.247 31.266 82.283 ;
     RECT  29.088 82.247 30.51 82.301 ;
     RECT  14.76 82.283 15.786 82.409 ;
     RECT  19.8 82.283 21.078 82.409 ;
     RECT  25.38 82.283 25.398 82.409 ;
     RECT  26.244 82.283 28.062 82.409 ;
     RECT  19.8 82.409 20.61 82.445 ;
     RECT  26.856 82.409 27.738 82.445 ;
     RECT  29.088 82.301 30.186 82.445 ;
     RECT  22.86 82.283 23.202 82.481 ;
     RECT  23.976 82.283 24.297 82.481 ;
     RECT  27.432 82.445 27.45 82.481 ;
     RECT  23.184 82.481 23.202 82.553 ;
     RECT  15.156 82.409 15.786 82.589 ;
     RECT  16.812 82.283 18.99 82.589 ;
     RECT  20.088 82.445 20.106 82.589 ;
     RECT  29.415 82.445 30.186 82.589 ;
     RECT  15.156 82.589 15.318 82.679 ;
     RECT  16.812 82.589 18.897 82.679 ;
     RECT  15.156 82.679 15.21 82.685 ;
     RECT  15.156 82.685 15.174 82.715 ;
     RECT  16.812 82.679 16.83 82.751 ;
     RECT  17.568 82.679 17.694 82.787 ;
     RECT  17.568 82.787 17.586 82.823 ;
     RECT  2.415 77.621 2.697 83.987 ;
     RECT  7.815 79.979 8.097 83.987 ;
     RECT  13.215 82.211 13.497 83.987 ;
     RECT  18.615 82.679 18.897 83.987 ;
     RECT  24.015 82.481 24.297 83.987 ;
     RECT  29.415 82.589 29.697 83.987 ;
     RECT  34.815 81.707 35.097 83.987 ;
     RECT  40.215 74.453 40.497 83.987 ;
     RECT  45.615 65.863 45.897 83.987 ;
     RECT  51.015 65.863 51.297 83.987 ;
     RECT  56.415 65.863 56.697 83.987 ;
     RECT  61.815 65.863 62.097 83.987 ;
     RECT  67.215 65.863 67.497 83.987 ;
     RECT  72.615 65.863 72.897 83.987 ;
     RECT  78.015 65.863 78.297 83.987 ;
     RECT  83.415 65.863 83.697 83.987 ;
     RECT  88.815 65.863 89.097 83.987 ;
     RECT  94.215 65.863 94.497 83.987 ;
     RECT  99.615 65.863 99.897 83.987 ;
     RECT  105.015 65.863 105.297 83.987 ;
     RECT  110.415 65.863 110.697 83.987 ;
     RECT  115.815 65.863 116.097 83.987 ;
     RECT  121.215 33.809 121.497 83.987 ;
     RECT  126.615 2.413 126.897 83.987 ;
     RECT  132.015 2.413 132.297 83.987 ;
     RECT  137.415 2.413 137.697 83.987 ;
     RECT  2.415 83.987 2.505 84.257 ;
     RECT  7.815 83.987 7.905 84.257 ;
     RECT  13.215 83.987 13.305 84.257 ;
     RECT  18.615 83.987 18.705 84.257 ;
     RECT  24.015 83.987 24.105 84.257 ;
     RECT  29.415 83.987 29.505 84.257 ;
     RECT  34.815 83.987 34.905 84.257 ;
     RECT  40.215 83.987 40.305 84.257 ;
     RECT  45.615 83.987 45.705 84.257 ;
     RECT  51.015 83.987 51.105 84.257 ;
     RECT  56.415 83.987 56.505 84.257 ;
     RECT  61.815 83.987 61.905 84.257 ;
     RECT  67.215 83.987 67.305 84.257 ;
     RECT  72.615 83.987 72.705 84.257 ;
     RECT  78.015 83.987 78.105 84.257 ;
     RECT  83.415 83.987 83.505 84.257 ;
     RECT  88.815 83.987 88.905 84.257 ;
     RECT  94.215 83.987 94.305 84.257 ;
     RECT  99.615 83.987 99.705 84.257 ;
     RECT  105.015 83.987 105.105 84.257 ;
     RECT  110.415 83.987 110.505 84.257 ;
     RECT  115.815 83.987 115.905 84.257 ;
     RECT  121.215 83.987 121.305 84.257 ;
     RECT  126.615 83.987 126.705 84.257 ;
     RECT  132.015 83.987 132.105 84.257 ;
     RECT  137.415 83.987 137.505 84.257 ;
    LAYER M4 ;
     RECT  0.025 43.2 0.156 43.224 ;
     RECT  0.156 38.88 0.245 42.216 ;
     RECT  0.205 44.304 0.245 44.424 ;
     RECT  0.245 39.024 0.389 42.216 ;
     RECT  0.389 39.072 0.569 42.216 ;
     RECT  0.569 39.072 1.181 42.072 ;
     RECT  1.181 39.072 2.408 41.928 ;
     RECT  0.245 44.4 2.408 44.424 ;
     RECT  2.365 77.568 2.408 77.592 ;
     RECT  2.408 2.148 2.512 84.252 ;
     RECT  2.512 2.418 2.704 83.982 ;
     RECT  2.704 40.608 2.765 41.064 ;
     RECT  2.704 65.232 3.017 72.456 ;
     RECT  2.704 39.072 3.197 39.576 ;
     RECT  3.197 39.552 3.233 39.576 ;
     RECT  2.704 62.016 3.233 63.288 ;
     RECT  2.704 56.496 3.443 58.152 ;
     RECT  3.017 65.232 3.443 71.112 ;
     RECT  3.443 69.504 3.484 69.528 ;
     RECT  3.443 58.128 3.485 58.152 ;
     RECT  3.443 65.232 3.485 68.424 ;
     RECT  3.017 72.432 3.737 72.456 ;
     RECT  2.765 41.04 3.805 41.064 ;
     RECT  3.443 70.656 3.971 71.112 ;
     RECT  2.704 77.568 4.129 77.592 ;
     RECT  4.129 77.568 4.169 77.688 ;
     RECT  2.704 74.112 4.421 74.136 ;
     RECT  3.485 67.248 4.457 68.424 ;
     RECT  3.443 56.496 4.525 56.52 ;
     RECT  3.805 40.992 4.561 41.064 ;
     RECT  4.453 42.192 4.561 42.216 ;
     RECT  4.457 67.248 4.709 67.8 ;
     RECT  4.561 40.368 4.837 42.216 ;
     RECT  4.837 40.368 4.849 42.456 ;
     RECT  2.704 44.304 4.883 44.328 ;
     RECT  3.233 62.016 4.885 62.664 ;
     RECT  4.525 56.496 5.101 57.336 ;
     RECT  4.381 58.656 5.101 58.68 ;
     RECT  4.849 39.168 5.123 42.456 ;
     RECT  5.065 73.536 5.125 73.56 ;
     RECT  5.101 56.496 5.141 58.728 ;
     RECT  4.885 61.728 5.209 62.664 ;
     RECT  5.209 61.008 5.213 62.664 ;
     RECT  5.141 58.128 5.221 58.728 ;
     RECT  4.489 72.24 5.249 72.264 ;
     RECT  5.221 58.128 5.308 59.64 ;
     RECT  5.125 73.488 5.357 73.56 ;
     RECT  5.213 62.64 5.365 62.664 ;
     RECT  4.453 63.84 5.365 63.864 ;
     RECT  5.365 62.64 5.452 63.864 ;
     RECT  5.308 58.128 5.465 59.064 ;
     RECT  5.452 62.64 5.645 62.664 ;
     RECT  5.213 61.008 5.713 61.224 ;
     RECT  5.357 73.536 5.713 73.56 ;
     RECT  4.169 77.664 5.749 77.688 ;
     RECT  3.971 70.656 5.857 70.68 ;
     RECT  5.857 70.656 5.893 71.976 ;
     RECT  5.123 40.8 5.897 42.456 ;
     RECT  5.245 66.528 5.929 66.552 ;
     RECT  4.709 67.776 5.929 67.8 ;
     RECT  5.713 73.536 6.005 73.608 ;
     RECT  4.201 54.144 6.037 54.168 ;
     RECT  6.037 53.568 6.077 54.168 ;
     RECT  5.123 39.168 6.109 39.192 ;
     RECT  5.897 40.8 6.109 41.4 ;
     RECT  5.929 66.528 6.109 67.8 ;
     RECT  5.893 69.936 6.133 71.976 ;
     RECT  6.109 39.168 6.193 41.4 ;
     RECT  6.109 66.096 6.221 67.8 ;
     RECT  5.749 77.52 6.229 77.688 ;
     RECT  5.452 63.84 6.253 63.864 ;
     RECT  4.453 74.688 6.275 74.808 ;
     RECT  6.193 39.168 6.293 39.192 ;
     RECT  5.713 60.384 6.293 61.224 ;
     RECT  6.133 69.264 6.293 71.976 ;
     RECT  6.332 54.672 6.419 54.84 ;
     RECT  6.293 69.264 6.437 70.68 ;
     RECT  6.077 53.568 6.577 53.592 ;
     RECT  5.465 58.656 6.577 59.064 ;
     RECT  6.577 53.088 6.617 53.592 ;
     RECT  5.929 79.152 6.653 79.176 ;
     RECT  6.253 63.84 6.716 64.392 ;
     RECT  6.577 58.656 6.757 59.208 ;
     RECT  6.757 57.84 6.793 59.208 ;
     RECT  6.293 71.904 6.793 71.976 ;
     RECT  6.437 70.128 6.833 70.68 ;
     RECT  5.897 42.432 6.865 42.456 ;
     RECT  6.793 71.904 7.009 72.12 ;
     RECT  6.793 57.12 7.141 59.208 ;
     RECT  6.293 60.384 7.141 60.408 ;
     RECT  6.221 66.096 7.189 66.6 ;
     RECT  6.221 67.776 7.189 67.8 ;
     RECT  6.229 77.088 7.189 77.688 ;
     RECT  6.716 63.792 7.244 64.392 ;
     RECT  7.244 63.36 7.285 64.392 ;
     RECT  7.189 66.096 7.285 67.848 ;
     RECT  7.285 63.36 7.369 67.848 ;
     RECT  6.685 68.976 7.369 69 ;
     RECT  6.833 70.656 7.429 70.68 ;
     RECT  7.009 71.904 7.429 72.36 ;
     RECT  6.005 73.584 7.429 73.608 ;
     RECT  6.419 54.672 7.585 54.696 ;
     RECT  6.685 55.68 7.585 55.704 ;
     RECT  7.333 62.16 7.657 62.184 ;
     RECT  7.657 61.92 7.765 62.184 ;
     RECT  7.369 63.36 7.765 69 ;
     RECT  7.189 77.088 7.765 77.976 ;
     RECT  6.133 35.76 7.808 35.784 ;
     RECT  6.193 40.272 7.808 41.4 ;
     RECT  6.865 42.432 7.808 42.552 ;
     RECT  5.281 43.536 7.808 43.56 ;
     RECT  7.477 50.112 7.808 50.424 ;
     RECT  6.617 53.088 7.808 53.112 ;
     RECT  7.585 54.672 7.808 55.704 ;
     RECT  7.141 57.12 7.808 60.408 ;
     RECT  7.765 61.92 7.808 69 ;
     RECT  7.429 70.656 7.808 73.608 ;
     RECT  6.275 74.688 7.808 74.712 ;
     RECT  7.765 76.32 7.808 77.976 ;
     RECT  6.793 79.728 7.808 79.752 ;
     RECT  7.808 2.148 7.912 84.252 ;
     RECT  7.912 2.418 8.104 83.982 ;
     RECT  8.104 60.384 8.201 62.184 ;
     RECT  8.104 49.968 8.243 50.424 ;
     RECT  8.104 52.992 8.243 53.112 ;
     RECT  8.104 54.48 8.243 54.504 ;
     RECT  8.104 56.976 8.381 59.064 ;
     RECT  8.381 57.12 8.476 59.064 ;
     RECT  8.104 40.8 8.489 41.4 ;
     RECT  8.243 49.968 8.597 50.04 ;
     RECT  8.104 75.408 8.597 77.976 ;
     RECT  8.476 59.04 8.921 59.064 ;
     RECT  8.104 35.76 9.065 35.784 ;
     RECT  8.243 52.992 9.065 53.016 ;
     RECT  8.104 65.424 9.169 65.688 ;
     RECT  8.104 66.672 9.169 69.672 ;
     RECT  8.489 40.8 9.173 41.112 ;
     RECT  9.169 65.424 9.173 69.672 ;
     RECT  8.104 55.536 9.205 55.56 ;
     RECT  8.104 63.744 9.241 64.344 ;
     RECT  9.173 65.424 9.241 65.832 ;
     RECT  8.104 71.904 9.313 73.608 ;
     RECT  8.201 61.2 9.349 62.184 ;
     RECT  9.241 63.216 9.349 65.832 ;
     RECT  9.349 61.2 9.353 65.832 ;
     RECT  9.173 67.68 9.353 69.672 ;
     RECT  9.313 71.28 9.389 73.608 ;
     RECT  9.353 69.6 9.425 69.672 ;
     RECT  9.349 35.328 9.433 35.352 ;
     RECT  9.425 69.648 9.445 69.672 ;
     RECT  9.445 69.648 9.491 69.912 ;
     RECT  9.389 71.28 9.491 71.304 ;
     RECT  9.277 59.52 9.533 59.544 ;
     RECT  9.353 61.2 9.605 65.592 ;
     RECT  9.205 54.576 9.677 55.56 ;
     RECT  8.476 57.12 9.677 57.576 ;
     RECT  8.104 79.728 9.713 79.752 ;
     RECT  8.597 75.408 9.745 77.688 ;
     RECT  9.491 69.888 9.929 69.912 ;
     RECT  9.389 73.584 9.997 73.608 ;
     RECT  8.104 42.432 10.037 43.656 ;
     RECT  9.353 67.68 10.141 68.232 ;
     RECT  10.037 43.632 10.145 43.656 ;
     RECT  9.173 40.848 10.213 41.112 ;
     RECT  10.141 67.536 10.213 68.232 ;
     RECT  9.745 75.216 10.22 77.688 ;
     RECT  9.677 55.248 10.249 55.56 ;
     RECT  10.22 75.024 10.289 77.688 ;
     RECT  10.289 75.024 10.307 76.296 ;
     RECT  9.817 71.04 10.361 71.064 ;
     RECT  9.605 61.872 10.433 65.592 ;
     RECT  10.213 40.848 10.465 41.448 ;
     RECT  9.677 57.264 10.465 57.576 ;
     RECT  10.465 57.264 10.469 57.912 ;
     RECT  10.469 57.312 10.501 57.912 ;
     RECT  10.213 67.392 10.549 68.232 ;
     RECT  10.549 67.392 10.645 68.904 ;
     RECT  10.645 67.392 10.681 69.624 ;
     RECT  9.997 73.584 10.681 73.944 ;
     RECT  10.307 75.696 10.685 76.296 ;
     RECT  10.249 55.248 10.789 55.896 ;
     RECT  10.681 72.96 10.789 73.944 ;
     RECT  10.433 63.168 10.829 65.592 ;
     RECT  10.609 34.464 10.861 34.488 ;
     RECT  10.501 57.312 10.861 58.152 ;
     RECT  10.037 42.432 10.865 42.552 ;
     RECT  10.829 63.888 10.865 65.592 ;
     RECT  10.861 34.464 10.969 34.872 ;
     RECT  10.789 55.248 10.973 56.28 ;
     RECT  10.289 77.424 11.005 77.688 ;
     RECT  10.825 60.288 11.041 60.312 ;
     RECT  10.865 64.224 11.045 65.592 ;
     RECT  10.681 67.296 11.081 69.624 ;
     RECT  10.861 57.312 11.117 59.016 ;
     RECT  10.433 61.872 11.132 62.184 ;
     RECT  11.132 61.392 11.219 62.184 ;
     RECT  10.537 28.992 11.221 29.016 ;
     RECT  11.041 60.144 11.221 60.312 ;
     RECT  10.465 40.56 11.257 41.448 ;
     RECT  10.573 79.68 11.269 79.704 ;
     RECT  11.221 59.232 11.293 60.312 ;
     RECT  11.269 79.68 11.315 79.992 ;
     RECT  10.789 72.96 11.324 74.088 ;
     RECT  11.324 72.384 11.365 74.088 ;
     RECT  11.221 28.272 11.401 29.016 ;
     RECT  11.005 77.424 11.401 78.072 ;
     RECT  10.973 55.248 11.405 55.272 ;
     RECT  11.365 72.144 11.405 74.088 ;
     RECT  11.405 72.144 11.411 72.408 ;
     RECT  10.973 56.256 11.509 56.28 ;
     RECT  11.117 57.312 11.509 58.152 ;
     RECT  11.405 73.92 11.513 74.088 ;
     RECT  10.865 42.528 11.545 42.552 ;
     RECT  11.293 59.232 11.549 60.36 ;
     RECT  11.509 56.256 11.585 58.152 ;
     RECT  11.257 40.416 11.621 41.448 ;
     RECT  11.401 27.36 11.657 29.016 ;
     RECT  10.969 34.464 11.725 34.92 ;
     RECT  11.045 65.568 11.765 65.592 ;
     RECT  11.473 54.72 11.801 54.744 ;
     RECT  11.315 79.968 11.833 79.992 ;
     RECT  11.585 56.256 11.837 57.576 ;
     RECT  11.833 79.968 11.873 80.376 ;
     RECT  11.045 64.224 11.905 64.44 ;
     RECT  11.081 67.296 11.941 69.288 ;
     RECT  11.329 33.024 11.945 33.048 ;
     RECT  11.725 34.464 11.977 35.016 ;
     RECT  11.725 38.4 11.977 38.424 ;
     RECT  11.837 56.256 11.977 56.28 ;
     RECT  11.941 66.864 11.977 69.288 ;
     RECT  11.549 59.232 12.017 59.256 ;
     RECT  11.401 77.424 12.077 78.168 ;
     RECT  11.905 24.48 12.121 24.504 ;
     RECT  11.219 61.872 12.121 62.184 ;
     RECT  12.077 77.424 12.131 78.696 ;
     RECT  12.013 46.8 12.157 46.824 ;
     RECT  11.977 55.968 12.161 56.28 ;
     RECT  11.549 60.288 12.161 60.36 ;
     RECT  12.131 77.52 12.161 78.696 ;
     RECT  12.161 60.336 12.229 60.36 ;
     RECT  12.121 61.872 12.229 62.52 ;
     RECT  11.905 64.176 12.229 64.44 ;
     RECT  11.977 66.24 12.301 69.288 ;
     RECT  11.977 38.208 12.337 38.424 ;
     RECT  12.229 64.128 12.337 64.44 ;
     RECT  11.545 42.528 12.373 42.84 ;
     RECT  12.301 66.24 12.373 70.008 ;
     RECT  11.725 71.088 12.373 71.112 ;
     RECT  10.685 76.08 12.409 76.296 ;
     RECT  12.229 60.336 12.481 62.52 ;
     RECT  11.411 72.144 12.553 72.168 ;
     RECT  12.409 76.08 12.553 76.344 ;
     RECT  11.837 57.312 12.589 57.576 ;
     RECT  12.337 37.872 12.625 38.424 ;
     RECT  12.553 75.792 12.625 76.344 ;
     RECT  12.553 72.144 12.661 72.504 ;
     RECT  10.825 52.992 12.757 53.016 ;
     RECT  12.757 52.992 12.769 54.168 ;
     RECT  11.621 40.56 12.841 41.448 ;
     RECT  12.481 60.336 12.841 62.76 ;
     RECT  12.337 64.032 12.841 64.44 ;
     RECT  12.625 37.872 12.877 39.288 ;
     RECT  11.873 80.352 13.045 80.376 ;
     RECT  12.589 57.312 13.057 57.72 ;
     RECT  12.877 37.584 13.093 39.288 ;
     RECT  12.841 40.56 13.093 41.496 ;
     RECT  12.769 52.992 13.093 54.696 ;
     RECT  12.161 55.968 13.093 55.992 ;
     RECT  12.373 66.24 13.093 71.112 ;
     RECT  12.661 72.144 13.093 72.936 ;
     RECT  11.513 73.92 13.093 73.944 ;
     RECT  12.625 75.408 13.093 76.344 ;
     RECT  12.161 77.52 13.093 78.072 ;
     RECT  12.841 60.336 13.129 64.44 ;
     RECT  13.129 60.336 13.201 64.968 ;
     RECT  13.093 66.24 13.201 72.936 ;
     RECT  12.121 24.48 13.208 25.224 ;
     RECT  11.657 27.648 13.208 29.016 ;
     RECT  9.349 30.336 13.208 30.36 ;
     RECT  11.977 34.464 13.208 35.208 ;
     RECT  13.093 37.584 13.208 41.496 ;
     RECT  12.373 42.528 13.208 43.32 ;
     RECT  12.157 46.8 13.208 47.16 ;
     RECT  8.597 50.016 13.208 50.04 ;
     RECT  13.093 52.992 13.208 55.992 ;
     RECT  13.057 57.312 13.208 58.68 ;
     RECT  13.201 60.336 13.208 72.936 ;
     RECT  13.093 73.92 13.208 78.072 ;
     RECT  13.045 79.824 13.208 80.376 ;
     RECT  13.208 2.148 13.312 84.252 ;
     RECT  13.312 2.418 13.504 83.982 ;
     RECT  13.504 60.816 13.565 76.632 ;
     RECT  13.565 73.632 13.601 76.632 ;
     RECT  13.565 60.816 13.619 72.504 ;
     RECT  13.504 53.568 13.637 59.832 ;
     RECT  13.637 53.568 13.667 59.256 ;
     RECT  13.619 66.144 13.673 72.504 ;
     RECT  13.667 53.568 13.709 58.104 ;
     RECT  13.504 79.776 13.709 79.848 ;
     RECT  13.619 60.816 13.745 65.16 ;
     RECT  13.673 72.48 13.781 72.504 ;
     RECT  13.709 54.72 13.817 58.104 ;
     RECT  13.601 74.4 13.889 76.632 ;
     RECT  13.673 66.144 14.105 71.4 ;
     RECT  13.504 52.416 14.147 52.44 ;
     RECT  13.504 28.176 14.249 32.28 ;
     RECT  13.817 56.448 14.285 58.104 ;
     RECT  13.504 81.504 14.365 82.104 ;
     RECT  14.249 28.272 14.501 32.28 ;
     RECT  13.817 54.72 14.501 54.936 ;
     RECT  14.501 54.72 14.537 54.744 ;
     RECT  13.504 50.016 14.573 50.04 ;
     RECT  13.504 42.432 14.605 44.136 ;
     RECT  13.889 74.688 14.713 76.632 ;
     RECT  13.504 34.464 14.785 35.496 ;
     RECT  13.745 60.816 14.821 64.968 ;
     RECT  14.741 52.368 14.825 52.392 ;
     RECT  13.504 23.328 14.857 25.608 ;
     RECT  13.667 59.232 14.861 59.256 ;
     RECT  14.749 80.928 14.861 80.952 ;
     RECT  14.713 74.688 14.869 76.824 ;
     RECT  13.504 36.912 14.893 41.448 ;
     RECT  14.605 42.432 14.893 44.472 ;
     RECT  14.821 72.864 14.929 72.984 ;
     RECT  14.821 60.576 15.037 64.968 ;
     RECT  14.869 75.792 15.037 76.824 ;
     RECT  13.709 53.568 15.073 53.592 ;
     RECT  14.893 36.912 15.077 44.472 ;
     RECT  14.857 23.328 15.109 26.088 ;
     RECT  13.504 27.12 15.109 27.144 ;
     RECT  15.077 37.056 15.145 44.472 ;
     RECT  14.105 66.432 15.145 71.4 ;
     RECT  14.929 72.432 15.145 72.984 ;
     RECT  14.365 82.08 15.181 82.104 ;
     RECT  13.504 46.752 15.217 47.352 ;
     RECT  14.501 28.272 15.221 31.992 ;
     RECT  15.181 82.08 15.221 82.68 ;
     RECT  15.109 23.328 15.289 27.144 ;
     RECT  15.221 28.272 15.289 29.88 ;
     RECT  15.037 60.576 15.308 65.016 ;
     RECT  15.145 66.432 15.325 72.984 ;
     RECT  15.073 53.376 15.397 53.592 ;
     RECT  14.285 56.448 15.397 58.056 ;
     RECT  15.325 66.432 15.469 73.32 ;
     RECT  15.145 37.056 15.509 45 ;
     RECT  15.308 60.48 15.541 65.016 ;
     RECT  15.469 66.384 15.541 73.32 ;
     RECT  14.869 74.688 15.577 74.76 ;
     RECT  15.541 60.48 15.613 73.32 ;
     RECT  14.785 33.696 15.649 35.496 ;
     RECT  15.649 33.408 15.685 35.496 ;
     RECT  15.289 23.328 15.689 29.88 ;
     RECT  15.577 74.64 15.725 74.76 ;
     RECT  15.685 33.408 15.761 35.544 ;
     RECT  15.221 31.008 15.829 31.992 ;
     RECT  15.397 53.376 15.829 53.688 ;
     RECT  15.509 37.056 15.833 44.76 ;
     RECT  15.725 74.688 15.865 74.76 ;
     RECT  15.037 75.792 15.865 76.92 ;
     RECT  15.349 59.424 15.877 59.448 ;
     RECT  15.397 56.448 15.973 58.152 ;
     RECT  15.877 59.184 15.973 59.448 ;
     RECT  15.613 60.48 15.973 73.56 ;
     RECT  15.833 39.84 15.977 44.76 ;
     RECT  15.217 46.176 16.045 47.352 ;
     RECT  15.973 56.448 16.045 73.56 ;
     RECT  14.773 50.736 16.085 50.76 ;
     RECT  15.649 55.344 16.153 55.368 ;
     RECT  16.045 56.4 16.153 73.56 ;
     RECT  15.833 37.056 16.189 38.712 ;
     RECT  16.045 46.176 16.193 47.736 ;
     RECT  15.733 19.296 16.213 19.32 ;
     RECT  15.865 74.688 16.229 76.92 ;
     RECT  16.213 18.96 16.261 19.32 ;
     RECT  16.261 18.96 16.297 19.848 ;
     RECT  15.877 20.832 16.297 20.856 ;
     RECT  16.153 55.344 16.297 73.56 ;
     RECT  15.781 22.032 16.309 22.056 ;
     RECT  15.829 17.568 16.357 17.592 ;
     RECT  15.829 53.088 16.357 53.688 ;
     RECT  15.689 28.224 16.369 29.88 ;
     RECT  15.829 31.008 16.369 32.232 ;
     RECT  16.189 36.912 16.369 38.712 ;
     RECT  16.193 46.32 16.441 47.736 ;
     RECT  16.441 46.32 16.477 47.928 ;
     RECT  16.229 76.896 16.477 76.92 ;
     RECT  13.504 77.952 16.477 77.976 ;
     RECT  16.369 36.528 16.481 38.712 ;
     RECT  16.297 55.152 16.481 73.56 ;
     RECT  16.481 55.152 16.508 58.152 ;
     RECT  16.477 46.32 16.549 48.504 ;
     RECT  15.761 33.408 16.589 33.432 ;
     RECT  16.481 59.184 16.589 73.56 ;
     RECT  16.508 55.104 16.633 58.152 ;
     RECT  16.357 53.088 16.729 53.832 ;
     RECT  16.633 55.104 16.729 56.52 ;
     RECT  13.709 79.776 16.733 79.8 ;
     RECT  16.481 36.768 16.801 38.712 ;
     RECT  16.357 17.568 16.837 17.976 ;
     RECT  16.297 18.96 16.837 20.856 ;
     RECT  16.729 53.088 16.837 56.52 ;
     RECT  16.837 52.704 16.841 56.52 ;
     RECT  15.221 82.656 16.841 82.68 ;
     RECT  16.229 74.688 16.877 75.912 ;
     RECT  16.549 46.32 16.933 48.696 ;
     RECT  16.309 21.984 16.981 22.056 ;
     RECT  15.689 23.328 16.981 26.76 ;
     RECT  15.977 40.032 16.981 44.76 ;
     RECT  16.477 76.896 16.981 77.976 ;
     RECT  16.837 17.568 17.089 20.856 ;
     RECT  16.981 21.984 17.089 26.76 ;
     RECT  15.761 34.464 17.089 35.544 ;
     RECT  16.801 36.768 17.089 39 ;
     RECT  16.981 40.032 17.089 44.904 ;
     RECT  16.633 57.696 17.129 58.152 ;
     RECT  16.877 74.736 17.165 75.912 ;
     RECT  17.089 17.088 17.173 20.856 ;
     RECT  17.173 17.136 17.273 20.856 ;
     RECT  16.933 13.296 17.305 13.32 ;
     RECT  17.165 75.504 17.413 75.912 ;
     RECT  16.981 76.896 17.413 78.216 ;
     RECT  16.369 28.224 17.449 32.232 ;
     RECT  17.089 34.224 17.449 35.544 ;
     RECT  17.089 36.768 17.449 44.904 ;
     RECT  17.365 50.832 17.452 50.856 ;
     RECT  13.504 12.288 17.557 12.312 ;
     RECT  17.305 13.296 17.557 13.848 ;
     RECT  16.841 52.704 17.557 53.832 ;
     RECT  17.089 21.984 17.629 27.048 ;
     RECT  17.449 28.224 17.629 32.28 ;
     RECT  17.629 21.984 17.701 32.664 ;
     RECT  16.841 55.104 17.701 56.52 ;
     RECT  17.129 57.696 17.701 57.72 ;
     RECT  17.273 20.832 17.737 20.856 ;
     RECT  17.701 21.936 17.737 32.664 ;
     RECT  17.737 20.832 17.773 32.76 ;
     RECT  16.589 59.184 17.845 63.528 ;
     RECT  16.933 46.32 17.917 49.608 ;
     RECT  17.557 6 17.953 6.024 ;
     RECT  17.773 20.832 17.953 33.048 ;
     RECT  17.953 6 18.025 6.84 ;
     RECT  17.953 20.832 18.025 33.096 ;
     RECT  17.449 34.224 18.025 44.904 ;
     RECT  17.845 59.184 18.025 63.624 ;
     RECT  16.589 64.656 18.025 73.56 ;
     RECT  18.025 20.832 18.061 44.904 ;
     RECT  17.917 46.272 18.061 49.608 ;
     RECT  17.557 52.032 18.085 53.832 ;
     RECT  18.025 59.184 18.205 73.56 ;
     RECT  17.413 75.504 18.205 78.216 ;
     RECT  17.485 10.848 18.229 10.872 ;
     RECT  17.557 12.288 18.229 13.848 ;
     RECT  18.229 9.936 18.241 13.848 ;
     RECT  18.205 59.184 18.241 73.608 ;
     RECT  17.273 17.136 18.277 19.848 ;
     RECT  18.061 20.832 18.277 49.608 ;
     RECT  18.085 51.888 18.277 53.832 ;
     RECT  17.701 55.104 18.277 57.72 ;
     RECT  18.169 80.112 18.385 80.136 ;
     RECT  18.277 17.136 18.421 49.608 ;
     RECT  18.313 50.88 18.421 50.904 ;
     RECT  18.241 59.184 18.493 74.088 ;
     RECT  18.025 6 18.608 6.888 ;
     RECT  18.241 9.792 18.608 13.848 ;
     RECT  17.485 15.552 18.608 15.576 ;
     RECT  18.421 17.136 18.608 50.904 ;
     RECT  18.277 51.888 18.608 57.72 ;
     RECT  18.493 59.184 18.608 74.328 ;
     RECT  18.205 75.504 18.608 78.696 ;
     RECT  18.385 80.112 18.608 80.904 ;
     RECT  17.521 82.272 18.608 82.296 ;
     RECT  18.608 2.148 18.712 84.252 ;
     RECT  18.712 2.418 18.904 83.982 ;
     RECT  18.904 6 18.965 6.6 ;
     RECT  18.904 60.384 19.139 80.904 ;
     RECT  19.139 60.384 19.145 76.056 ;
     RECT  19.145 63.504 19.181 76.056 ;
     RECT  18.904 8.496 19.217 8.52 ;
     RECT  18.904 11.952 19.235 59.208 ;
     RECT  19.139 77.04 19.577 80.904 ;
     RECT  19.577 77.04 19.613 80.328 ;
     RECT  19.235 11.952 19.793 13.848 ;
     RECT  18.904 82.224 19.829 82.248 ;
     RECT  19.235 14.928 19.969 59.208 ;
     RECT  19.145 60.384 19.969 62.472 ;
     RECT  19.969 14.928 19.973 62.472 ;
     RECT  19.181 63.792 20.003 64.68 ;
     RECT  18.965 6 20.009 6.36 ;
     RECT  19.973 14.928 20.153 60.696 ;
     RECT  20.153 14.928 20.257 15.912 ;
     RECT  19.181 65.76 20.257 76.056 ;
     RECT  19.613 77.04 20.257 78.504 ;
     RECT  20.153 16.896 20.297 60.696 ;
     RECT  20.257 65.76 20.297 78.504 ;
     RECT  20.003 64.656 20.339 64.68 ;
     RECT  20.257 14.832 20.401 15.912 ;
     RECT  19.613 79.536 20.483 80.328 ;
     RECT  20.297 66.768 20.531 78.504 ;
     RECT  20.545 4.368 20.581 4.392 ;
     RECT  18.904 9.792 20.653 9.816 ;
     RECT  19.793 11.952 20.684 13.224 ;
     RECT  20.531 66.768 20.729 76.872 ;
     RECT  20.684 11.328 20.771 13.224 ;
     RECT  20.653 9.792 20.833 10.296 ;
     RECT  20.581 4.176 20.869 4.392 ;
     RECT  20.869 4.08 20.941 4.392 ;
     RECT  20.009 6 20.941 6.024 ;
     RECT  20.771 12 21.049 13.224 ;
     RECT  20.401 14.256 21.049 15.912 ;
     RECT  19.973 61.968 21.059 62.472 ;
     RECT  20.297 17.28 21.085 60.696 ;
     RECT  21.059 61.968 21.085 62.28 ;
     RECT  20.531 77.856 21.085 78.504 ;
     RECT  20.941 4.08 21.125 6.024 ;
     RECT  21.125 5.232 21.161 6.024 ;
     RECT  20.833 9.792 21.301 10.776 ;
     RECT  20.729 66.768 21.305 76.584 ;
     RECT  21.085 77.856 21.305 78.984 ;
     RECT  21.085 17.28 21.373 62.28 ;
     RECT  21.305 76.368 21.449 76.584 ;
     RECT  21.049 2.736 21.481 2.76 ;
     RECT  20.005 8.16 21.481 8.184 ;
     RECT  21.301 9.648 21.481 10.776 ;
     RECT  21.049 12 21.481 15.912 ;
     RECT  21.305 66.768 21.485 75.384 ;
     RECT  21.481 8.16 21.625 10.776 ;
     RECT  20.483 80.208 21.637 80.328 ;
     RECT  21.085 81.312 21.637 81.336 ;
     RECT  21.637 80.208 21.683 82.2 ;
     RECT  21.449 76.368 21.701 76.392 ;
     RECT  21.683 80.208 21.733 80.376 ;
     RECT  21.625 7.92 21.74 10.776 ;
     RECT  19.933 0.192 21.769 0.216 ;
     RECT  21.485 66.768 21.773 75.24 ;
     RECT  21.733 79.776 21.773 80.376 ;
     RECT  21.74 7.92 21.781 10.872 ;
     RECT  21.481 12 21.781 15.96 ;
     RECT  21.781 7.92 21.841 15.96 ;
     RECT  21.841 7.392 21.881 15.96 ;
     RECT  21.481 2.496 21.913 2.76 ;
     RECT  21.773 66.768 22.033 74.856 ;
     RECT  21.881 9.6 22.057 15.96 ;
     RECT  21.373 16.944 22.057 62.28 ;
     RECT  20.297 65.76 22.057 65.784 ;
     RECT  22.033 66.768 22.057 70.536 ;
     RECT  21.913 2.496 22.129 3.048 ;
     RECT  21.125 4.08 22.129 4.2 ;
     RECT  22.057 9.6 22.129 62.28 ;
     RECT  22.129 9.6 22.133 62.424 ;
     RECT  22.129 2.208 22.165 4.2 ;
     RECT  21.161 5.472 22.165 6.024 ;
     RECT  21.881 7.392 22.165 8.616 ;
     RECT  21.769 0.192 22.201 0.888 ;
     RECT  22.165 1.968 22.201 4.2 ;
     RECT  22.165 5.472 22.205 8.616 ;
     RECT  22.205 5.472 22.241 7.416 ;
     RECT  21.305 77.856 22.273 78.168 ;
     RECT  22.133 14.352 22.357 62.424 ;
     RECT  22.309 63.84 22.357 63.864 ;
     RECT  22.357 14.352 22.457 62.52 ;
     RECT  22.133 9.6 22.493 13.32 ;
     RECT  22.457 14.784 22.536 62.52 ;
     RECT  22.357 63.648 22.536 63.864 ;
     RECT  22.493 9.6 22.547 9.672 ;
     RECT  22.241 6 22.588 7.416 ;
     RECT  21.773 79.776 22.597 79.8 ;
     RECT  22.597 79.536 22.637 79.8 ;
     RECT  22.201 0.192 22.709 4.2 ;
     RECT  22.273 77.52 22.741 78.168 ;
     RECT  22.637 79.536 22.741 79.56 ;
     RECT  22.588 7.392 22.745 7.416 ;
     RECT  22.741 77.52 22.787 79.56 ;
     RECT  22.588 6 22.817 6.264 ;
     RECT  22.493 10.8 22.925 13.32 ;
     RECT  22.536 14.784 22.925 63.864 ;
     RECT  22.787 77.52 22.957 79.272 ;
     RECT  22.925 16.896 22.997 63.864 ;
     RECT  22.033 71.616 23.029 74.856 ;
     RECT  22.957 76.848 23.029 79.272 ;
     RECT  23.029 71.616 23.036 75.144 ;
     RECT  23.029 76.368 23.036 79.272 ;
     RECT  22.205 8.592 23.389 8.616 ;
     RECT  22.057 65.76 23.785 70.536 ;
     RECT  23.036 71.616 23.785 79.272 ;
     RECT  22.547 9.6 23.929 9.624 ;
     RECT  22.925 10.8 23.929 12.312 ;
     RECT  22.709 0.192 24.008 3.336 ;
     RECT  22.817 6 24.008 6.024 ;
     RECT  23.389 7.968 24.008 8.616 ;
     RECT  23.929 9.6 24.008 12.312 ;
     RECT  22.925 13.296 24.008 13.32 ;
     RECT  22.925 14.784 24.008 15.768 ;
     RECT  22.997 16.896 24.008 63.672 ;
     RECT  23.785 65.76 24.008 79.272 ;
     RECT  23.533 80.88 24.008 80.904 ;
     RECT  21.683 82.176 24.008 82.2 ;
     RECT  24.008 65.76 24.112 84.252 ;
     RECT  24.112 65.76 24.2 83.982 ;
     RECT  24.008 0.192 24.304 63.672 ;
     RECT  24.2 65.598 24.304 83.982 ;
     RECT  24.304 0.192 24.361 3.048 ;
     RECT  24.304 7.824 24.509 8.808 ;
     RECT  24.509 7.824 24.545 7.848 ;
     RECT  24.304 10.416 24.653 13.32 ;
     RECT  24.304 14.688 24.689 14.712 ;
     RECT  24.653 10.416 24.797 10.584 ;
     RECT  24.304 17.856 24.803 63.672 ;
     RECT  24.797 10.512 25.091 10.584 ;
     RECT  24.653 11.664 25.091 13.32 ;
     RECT  25.091 10.56 25.157 10.584 ;
     RECT  25.091 11.664 25.187 13.032 ;
     RECT  24.304 76.512 25.337 80.904 ;
     RECT  24.304 65.76 25.373 75.528 ;
     RECT  25.337 79.488 25.441 80.904 ;
     RECT  24.304 82.176 25.441 82.2 ;
     RECT  24.304 15.744 25.484 15.768 ;
     RECT  25.373 65.76 25.553 75.432 ;
     RECT  25.337 76.512 25.589 78.408 ;
     RECT  24.304 6 25.621 6.552 ;
     RECT  25.441 79.488 25.625 82.2 ;
     RECT  25.589 76.848 25.733 78.408 ;
     RECT  25.621 6 25.765 7.032 ;
     RECT  25.484 15.744 25.801 16.296 ;
     RECT  25.625 81.216 25.805 82.2 ;
     RECT  25.765 5.232 25.837 7.032 ;
     RECT  25.801 15.744 25.981 16.536 ;
     RECT  25.873 4.224 26.089 4.248 ;
     RECT  25.837 5.232 26.089 7.128 ;
     RECT  25.441 9.072 26.125 9.096 ;
     RECT  25.981 15.744 26.125 16.824 ;
     RECT  26.089 4.224 26.129 7.128 ;
     RECT  24.361 0.144 26.161 3.048 ;
     RECT  26.129 4.224 26.161 7.032 ;
     RECT  25.805 81.456 26.345 82.2 ;
     RECT  25.187 11.76 26.381 13.032 ;
     RECT  25.625 79.488 26.413 79.8 ;
     RECT  25.733 77.136 26.437 78.408 ;
     RECT  26.413 79.44 26.437 79.8 ;
     RECT  26.125 8.688 26.483 9.096 ;
     RECT  26.161 0.144 26.561 7.032 ;
     RECT  25.553 71.616 26.593 75.288 ;
     RECT  26.125 14.928 26.741 16.824 ;
     RECT  25.553 65.76 26.741 70.056 ;
     RECT  26.561 4.464 26.813 6.552 ;
     RECT  26.593 71.472 26.849 75.288 ;
     RECT  26.345 82.176 26.885 82.2 ;
     RECT  26.845 10.032 26.957 10.056 ;
     RECT  26.813 5.472 27.029 6.552 ;
     RECT  26.437 77.136 27.313 79.8 ;
     RECT  27.313 76.512 27.317 79.8 ;
     RECT  26.741 14.928 27.341 16.776 ;
     RECT  26.741 67.776 27.349 70.056 ;
     RECT  27.349 67.776 27.395 70.104 ;
     RECT  27.341 14.784 27.425 16.776 ;
     RECT  26.849 71.616 27.425 75.288 ;
     RECT  27.395 67.968 27.491 70.104 ;
     RECT  27.425 72.672 27.491 75.288 ;
     RECT  26.381 12.288 27.493 13.032 ;
     RECT  27.317 79.44 27.493 79.8 ;
     RECT  26.561 0.144 27.565 2.904 ;
     RECT  27.491 74.592 27.605 75.288 ;
     RECT  27.425 15.744 27.641 16.776 ;
     RECT  27.493 12.288 27.781 13.08 ;
     RECT  27.317 76.512 27.781 78.168 ;
     RECT  27.491 72.672 27.827 73.224 ;
     RECT  27.781 76.32 27.827 78.168 ;
     RECT  27.565 0.144 27.875 2.952 ;
     RECT  27.491 67.968 27.893 70.056 ;
     RECT  27.827 78.144 27.965 78.168 ;
     RECT  27.421 81.6 28.033 81.624 ;
     RECT  27.827 76.32 28.109 77.112 ;
     RECT  27.425 71.616 28.141 71.64 ;
     RECT  24.803 17.856 28.181 63.528 ;
     RECT  28.109 76.32 28.213 76.488 ;
     RECT  27.029 6.528 28.321 6.552 ;
     RECT  27.827 72.672 28.361 72.984 ;
     RECT  26.483 8.688 28.403 8.712 ;
     RECT  28.321 6.528 28.405 6.84 ;
     RECT  26.741 65.76 28.453 66.792 ;
     RECT  27.493 79.44 28.453 80.04 ;
     RECT  28.181 17.856 28.681 18.84 ;
     RECT  27.853 10.56 28.717 10.584 ;
     RECT  27.029 5.472 28.825 5.496 ;
     RECT  28.453 79.44 28.969 80.568 ;
     RECT  27.781 12.288 28.981 13.272 ;
     RECT  28.453 65.76 29.005 67.32 ;
     RECT  27.893 68.304 29.005 70.056 ;
     RECT  27.875 0.144 29.041 2.904 ;
     RECT  28.969 78.96 29.041 80.568 ;
     RECT  28.033 81.6 29.041 81.72 ;
     RECT  27.605 74.592 29.077 74.76 ;
     RECT  28.213 75.84 29.077 76.488 ;
     RECT  29.041 78.96 29.077 81.72 ;
     RECT  29.041 0.144 29.297 3.384 ;
     RECT  28.361 72.768 29.365 72.984 ;
     RECT  29.297 0.192 29.408 3.384 ;
     RECT  28.681 4.368 29.408 4.392 ;
     RECT  28.825 5.472 29.408 6.12 ;
     RECT  29.113 8.448 29.408 8.472 ;
     RECT  28.717 10.56 29.408 10.728 ;
     RECT  28.981 11.904 29.408 13.272 ;
     RECT  28.892 14.544 29.408 14.568 ;
     RECT  27.641 16.704 29.408 16.776 ;
     RECT  28.681 17.76 29.408 18.84 ;
     RECT  28.181 19.824 29.408 63.528 ;
     RECT  29.005 65.76 29.408 70.056 ;
     RECT  28.141 71.28 29.408 71.64 ;
     RECT  29.365 72.768 29.408 73.608 ;
     RECT  29.077 74.592 29.408 76.488 ;
     RECT  29.077 78.96 29.408 82.296 ;
     RECT  29.408 65.76 29.512 84.252 ;
     RECT  29.512 65.76 29.6 83.982 ;
     RECT  29.408 0.192 29.704 63.528 ;
     RECT  29.6 65.598 29.704 83.982 ;
     RECT  29.704 17.664 29.843 18.168 ;
     RECT  29.704 65.76 29.873 73.608 ;
     RECT  29.873 68.736 29.981 73.608 ;
     RECT  29.704 3.312 30.089 3.672 ;
     RECT  29.704 8.448 30.089 9.288 ;
     RECT  29.981 68.736 30.125 69.576 ;
     RECT  29.704 5.232 30.161 6.12 ;
     RECT  30.089 9.072 30.197 9.288 ;
     RECT  29.704 75.888 30.197 80.568 ;
     RECT  29.704 15.792 30.269 15.816 ;
     RECT  29.704 0.192 30.323 2.328 ;
     RECT  30.197 9.264 30.413 9.288 ;
     RECT  29.704 82.08 30.521 82.296 ;
     RECT  30.089 3.312 30.557 3.336 ;
     RECT  30.197 79.056 30.697 80.568 ;
     RECT  30.521 82.08 30.697 82.104 ;
     RECT  29.704 12.288 30.737 14.52 ;
     RECT  30.737 13.872 30.845 14.52 ;
     RECT  29.843 18.144 30.989 18.168 ;
     RECT  29.981 70.608 30.989 73.608 ;
     RECT  30.697 79.056 30.989 82.104 ;
     RECT  30.989 79.056 30.995 81.624 ;
     RECT  30.769 9.84 31.025 9.864 ;
     RECT  30.197 75.888 31.133 77.4 ;
     RECT  30.323 0.816 31.273 2.328 ;
     RECT  30.989 70.608 31.331 71.304 ;
     RECT  30.161 6.096 31.345 6.12 ;
     RECT  30.125 69.024 31.381 69.576 ;
     RECT  31.331 70.608 31.381 71.208 ;
     RECT  29.873 65.76 31.385 67.704 ;
     RECT  30.989 72.576 31.421 73.608 ;
     RECT  31.133 75.888 31.421 77.112 ;
     RECT  31.345 6.096 31.453 6.744 ;
     RECT  31.453 6.048 31.475 6.744 ;
     RECT  31.385 67.392 31.489 67.704 ;
     RECT  30.995 79.056 31.493 81.432 ;
     RECT  30.845 14.496 31.529 14.52 ;
     RECT  31.421 72.96 31.621 73.608 ;
     RECT  31.597 74.64 31.621 74.664 ;
     RECT  31.381 69.024 31.669 71.208 ;
     RECT  31.621 72.96 31.709 74.664 ;
     RECT  31.493 79.056 31.709 81.144 ;
     RECT  31.709 80.016 31.745 81.144 ;
     RECT  31.709 74.64 31.907 74.664 ;
     RECT  31.669 10.8 32.101 10.824 ;
     RECT  31.921 8.832 32.141 8.856 ;
     RECT  31.489 67.392 32.141 67.944 ;
     RECT  29.704 19.824 32.177 63.528 ;
     RECT  31.421 75.888 32.245 77.064 ;
     RECT  32.177 19.824 32.281 21.384 ;
     RECT  32.281 19.392 32.293 21.384 ;
     RECT  32.101 10.752 32.389 10.824 ;
     RECT  30.737 12.288 32.389 12.312 ;
     RECT  32.245 75.12 32.425 77.064 ;
     RECT  31.273 0.816 32.461 2.904 ;
     RECT  31.385 65.76 32.461 66.264 ;
     RECT  32.389 10.752 32.476 12.312 ;
     RECT  32.461 0.192 32.509 2.904 ;
     RECT  31.475 6.048 32.569 6.072 ;
     RECT  31.669 68.976 32.569 71.208 ;
     RECT  31.709 72.96 32.573 73.608 ;
     RECT  32.461 65.664 32.605 66.264 ;
     RECT  32.573 72.96 32.605 73.032 ;
     RECT  31.745 80.304 32.609 81.144 ;
     RECT  32.509 0.192 32.627 2.28 ;
     RECT  32.425 75.12 32.681 77.112 ;
     RECT  32.476 10.752 32.717 11.16 ;
     RECT  32.605 72.912 32.717 73.032 ;
     RECT  32.627 0.192 32.771 1.128 ;
     RECT  32.476 12.288 32.857 12.312 ;
     RECT  32.857 12.288 32.941 13.128 ;
     RECT  32.605 65.664 32.965 66.36 ;
     RECT  32.141 67.392 32.965 67.416 ;
     RECT  32.681 75.168 33.041 77.112 ;
     RECT  32.353 78.48 33.071 78.504 ;
     RECT  32.569 68.976 33.073 71.352 ;
     RECT  33.041 75.936 33.073 77.112 ;
     RECT  33.071 78.432 33.073 78.504 ;
     RECT  32.569 6.048 33.109 6.312 ;
     RECT  33.073 75.936 33.185 78.504 ;
     RECT  32.627 2.256 33.203 2.28 ;
     RECT  32.771 0.816 33.347 1.128 ;
     RECT  33.356 14.304 33.397 14.328 ;
     RECT  32.965 65.664 33.397 67.416 ;
     RECT  33.397 13.632 33.443 14.328 ;
     RECT  31.741 16.224 33.443 16.248 ;
     RECT  33.109 6.048 33.491 6.888 ;
     RECT  33.073 68.976 33.505 71.688 ;
     RECT  32.717 72.912 33.505 72.984 ;
     RECT  33.185 76.224 33.637 78.504 ;
     RECT  32.609 80.352 33.637 81.144 ;
     RECT  33.637 76.224 33.689 81.144 ;
     RECT  33.505 68.976 33.721 72.984 ;
     RECT  33.689 76.224 33.724 80.04 ;
     RECT  33.724 76.224 33.725 79.512 ;
     RECT  33.347 0.816 33.779 1.08 ;
     RECT  33.721 68.976 33.833 73.32 ;
     RECT  33.833 73.296 33.901 73.32 ;
     RECT  33.901 73.296 34.009 73.368 ;
     RECT  33.397 65.664 34.045 67.8 ;
     RECT  33.833 68.976 34.081 72.216 ;
     RECT  34.009 73.296 34.165 73.512 ;
     RECT  33.725 76.224 34.225 78.168 ;
     RECT  34.225 75.744 34.297 78.168 ;
     RECT  33.181 17.616 34.453 17.64 ;
     RECT  32.293 18.672 34.453 21.384 ;
     RECT  33.779 0.816 34.513 0.84 ;
     RECT  34.513 0.576 34.585 0.84 ;
     RECT  34.585 4.128 34.621 4.152 ;
     RECT  34.045 65.664 34.621 67.896 ;
     RECT  34.081 68.928 34.621 72.216 ;
     RECT  34.153 7.44 34.657 7.464 ;
     RECT  34.585 0.192 34.741 0.84 ;
     RECT  34.153 2.592 34.741 2.616 ;
     RECT  34.741 0.192 34.808 2.616 ;
     RECT  34.621 3.888 34.808 4.152 ;
     RECT  33.491 6.048 34.808 6.312 ;
     RECT  34.657 7.44 34.808 7.992 ;
     RECT  32.717 11.136 34.808 11.16 ;
     RECT  32.941 12.288 34.808 12.312 ;
     RECT  33.443 13.632 34.808 13.656 ;
     RECT  33.721 14.832 34.808 14.856 ;
     RECT  34.453 17.616 34.808 21.384 ;
     RECT  34.621 65.664 34.808 72.216 ;
     RECT  34.165 73.296 34.808 74.136 ;
     RECT  34.297 75.12 34.808 78.168 ;
     RECT  33.725 79.44 34.808 79.512 ;
     RECT  33.689 81.072 34.808 81.096 ;
     RECT  34.808 65.664 34.912 84.252 ;
     RECT  34.808 0.192 34.931 21.384 ;
     RECT  34.912 65.664 35 83.982 ;
     RECT  34.931 0.528 35.104 21.384 ;
     RECT  35 65.598 35.104 83.982 ;
     RECT  35.104 65.664 35.129 67.704 ;
     RECT  35.104 68.88 35.129 70.296 ;
     RECT  35.104 17.616 35.237 19.272 ;
     RECT  35.129 67.392 35.273 67.704 ;
     RECT  35.273 67.68 35.363 67.704 ;
     RECT  35.104 73.248 35.381 73.32 ;
     RECT  35.104 75.12 35.381 78.12 ;
     RECT  35.104 20.784 35.453 21.384 ;
     RECT  35.381 75.12 35.507 76.488 ;
     RECT  35.104 8.16 35.525 8.184 ;
     RECT  35.381 77.952 35.561 78.12 ;
     RECT  35.104 80.736 35.633 81.096 ;
     RECT  35.104 79.104 35.747 79.704 ;
     RECT  35.633 80.736 35.747 80.76 ;
     RECT  35.104 0.528 35.813 3.96 ;
     RECT  35.237 17.856 35.849 19.272 ;
     RECT  35.104 9.648 35.891 12.312 ;
     RECT  35.507 76.32 35.957 76.488 ;
     RECT  35.561 78.096 35.957 78.12 ;
     RECT  35.813 2.256 36.029 3.96 ;
     RECT  35.813 0.528 36.092 1.176 ;
     RECT  35.104 6.048 36.097 6.072 ;
     RECT  35.129 68.88 36.097 70.104 ;
     RECT  36.029 2.304 36.133 3.96 ;
     RECT  35.747 79.104 36.137 79.512 ;
     RECT  35.104 72.192 36.169 72.216 ;
     RECT  35.507 75.12 36.173 75.144 ;
     RECT  36.137 79.104 36.173 79.416 ;
     RECT  35.129 65.664 36.205 66.36 ;
     RECT  36.133 2.304 36.341 4.584 ;
     RECT  36.341 2.304 36.373 4.632 ;
     RECT  36.097 6.048 36.373 7.32 ;
     RECT  35.891 9.648 36.389 9.672 ;
     RECT  36.373 2.304 36.419 7.32 ;
     RECT  35.104 13.776 36.421 13.8 ;
     RECT  36.097 68.448 36.421 70.92 ;
     RECT  36.169 72.192 36.421 72.984 ;
     RECT  36.092 0.288 36.467 1.176 ;
     RECT  36.421 13.776 36.469 14.664 ;
     RECT  36.421 67.776 36.493 72.984 ;
     RECT  36.419 2.304 36.497 6.072 ;
     RECT  36.469 13.776 36.515 14.952 ;
     RECT  36.467 0.576 36.533 1.176 ;
     RECT  35.957 76.464 36.565 76.488 ;
     RECT  36.497 2.304 36.605 3.624 ;
     RECT  36.565 76.464 36.611 76.968 ;
     RECT  36.497 5.088 36.641 6.072 ;
     RECT  36.515 13.776 36.749 13.8 ;
     RECT  36.515 14.832 36.857 14.952 ;
     RECT  35.849 17.856 36.889 17.88 ;
     RECT  36.605 2.304 36.929 3.048 ;
     RECT  36.889 17.472 36.949 18.264 ;
     RECT  35.849 19.248 36.949 19.272 ;
     RECT  36.611 76.848 37.041 76.968 ;
     RECT  36.533 0.816 37.045 1.176 ;
     RECT  35.891 11.328 37.1 12.312 ;
     RECT  37.1 11.328 37.187 12.408 ;
     RECT  36.997 80.64 37.253 80.664 ;
     RECT  36.173 79.104 37.325 79.128 ;
     RECT  36.205 65.664 37.331 66.696 ;
     RECT  36.641 5.136 37.393 6.072 ;
     RECT  36.419 7.296 37.393 7.32 ;
     RECT  37.045 0.816 37.469 1.752 ;
     RECT  36.493 67.776 37.505 73.272 ;
     RECT  37.505 71.712 37.525 73.272 ;
     RECT  37.484 75.744 37.571 75.768 ;
     RECT  37.041 76.848 37.571 77.88 ;
     RECT  37.187 12.192 37.573 12.408 ;
     RECT  36.949 17.472 37.645 19.272 ;
     RECT  37.331 65.664 37.649 66.312 ;
     RECT  37.505 67.776 37.753 70.536 ;
     RECT  37.525 71.712 37.829 73.896 ;
     RECT  37.573 12.192 37.861 12.504 ;
     RECT  36.853 13.584 37.861 13.608 ;
     RECT  37.645 17.472 37.861 19.512 ;
     RECT  37.829 73.776 37.865 73.896 ;
     RECT  37.861 17.472 38.005 19.608 ;
     RECT  36.929 2.88 38.053 3.048 ;
     RECT  37.393 5.136 38.081 7.32 ;
     RECT  37.753 67.344 38.081 70.536 ;
     RECT  37.861 12.192 38.149 13.608 ;
     RECT  38.053 2.88 38.153 3.288 ;
     RECT  38.153 3.264 38.189 3.288 ;
     RECT  38.081 5.424 38.333 7.32 ;
     RECT  37.571 76.944 38.333 77.352 ;
     RECT  35.453 21.36 38.437 21.384 ;
     RECT  32.177 22.464 38.437 63.528 ;
     RECT  37.469 0.816 38.485 1.416 ;
     RECT  38.149 11.712 38.509 13.608 ;
     RECT  37.681 15.168 38.509 15.192 ;
     RECT  38.509 11.712 38.513 15.192 ;
     RECT  38.513 11.712 38.549 12.888 ;
     RECT  38.005 17.088 38.549 19.608 ;
     RECT  38.485 0.816 38.629 1.464 ;
     RECT  37.465 9.072 38.761 9.096 ;
     RECT  38.513 13.92 38.761 15.192 ;
     RECT  38.549 19.008 38.761 19.608 ;
     RECT  38.629 0.192 38.8 1.464 ;
     RECT  38.333 5.424 38.819 6.552 ;
     RECT  38.761 13.92 38.821 15.288 ;
     RECT  37.829 71.712 38.837 72.408 ;
     RECT  38.773 3.84 38.86 3.864 ;
     RECT  38.821 13.92 38.908 15.912 ;
     RECT  38.908 13.92 38.917 15.48 ;
     RECT  38.549 17.088 38.945 17.88 ;
     RECT  38.549 11.712 39.053 12.84 ;
     RECT  37.865 73.776 39.121 73.8 ;
     RECT  39.121 73.344 39.161 73.8 ;
     RECT  38.8 0.144 39.205 1.464 ;
     RECT  37.649 65.664 39.229 65.976 ;
     RECT  38.081 68.256 39.301 70.536 ;
     RECT  39.301 68.256 39.589 70.632 ;
     RECT  39.013 10.08 39.625 10.104 ;
     RECT  39.053 11.712 39.625 12.312 ;
     RECT  39.205 0.144 39.637 1.992 ;
     RECT  39.589 67.68 39.661 70.632 ;
     RECT  38.837 71.712 39.661 71.736 ;
     RECT  38.761 19.008 39.685 19.656 ;
     RECT  39.637 0.144 39.781 2.328 ;
     RECT  39.781 0.144 39.925 2.376 ;
     RECT  39.925 0.144 39.973 2.52 ;
     RECT  38.819 6.048 40.069 6.552 ;
     RECT  39.973 0.144 40.208 2.616 ;
     RECT  40.069 6.048 40.208 6.888 ;
     RECT  38.761 8.976 40.208 9.096 ;
     RECT  39.625 10.08 40.208 12.312 ;
     RECT  38.917 13.92 40.208 15.432 ;
     RECT  38.945 17.856 40.208 17.88 ;
     RECT  39.685 19.008 40.208 19.752 ;
     RECT  39.229 65.664 40.208 66.12 ;
     RECT  39.661 67.68 40.208 71.736 ;
     RECT  39.161 73.344 40.208 73.368 ;
     RECT  40.208 65.664 40.312 84.252 ;
     RECT  40.208 0.144 40.4 19.992 ;
     RECT  40.312 65.664 40.4 83.982 ;
     RECT  40.4 0.144 40.504 20.262 ;
     RECT  40.4 65.598 40.504 83.982 ;
     RECT  40.504 11.712 40.691 13.56 ;
     RECT  40.504 8.496 40.739 10.632 ;
     RECT  40.739 9.504 40.78 10.632 ;
     RECT  40.504 15.264 40.883 15.288 ;
     RECT  40.504 18.768 41.213 20.088 ;
     RECT  40.504 73.488 41.213 73.512 ;
     RECT  40.504 69.216 41.357 70.632 ;
     RECT  40.739 8.496 41.465 8.52 ;
     RECT  40.504 0.144 41.489 2.952 ;
     RECT  41.489 0.144 41.573 3.048 ;
     RECT  40.78 9.792 41.677 10.632 ;
     RECT  40.691 11.712 41.677 13.032 ;
     RECT  41.677 16.512 41.749 16.536 ;
     RECT  41.749 16.032 41.861 16.536 ;
     RECT  41.533 17.712 41.897 17.736 ;
     RECT  41.357 69.744 41.965 70.632 ;
     RECT  41.861 16.032 41.969 16.056 ;
     RECT  41.573 0.144 42.185 2.904 ;
     RECT  40.504 67.68 42.221 67.704 ;
     RECT  41.677 9.792 42.227 13.032 ;
     RECT  42.14 14.4 42.227 14.424 ;
     RECT  42.181 17.088 42.509 17.112 ;
     RECT  41.965 69.744 42.565 70.728 ;
     RECT  40.504 71.712 42.565 71.736 ;
     RECT  42.565 69.744 42.611 71.736 ;
     RECT  42.577 68.352 42.709 68.376 ;
     RECT  42.611 69.744 42.709 71.112 ;
     RECT  42.709 68.352 42.755 71.112 ;
     RECT  40.504 5.136 42.757 6.072 ;
     RECT  42.755 70.608 43.049 71.112 ;
     RECT  42.185 0.144 43.297 2.856 ;
     RECT  42.755 68.928 43.301 68.952 ;
     RECT  42.757 5.136 43.373 6.648 ;
     RECT  43.049 71.088 43.373 71.112 ;
     RECT  43.297 0.144 43.621 3.288 ;
     RECT  41.213 19.008 43.625 20.088 ;
     RECT  43.621 0.144 43.733 3.864 ;
     RECT  43.733 0.192 43.945 3.864 ;
     RECT  43.945 0.192 44.129 4.152 ;
     RECT  42.227 11.712 44.165 13.032 ;
     RECT  44.129 3.6 44.341 4.152 ;
     RECT  44.341 3.6 44.597 4.824 ;
     RECT  43.153 8.688 44.701 8.712 ;
     RECT  42.227 9.792 44.701 10.632 ;
     RECT  44.701 8.688 45.301 10.632 ;
     RECT  44.165 11.712 45.301 12.552 ;
     RECT  44.845 7.392 45.565 7.416 ;
     RECT  44.129 0.192 45.608 2.376 ;
     RECT  44.597 3.6 45.608 4.536 ;
     RECT  43.373 6.048 45.608 6.072 ;
     RECT  45.565 7.392 45.608 7.464 ;
     RECT  45.301 8.688 45.608 12.552 ;
     RECT  43.261 17.424 45.608 17.448 ;
     RECT  43.625 19.248 45.608 20.088 ;
     RECT  40.504 65.664 45.608 65.688 ;
     RECT  45.608 65.664 45.712 84.252 ;
     RECT  45.608 0.192 45.8 20.088 ;
     RECT  45.712 65.664 45.8 83.982 ;
     RECT  45.8 0.192 45.904 20.262 ;
     RECT  45.8 65.598 45.904 83.982 ;
     RECT  45.904 6.816 46.145 8.088 ;
     RECT  46.145 6.816 46.433 7.704 ;
     RECT  46.433 6.816 46.549 7.656 ;
     RECT  46.549 7.104 46.577 7.656 ;
     RECT  45.904 9.792 46.649 13.656 ;
     RECT  46.577 7.104 46.757 7.464 ;
     RECT  45.904 17.328 46.757 17.448 ;
     RECT  46.757 7.44 46.793 7.464 ;
     RECT  45.904 0.192 46.883 1.704 ;
     RECT  45.904 3.12 47.041 4.68 ;
     RECT  46.883 0.288 47.171 1.704 ;
     RECT  47.171 0.864 47.413 1.704 ;
     RECT  47.041 3.12 47.477 4.776 ;
     RECT  47.477 3.12 47.545 3.864 ;
     RECT  47.545 2.88 47.621 3.864 ;
     RECT  47.413 0.864 47.729 1.752 ;
     RECT  47.797 6.816 48.044 6.84 ;
     RECT  48.044 6.24 48.131 6.84 ;
     RECT  46.649 9.792 48.188 9.816 ;
     RECT  48.131 6.816 48.229 6.84 ;
     RECT  48.188 9.792 48.229 10.008 ;
     RECT  46.649 11.424 48.229 13.656 ;
     RECT  48.229 9.792 48.301 13.656 ;
     RECT  47.621 2.88 48.341 3.768 ;
     RECT  48.301 9.504 48.481 13.656 ;
     RECT  48.481 9.504 48.881 13.704 ;
     RECT  48.341 3.408 49.205 3.768 ;
     RECT  48.881 9.6 49.313 13.704 ;
     RECT  49.057 5.184 49.417 5.208 ;
     RECT  49.417 5.184 49.453 5.64 ;
     RECT  49.313 9.984 49.673 13.704 ;
     RECT  48.229 6.816 49.705 7.368 ;
     RECT  49.417 8.496 50.353 8.52 ;
     RECT  50.317 9.6 50.353 9.624 ;
     RECT  49.453 4.656 50.677 5.64 ;
     RECT  49.705 6.672 50.677 7.368 ;
     RECT  50.677 4.656 50.713 7.368 ;
     RECT  50.353 8.496 50.713 9.624 ;
     RECT  49.673 10.608 50.725 13.704 ;
     RECT  47.729 0.864 50.749 1.416 ;
     RECT  50.713 4.656 50.869 9.624 ;
     RECT  50.725 10.608 50.869 14.232 ;
     RECT  50.749 0.192 51.008 1.416 ;
     RECT  49.205 3.408 51.008 3.432 ;
     RECT  50.869 4.656 51.008 14.232 ;
     RECT  46.757 17.328 51.008 17.352 ;
     RECT  45.904 19.248 51.008 20.088 ;
     RECT  45.904 65.664 51.008 65.688 ;
     RECT  51.008 65.664 51.112 84.252 ;
     RECT  51.008 0.192 51.2 20.088 ;
     RECT  51.112 65.664 51.2 83.982 ;
     RECT  51.2 0.192 51.304 20.262 ;
     RECT  51.2 65.598 51.304 83.982 ;
     RECT  51.304 4.176 51.437 8.52 ;
     RECT  51.304 0.192 51.971 1.704 ;
     RECT  51.971 0.192 52.067 1.416 ;
     RECT  51.437 4.176 52.265 8.472 ;
     RECT  51.304 10.608 52.513 14.232 ;
     RECT  51.304 2.88 52.657 3.192 ;
     RECT  52.265 4.176 52.657 4.68 ;
     RECT  52.513 9.744 52.661 14.232 ;
     RECT  52.265 6 52.741 8.472 ;
     RECT  52.661 9.744 52.741 13.656 ;
     RECT  52.067 0.192 52.769 1.224 ;
     RECT  52.741 6 52.787 13.656 ;
     RECT  52.787 8.976 52.828 13.656 ;
     RECT  52.828 9.744 52.949 13.656 ;
     RECT  52.769 0.576 53.333 1.224 ;
     RECT  53.333 0.576 53.345 1.752 ;
     RECT  53.345 0.864 53.363 1.752 ;
     RECT  52.657 2.88 53.665 4.68 ;
     RECT  52.787 6 53.665 7.896 ;
     RECT  53.363 1.152 53.705 1.752 ;
     RECT  53.665 2.736 53.845 4.68 ;
     RECT  53.665 5.952 53.845 7.896 ;
     RECT  52.949 10.032 53.891 13.656 ;
     RECT  53.891 10.032 53.989 11.736 ;
     RECT  53.845 2.736 53.993 7.896 ;
     RECT  53.989 9.216 54.065 11.736 ;
     RECT  53.993 2.88 54.092 7.896 ;
     RECT  54.065 9.216 54.092 9.24 ;
     RECT  54.092 2.88 54.179 9.24 ;
     RECT  53.705 1.2 54.389 1.752 ;
     RECT  54.179 2.88 54.389 7.656 ;
     RECT  54.389 2.88 54.425 2.904 ;
     RECT  54.389 1.728 54.713 1.752 ;
     RECT  54.389 3.936 54.749 7.656 ;
     RECT  54.749 3.936 54.893 5.304 ;
     RECT  54.749 6.576 55.213 7.656 ;
     RECT  55.213 6.576 55.325 7.992 ;
     RECT  54.179 9.216 55.325 9.24 ;
     RECT  54.893 4.224 56.408 5.304 ;
     RECT  55.325 6.576 56.408 7.896 ;
     RECT  54.065 10.608 56.408 11.736 ;
     RECT  53.891 13.008 56.408 13.656 ;
     RECT  51.304 17.328 56.408 17.352 ;
     RECT  51.304 19.248 56.408 20.088 ;
     RECT  51.304 65.664 56.408 65.688 ;
     RECT  56.408 2.148 56.512 20.088 ;
     RECT  56.408 65.664 56.512 84.252 ;
     RECT  56.512 2.418 56.6 20.088 ;
     RECT  56.512 65.664 56.6 83.982 ;
     RECT  56.6 2.418 56.704 20.262 ;
     RECT  56.6 65.598 56.704 83.982 ;
     RECT  56.704 4.224 57.053 5.304 ;
     RECT  57.053 4.944 57.269 5.304 ;
     RECT  57.269 4.944 58.277 5.208 ;
     RECT  58.277 5.136 58.673 5.208 ;
     RECT  56.704 6.912 58.781 7.656 ;
     RECT  58.705 15.168 58.813 15.192 ;
     RECT  58.813 14.928 59.069 15.192 ;
     RECT  58.781 7.392 59.285 7.656 ;
     RECT  58.673 5.184 59.465 5.208 ;
     RECT  59.653 8.688 60.545 8.712 ;
     RECT  60.289 5.616 60.649 5.64 ;
     RECT  59.285 7.392 60.649 7.416 ;
     RECT  60.649 5.616 60.689 7.416 ;
     RECT  60.689 5.616 60.865 7.224 ;
     RECT  60.865 5.088 61.808 7.224 ;
     RECT  56.704 10.608 61.808 11.736 ;
     RECT  56.704 13.008 61.808 13.656 ;
     RECT  59.069 14.928 61.808 14.952 ;
     RECT  56.704 17.328 61.808 17.352 ;
     RECT  56.704 19.248 61.808 20.088 ;
     RECT  56.704 65.664 61.808 65.688 ;
     RECT  61.808 2.148 61.912 20.088 ;
     RECT  61.808 65.664 61.912 84.252 ;
     RECT  61.912 2.418 62 20.088 ;
     RECT  61.912 65.664 62 83.982 ;
     RECT  62 2.418 62.104 20.262 ;
     RECT  62 65.598 62.104 83.982 ;
     RECT  62.104 10.608 67.208 11.736 ;
     RECT  62.104 13.008 67.208 13.656 ;
     RECT  62.104 17.328 67.208 17.352 ;
     RECT  62.104 19.248 67.208 20.088 ;
     RECT  62.104 65.664 67.208 65.688 ;
     RECT  67.208 2.148 67.312 20.088 ;
     RECT  67.208 65.664 67.312 84.252 ;
     RECT  67.312 2.418 67.4 20.088 ;
     RECT  67.312 65.664 67.4 83.982 ;
     RECT  67.4 2.418 67.504 20.262 ;
     RECT  67.4 65.598 67.504 83.982 ;
     RECT  67.504 13.008 72.457 13.656 ;
     RECT  67.504 10.608 72.469 11.736 ;
     RECT  72.457 12.864 72.469 13.656 ;
     RECT  72.469 10.608 72.608 11.784 ;
     RECT  72.469 12.816 72.608 13.656 ;
     RECT  67.504 17.328 72.608 17.352 ;
     RECT  67.504 19.248 72.608 20.088 ;
     RECT  67.504 65.664 72.608 65.688 ;
     RECT  72.608 2.148 72.712 20.088 ;
     RECT  72.608 65.664 72.712 84.252 ;
     RECT  72.712 2.418 72.8 20.088 ;
     RECT  72.712 65.664 72.8 83.982 ;
     RECT  72.8 2.418 72.904 20.262 ;
     RECT  72.8 65.598 72.904 83.982 ;
     RECT  72.904 10.608 73.091 14.472 ;
     RECT  73.091 11.136 74.617 14.472 ;
     RECT  38.437 21.36 74.621 63.528 ;
     RECT  74.732 16.272 74.761 16.296 ;
     RECT  74.617 11.136 74.797 14.904 ;
     RECT  74.761 16.032 74.797 16.296 ;
     RECT  74.797 11.136 74.819 16.296 ;
     RECT  72.904 19.248 74.905 20.088 ;
     RECT  74.819 11.136 75.197 16.056 ;
     RECT  75.197 15.984 75.341 16.056 ;
     RECT  74.905 19.248 75.445 20.136 ;
     RECT  75.197 11.136 75.521 14.904 ;
     RECT  75.341 16.032 75.665 16.056 ;
     RECT  72.904 17.328 76.381 17.352 ;
     RECT  76.381 17.088 76.561 17.352 ;
     RECT  75.521 11.136 76.633 14.136 ;
     RECT  76.561 16.944 76.925 17.352 ;
     RECT  76.633 11.136 76.94 14.376 ;
     RECT  76.94 11.136 77.027 15.048 ;
     RECT  75.445 19.248 77.713 20.184 ;
     RECT  77.027 11.136 78.008 14.808 ;
     RECT  76.957 16.08 78.008 16.104 ;
     RECT  76.925 17.328 78.008 17.352 ;
     RECT  77.713 19.248 78.008 20.328 ;
     RECT  72.904 65.664 78.008 65.688 ;
     RECT  78.008 2.148 78.112 20.328 ;
     RECT  78.008 65.664 78.112 84.252 ;
     RECT  78.112 65.664 78.2 83.982 ;
     RECT  78.112 2.418 78.304 20.328 ;
     RECT  78.2 65.598 78.304 83.982 ;
     RECT  78.304 11.136 83.408 14.136 ;
     RECT  78.304 17.328 83.408 17.352 ;
     RECT  78.304 19.248 83.408 20.328 ;
     RECT  78.304 65.664 83.408 65.688 ;
     RECT  83.408 2.148 83.512 20.328 ;
     RECT  83.408 65.664 83.512 84.252 ;
     RECT  83.512 65.664 83.6 83.982 ;
     RECT  83.512 2.418 83.704 20.328 ;
     RECT  83.6 65.598 83.704 83.982 ;
     RECT  83.704 11.136 88.808 14.136 ;
     RECT  83.704 17.328 88.808 17.352 ;
     RECT  83.704 19.248 88.808 20.328 ;
     RECT  83.704 65.664 88.808 65.688 ;
     RECT  88.808 2.148 88.912 20.328 ;
     RECT  88.808 65.664 88.912 84.252 ;
     RECT  88.912 65.664 89 83.982 ;
     RECT  88.912 2.418 89.104 20.328 ;
     RECT  89 65.598 89.104 83.982 ;
     RECT  89.104 11.136 94.208 14.136 ;
     RECT  89.104 17.328 94.208 17.352 ;
     RECT  89.104 19.248 94.208 20.328 ;
     RECT  89.104 65.664 94.208 65.688 ;
     RECT  94.208 2.148 94.312 20.328 ;
     RECT  94.208 65.664 94.312 84.252 ;
     RECT  94.312 65.664 94.4 83.982 ;
     RECT  94.312 2.418 94.504 20.328 ;
     RECT  94.4 65.598 94.504 83.982 ;
     RECT  94.504 11.136 99.608 14.136 ;
     RECT  94.504 17.328 99.608 17.352 ;
     RECT  94.504 19.248 99.608 20.328 ;
     RECT  94.504 65.664 99.608 65.688 ;
     RECT  99.608 2.148 99.712 20.328 ;
     RECT  99.608 65.664 99.712 84.252 ;
     RECT  99.712 65.664 99.8 83.982 ;
     RECT  99.712 2.418 99.904 20.328 ;
     RECT  99.8 65.598 99.904 83.982 ;
     RECT  99.904 11.136 105.008 14.136 ;
     RECT  99.904 17.328 105.008 17.352 ;
     RECT  99.904 19.248 105.008 20.328 ;
     RECT  99.904 65.664 105.008 65.688 ;
     RECT  105.008 2.148 105.112 20.328 ;
     RECT  105.008 65.664 105.112 84.252 ;
     RECT  105.112 65.664 105.2 83.982 ;
     RECT  105.112 2.418 105.304 20.328 ;
     RECT  105.2 65.598 105.304 83.982 ;
     RECT  105.304 11.136 110.408 14.136 ;
     RECT  105.304 17.328 110.408 17.352 ;
     RECT  105.304 19.248 110.408 20.328 ;
     RECT  105.304 65.664 110.408 65.688 ;
     RECT  110.408 2.148 110.512 20.328 ;
     RECT  110.408 65.664 110.512 84.252 ;
     RECT  110.512 65.664 110.6 83.982 ;
     RECT  110.512 2.418 110.704 20.328 ;
     RECT  110.6 65.598 110.704 83.982 ;
     RECT  110.704 17.328 114.577 17.4 ;
     RECT  110.704 19.248 114.577 20.328 ;
     RECT  114.577 17.328 115.441 17.448 ;
     RECT  115.441 16.56 115.621 17.688 ;
     RECT  110.704 11.136 115.808 14.136 ;
     RECT  115.621 16.56 115.808 18.264 ;
     RECT  114.577 19.248 115.808 20.376 ;
     RECT  110.704 65.664 115.808 65.688 ;
     RECT  115.808 2.148 115.912 20.376 ;
     RECT  115.808 65.664 115.912 84.252 ;
     RECT  115.912 65.664 116 83.982 ;
     RECT  115.912 2.418 116.104 20.376 ;
     RECT  116 65.598 116.104 83.982 ;
     RECT  74.621 21.888 116.521 63.528 ;
     RECT  116.104 19.248 116.629 20.376 ;
     RECT  116.521 21.696 116.629 63.528 ;
     RECT  116.629 19.248 117.216 63.528 ;
     RECT  116.104 11.136 117.353 18.264 ;
     RECT  116.104 65.664 117.395 65.688 ;
     RECT  117.216 19.248 117.425 62.424 ;
     RECT  117.425 19.248 117.443 50.616 ;
     RECT  117.425 51.84 117.461 62.136 ;
     RECT  117.443 19.248 117.491 22.248 ;
     RECT  117.443 23.232 117.497 50.616 ;
     RECT  117.353 15.648 117.539 18.264 ;
     RECT  117.491 19.248 117.641 21.912 ;
     RECT  117.641 21.696 117.731 21.912 ;
     RECT  117.641 19.248 117.779 20.376 ;
     RECT  117.539 15.648 117.923 17.688 ;
     RECT  117.923 15.648 117.971 17.448 ;
     RECT  117.497 23.232 118.001 42.936 ;
     RECT  117.731 21.888 118.019 21.912 ;
     RECT  117.353 11.136 118.259 14.52 ;
     RECT  117.971 16.224 118.451 17.448 ;
     RECT  117.779 19.248 118.499 20.328 ;
     RECT  117.497 43.968 118.573 50.616 ;
     RECT  118.499 19.584 118.595 20.328 ;
     RECT  118.001 23.232 118.595 35.928 ;
     RECT  118.595 23.376 118.613 35.928 ;
     RECT  118.001 37.056 118.613 42.936 ;
     RECT  118.573 43.968 118.613 50.952 ;
     RECT  118.613 46.464 118.721 50.952 ;
     RECT  118.259 11.232 118.835 14.52 ;
     RECT  118.835 11.664 119.027 14.52 ;
     RECT  118.613 39.36 119.081 42.936 ;
     RECT  118.721 46.464 119.081 50.616 ;
     RECT  118.613 37.152 119.117 38.328 ;
     RECT  119.081 39.36 119.117 40.536 ;
     RECT  119.081 41.568 119.117 42.936 ;
     RECT  118.613 43.968 119.117 44.952 ;
     RECT  119.081 46.464 119.117 48.024 ;
     RECT  119.081 49.056 119.117 50.616 ;
     RECT  117.461 52.416 119.117 62.136 ;
     RECT  118.595 19.872 119.123 20.328 ;
     RECT  119.117 41.568 119.153 42.168 ;
     RECT  118.717 21.648 119.171 21.672 ;
     RECT  118.613 23.376 119.189 35.736 ;
     RECT  119.123 20.112 119.267 20.328 ;
     RECT  119.117 59.232 119.297 62.136 ;
     RECT  119.267 20.112 119.363 20.184 ;
     RECT  118.451 16.224 119.459 17.4 ;
     RECT  119.027 12.288 119.507 14.52 ;
     RECT  119.117 50.592 119.549 50.616 ;
     RECT  119.507 12.288 119.555 12.312 ;
     RECT  119.189 23.904 119.585 35.736 ;
     RECT  119.117 44.4 119.585 44.952 ;
     RECT  119.297 59.232 119.585 59.256 ;
     RECT  119.585 29.184 119.621 35.736 ;
     RECT  119.117 52.416 119.621 53.208 ;
     RECT  119.363 20.112 119.651 20.136 ;
     RECT  119.585 24.864 119.657 28.152 ;
     RECT  119.117 46.464 119.657 47.448 ;
     RECT  119.117 57.6 119.657 57.624 ;
     RECT  119.297 60.384 119.657 62.136 ;
     RECT  119.657 25.2 119.693 28.152 ;
     RECT  119.621 29.664 119.729 35.736 ;
     RECT  119.729 30.336 119.765 35.736 ;
     RECT  119.117 55.008 119.765 56.472 ;
     RECT  119.459 16.224 119.795 16.824 ;
     RECT  119.693 25.248 119.801 28.152 ;
     RECT  119.765 55.008 119.801 56.088 ;
     RECT  119.765 34.752 119.837 35.736 ;
     RECT  119.657 47.424 119.837 47.448 ;
     RECT  119.507 13.68 119.843 14.52 ;
     RECT  119.765 30.336 119.873 33.72 ;
     RECT  119.837 35.52 119.873 35.736 ;
     RECT  119.801 56.064 119.873 56.088 ;
     RECT  119.873 31.92 119.881 33.72 ;
     RECT  119.843 13.68 119.891 13.704 ;
     RECT  119.881 33.696 119.909 33.72 ;
     RECT  119.873 35.712 119.945 35.736 ;
     RECT  119.795 16.224 119.987 16.248 ;
     RECT  119.881 31.92 119.989 32.52 ;
     RECT  119.989 31.92 120.161 31.944 ;
     RECT  119.801 25.44 121.208 28.152 ;
     RECT  119.873 30.336 121.208 30.936 ;
     RECT  119.585 44.4 121.208 44.424 ;
     RECT  119.801 55.008 121.208 55.032 ;
     RECT  121.208 2.148 121.312 84.252 ;
     RECT  121.312 2.418 121.504 83.982 ;
     RECT  121.504 44.4 126.608 44.424 ;
     RECT  126.608 2.148 126.712 84.252 ;
     RECT  126.712 2.418 126.904 83.982 ;
     RECT  126.904 44.4 132.008 44.424 ;
     RECT  132.008 2.148 132.112 84.252 ;
     RECT  132.112 2.418 132.304 83.982 ;
     RECT  132.304 44.4 137.408 44.424 ;
     RECT  137.408 2.148 137.512 84.252 ;
     RECT  137.512 2.418 137.704 83.982 ;
     RECT  137.704 44.4 138.557 44.424 ;
    LAYER M5 ;
     RECT  51.504 0.144 53.688 0.227 ;
     RECT  51.648 0.227 53.688 0.563 ;
     RECT  46.56 0.144 47.592 0.851 ;
     RECT  24.528 0.144 42.84 1.235 ;
     RECT  51.936 0.563 53.688 1.235 ;
     RECT  25.536 1.235 42.552 1.283 ;
     RECT  24.528 1.235 24.552 1.427 ;
     RECT  27.264 1.283 42.552 1.475 ;
     RECT  39.216 1.475 42.552 1.763 ;
     RECT  53.328 1.235 53.544 1.763 ;
     RECT  27.264 1.475 38.088 1.811 ;
     RECT  39.216 1.763 42.312 1.907 ;
     RECT  39.216 1.907 42.264 2.003 ;
     RECT  39.648 2.003 42.264 2.051 ;
     RECT  44.688 1.669 44.712 2.137 ;
     RECT  51.936 1.235 52.056 2.137 ;
     RECT  2.4 2.137 2.52 2.151 ;
     RECT  7.8 2.137 7.92 2.151 ;
     RECT  13.2 2.137 13.32 2.151 ;
     RECT  18.6 2.137 18.72 2.151 ;
     RECT  44.688 2.137 45.72 2.151 ;
     RECT  56.4 2.137 56.52 2.151 ;
     RECT  61.8 2.137 61.92 2.151 ;
     RECT  67.2 2.137 67.32 2.151 ;
     RECT  72.6 2.137 72.72 2.151 ;
     RECT  78 2.137 78.12 2.151 ;
     RECT  83.4 2.137 83.52 2.151 ;
     RECT  88.8 2.137 88.92 2.151 ;
     RECT  94.2 2.137 94.32 2.151 ;
     RECT  99.6 2.137 99.72 2.151 ;
     RECT  105 2.137 105.12 2.151 ;
     RECT  110.4 2.137 110.52 2.151 ;
     RECT  115.8 2.137 115.92 2.151 ;
     RECT  121.2 2.137 121.32 2.151 ;
     RECT  126.6 2.137 126.72 2.151 ;
     RECT  132 2.137 132.12 2.151 ;
     RECT  137.4 2.137 137.52 2.151 ;
     RECT  27.264 1.811 29.88 2.291 ;
     RECT  27.264 2.291 29.712 2.339 ;
     RECT  39.648 2.051 42.12 2.339 ;
     RECT  39.792 2.339 42.12 2.387 ;
     RECT  39.936 2.387 42.12 2.531 ;
     RECT  39.984 2.531 42.12 2.627 ;
     RECT  27.264 2.339 27.864 2.915 ;
     RECT  31.296 1.811 38.088 2.915 ;
     RECT  40.2 2.627 42.12 2.915 ;
     RECT  46.992 0.851 47.592 2.915 ;
     RECT  27.84 2.915 27.864 2.963 ;
     RECT  32.88 2.915 38.088 2.963 ;
     RECT  25.536 1.283 25.56 3.059 ;
     RECT  40.2 2.915 41.544 3.059 ;
     RECT  37.632 2.963 38.088 3.299 ;
     RECT  22.176 2.245 22.2 3.347 ;
     RECT  53.328 1.763 53.352 3.349 ;
     RECT  32.88 2.963 36.456 3.971 ;
     RECT  36.144 3.971 36.456 4.595 ;
     RECT  53.328 3.349 53.88 4.885 ;
     RECT  54.912 4.453 54.936 4.885 ;
     RECT  37.632 3.299 37.8 5.171 ;
     RECT  40.2 3.059 40.68 5.171 ;
     RECT  51 2.137 52.056 5.413 ;
     RECT  51 5.413 52.248 5.555 ;
     RECT  51 5.555 52.056 5.605 ;
     RECT  61.8 2.151 62.112 5.605 ;
     RECT  26.208 5.461 26.232 5.653 ;
     RECT  36.384 4.595 36.456 5.747 ;
     RECT  29.4 2.339 29.712 5.989 ;
     RECT  26.208 5.653 26.472 6.035 ;
     RECT  53.328 4.885 54.936 6.035 ;
     RECT  44.688 2.151 45.912 6.083 ;
     RECT  60.96 5.605 62.112 6.371 ;
     RECT  40.2 5.171 40.512 6.517 ;
     RECT  38.784 3.829 38.808 6.563 ;
     RECT  54.912 6.035 54.936 6.565 ;
     RECT  56.4 2.151 56.712 6.565 ;
     RECT  36.384 5.747 36.408 6.659 ;
     RECT  50.016 5.605 52.056 6.707 ;
     RECT  31.44 2.915 31.464 6.755 ;
     RECT  45.6 6.083 45.912 6.805 ;
     RECT  46.992 2.915 47.016 6.805 ;
     RECT  51 6.707 52.056 6.805 ;
     RECT  53.328 6.035 53.88 6.805 ;
     RECT  48.096 6.229 48.12 6.851 ;
     RECT  32.88 3.971 35.112 6.899 ;
     RECT  40.08 6.517 40.512 6.899 ;
     RECT  54.912 6.565 56.712 6.947 ;
     RECT  51 6.805 53.88 7.333 ;
     RECT  51 7.333 54.168 7.475 ;
     RECT  55.824 6.947 56.712 7.907 ;
     RECT  51 7.475 52.776 8.147 ;
     RECT  53.856 7.475 54.168 8.435 ;
     RECT  18.6 2.151 18.912 8.485 ;
     RECT  29.4 5.989 29.832 8.485 ;
     RECT  40.2 6.899 40.512 8.485 ;
     RECT  28.368 6.805 28.392 8.677 ;
     RECT  59.808 7.381 59.832 8.677 ;
     RECT  27.936 8.677 28.392 8.723 ;
     RECT  59.664 8.677 59.832 8.723 ;
     RECT  40.2 8.485 40.728 9.061 ;
     RECT  26.448 6.035 26.472 9.107 ;
     RECT  22.512 7.189 22.536 9.683 ;
     RECT  52.752 8.147 52.776 9.779 ;
     RECT  45.6 6.805 47.016 9.781 ;
     RECT  18.6 8.485 19.176 9.827 ;
     RECT  18.6 9.827 18.912 9.925 ;
     RECT  48.24 7.333 48.264 10.019 ;
     RECT  39.696 9.061 40.728 10.069 ;
     RECT  51 8.147 51.312 10.069 ;
     RECT  24 2.137 24.312 10.501 ;
     RECT  33.888 6.899 35.112 10.501 ;
     RECT  29.4 8.485 30.024 10.549 ;
     RECT  27.936 8.723 27.96 10.595 ;
     RECT  49.536 6.805 49.56 10.595 ;
     RECT  72.6 2.151 72.912 10.597 ;
     RECT  39.024 10.069 40.728 10.643 ;
     RECT  42.144 9.829 42.168 10.643 ;
     RECT  32.88 6.899 32.904 10.789 ;
     RECT  72.6 10.597 73.08 11.125 ;
     RECT  72.48 11.125 73.08 11.171 ;
     RECT  118.224 11.125 118.248 11.221 ;
     RECT  33.888 10.501 35.88 11.363 ;
     RECT  37.152 11.317 37.176 11.365 ;
     RECT  45.6 9.781 47.16 11.365 ;
     RECT  32.4 10.789 32.904 11.459 ;
     RECT  24 10.501 25.08 11.653 ;
     RECT  118.224 11.221 118.824 11.653 ;
     RECT  18.24 9.925 18.912 11.699 ;
     RECT  21.792 10.837 21.816 11.749 ;
     RECT  50.88 10.069 51.312 11.749 ;
     RECT  21.792 11.749 22.056 11.941 ;
     RECT  39.024 10.643 40.512 11.941 ;
     RECT  21.792 11.941 22.536 12.035 ;
     RECT  45.312 11.365 47.16 12.035 ;
     RECT  20.736 11.317 20.76 12.083 ;
     RECT  39.024 11.941 40.68 12.181 ;
     RECT  118.224 11.653 119.016 12.277 ;
     RECT  53.856 8.435 53.88 12.323 ;
     RECT  45.312 12.035 46.392 12.563 ;
     RECT  72.48 11.171 72.912 12.851 ;
     RECT  22.032 12.035 22.536 12.997 ;
     RECT  24 11.653 25.176 12.997 ;
     RECT  18.6 11.699 18.912 13.045 ;
     RECT  28.992 10.549 30.024 13.091 ;
     RECT  32.88 11.459 32.904 13.139 ;
     RECT  45.6 12.563 46.392 13.139 ;
     RECT  28.992 13.091 29.832 13.283 ;
     RECT  17.568 12.325 17.592 13.285 ;
     RECT  24 12.997 25.56 13.331 ;
     RECT  74.208 12.853 74.232 13.525 ;
     RECT  38.88 12.181 40.68 13.571 ;
     RECT  74.208 13.525 74.376 13.571 ;
     RECT  74.352 13.571 74.376 13.573 ;
     RECT  36.96 11.365 37.176 13.619 ;
     RECT  33.888 11.363 35.112 13.621 ;
     RECT  74.352 13.573 74.472 13.621 ;
     RECT  118.224 12.277 119.544 13.669 ;
     RECT  50.64 11.749 51.312 13.715 ;
     RECT  36.96 13.619 36.984 13.765 ;
     RECT  50.736 13.715 51.312 14.243 ;
     RECT  21.456 12.997 22.536 14.245 ;
     RECT  21.408 14.245 22.536 14.341 ;
     RECT  29.4 13.283 29.832 14.533 ;
     RECT  33.408 13.621 35.112 14.867 ;
     RECT  36.48 13.765 36.984 14.963 ;
     RECT  59.664 8.723 59.688 14.963 ;
     RECT  38.88 13.571 40.512 15.253 ;
     RECT  118.224 13.669 119.88 15.637 ;
     RECT  20.544 14.341 22.536 15.733 ;
     RECT  38.88 15.253 40.872 15.877 ;
     RECT  115.8 2.151 116.112 15.877 ;
     RECT  117.936 15.637 119.88 15.877 ;
     RECT  18.6 13.045 19.512 15.973 ;
     RECT  20.496 15.733 22.536 15.973 ;
     RECT  33.408 14.867 33.432 16.213 ;
     RECT  115.8 15.877 119.88 16.213 ;
     RECT  33.072 16.213 33.432 16.259 ;
     RECT  27.36 14.773 27.384 16.787 ;
     RECT  28.944 14.533 29.832 16.787 ;
     RECT  42.192 11.365 42.216 17.123 ;
     RECT  16.944 13.285 17.592 17.125 ;
     RECT  18.6 15.973 22.536 17.125 ;
     RECT  36.96 14.963 36.984 17.605 ;
     RECT  38.832 15.877 40.872 17.605 ;
     RECT  29.4 16.787 29.832 17.699 ;
     RECT  24 13.331 24.312 17.845 ;
     RECT  25.536 13.331 25.56 17.845 ;
     RECT  24 17.845 25.56 17.891 ;
     RECT  36.96 17.605 40.872 17.891 ;
     RECT  34.8 14.867 35.112 17.893 ;
     RECT  15.84 17.557 15.864 17.941 ;
     RECT  16.944 17.125 22.536 17.941 ;
     RECT  24 17.891 25.128 18.179 ;
     RECT  29.4 17.699 29.712 18.613 ;
     RECT  33.072 16.259 33.096 18.661 ;
     RECT  32.304 18.661 33.096 18.707 ;
     RECT  29.088 18.613 29.712 18.851 ;
     RECT  36.96 17.891 37.896 19.043 ;
     RECT  15.84 17.941 22.536 19.285 ;
     RECT  32.304 18.707 32.328 19.427 ;
     RECT  37.872 19.043 37.896 19.619 ;
     RECT  24 18.179 24.312 19.717 ;
     RECT  39.696 17.891 40.872 19.763 ;
     RECT  24 19.717 24.792 19.813 ;
     RECT  23.904 19.813 24.792 19.955 ;
     RECT  74.352 13.621 74.808 20.003 ;
     RECT  76.992 11.701 77.016 20.003 ;
     RECT  15.744 19.285 22.536 20.195 ;
     RECT  34.464 17.893 35.112 20.243 ;
     RECT  115.8 16.213 119.976 22.403 ;
     RECT  117.312 22.403 119.976 23.795 ;
     RECT  117.408 23.795 119.976 24.227 ;
     RECT  117.456 24.227 119.976 25.477 ;
     RECT  15.744 20.195 22.392 26.725 ;
     RECT  13.2 2.151 13.512 27.637 ;
     RECT  13.104 27.637 13.512 28.211 ;
     RECT  15.12 26.725 22.392 30.371 ;
     RECT  13.2 28.211 13.512 30.613 ;
     RECT  117.36 25.477 119.976 30.899 ;
     RECT  117.36 30.899 117.384 31.331 ;
     RECT  13.2 30.613 14.424 32.291 ;
     RECT  118.368 30.899 119.976 32.435 ;
     RECT  119.52 32.435 119.976 32.531 ;
     RECT  119.52 32.531 119.832 33.107 ;
     RECT  118.368 32.435 118.392 33.395 ;
     RECT  13.2 32.291 13.512 34.837 ;
     RECT  12.96 34.837 13.512 34.979 ;
     RECT  9.36 30.325 9.384 35.363 ;
     RECT  13.2 34.979 13.512 38.437 ;
     RECT  13.2 38.437 13.608 38.485 ;
     RECT  13.104 38.485 13.608 39.011 ;
     RECT  13.2 39.011 13.608 39.059 ;
     RECT  6.144 35.749 6.168 39.923 ;
     RECT  5.088 39.877 5.112 40.357 ;
     RECT  15.744 30.371 22.392 40.501 ;
     RECT  15.36 40.501 22.392 40.643 ;
     RECT  13.2 39.059 13.512 40.645 ;
     RECT  4.848 40.357 5.112 41.075 ;
     RECT  13.2 40.645 13.608 41.411 ;
     RECT  13.2 41.411 13.512 42.421 ;
     RECT  13.2 42.421 13.608 42.563 ;
     RECT  15.744 40.643 22.392 42.565 ;
     RECT  7.8 2.151 8.112 43.621 ;
     RECT  4.848 41.075 4.872 44.339 ;
     RECT  7.8 43.621 8.232 50.101 ;
     RECT  15.552 42.565 22.392 50.725 ;
     RECT  14.784 50.725 22.392 52.403 ;
     RECT  13.2 42.563 13.512 52.405 ;
     RECT  13.2 52.405 14.136 52.981 ;
     RECT  12.768 52.981 14.136 54.179 ;
     RECT  7.488 50.101 8.232 54.515 ;
     RECT  6.384 53.557 6.408 54.851 ;
     RECT  13.104 54.179 14.136 55.283 ;
     RECT  9.216 54.661 9.24 55.571 ;
     RECT  10.8 55.237 10.824 55.907 ;
     RECT  15.552 52.403 22.392 56.195 ;
     RECT  7.488 54.515 8.112 57.109 ;
     RECT  13.2 55.283 14.136 57.347 ;
     RECT  2.4 2.151 2.712 57.445 ;
     RECT  7.488 57.109 8.424 57.829 ;
     RECT  6.768 57.829 8.424 57.875 ;
     RECT  2.4 57.445 3.432 58.163 ;
     RECT  7.8 57.875 8.424 58.163 ;
     RECT  15.552 56.195 22.344 58.739 ;
     RECT  13.2 57.347 13.512 59.029 ;
     RECT  7.8 58.163 8.232 59.075 ;
     RECT  20.784 58.739 22.344 59.315 ;
     RECT  15.552 58.739 18.912 59.413 ;
     RECT  6.768 57.875 6.792 59.749 ;
     RECT  7.8 59.075 8.112 59.749 ;
     RECT  20.784 59.315 20.856 59.891 ;
     RECT  11.376 58.117 11.4 60.179 ;
     RECT  15.36 59.413 18.912 60.373 ;
     RECT  6.768 59.749 8.112 60.419 ;
     RECT  20.784 59.891 20.808 60.467 ;
     RECT  15.36 60.373 19.032 60.515 ;
     RECT  13.2 59.029 13.656 60.997 ;
     RECT  5.232 58.693 5.256 61.043 ;
     RECT  7.8 60.419 8.112 61.189 ;
     RECT  15.552 60.515 19.032 61.379 ;
     RECT  13.2 60.997 14.28 61.619 ;
     RECT  22.128 59.315 22.344 62.051 ;
     RECT  7.8 61.189 9.096 62.195 ;
     RECT  11.184 61.381 11.208 62.195 ;
     RECT  15.552 61.379 16.536 62.243 ;
     RECT  22.32 62.051 22.344 62.485 ;
     RECT  13.2 61.619 13.608 62.677 ;
     RECT  17.664 61.379 19.032 63.203 ;
     RECT  15.552 62.243 15.576 63.205 ;
     RECT  6.768 60.419 6.792 63.349 ;
     RECT  7.8 62.195 8.112 63.349 ;
     RECT  5.376 62.629 5.4 63.491 ;
     RECT  22.32 62.485 22.392 63.683 ;
     RECT  24 19.955 24.792 63.683 ;
     RECT  18.24 63.203 19.032 63.781 ;
     RECT  22.32 63.683 22.344 63.875 ;
     RECT  9.36 62.677 9.384 64.117 ;
     RECT  9.36 64.117 10.296 64.355 ;
     RECT  18.24 63.781 19.992 64.355 ;
     RECT  18.384 64.355 19.992 64.645 ;
     RECT  21.024 62.437 21.048 64.645 ;
     RECT  13.2 62.677 14.28 64.789 ;
     RECT  15.552 63.205 16.152 64.981 ;
     RECT  10.272 64.355 10.296 65.027 ;
     RECT  117.36 44.389 117.384 65.699 ;
     RECT  15.552 64.981 16.92 65.747 ;
     RECT  15.552 65.747 16.536 65.795 ;
     RECT  2.4 58.163 2.712 65.797 ;
     RECT  24 63.683 24.312 65.797 ;
     RECT  40.2 19.763 40.512 66.085 ;
     RECT  13.2 64.789 14.52 66.179 ;
     RECT  27.888 65.941 27.912 66.229 ;
     RECT  14.496 66.179 14.52 66.469 ;
     RECT  29.4 18.851 29.712 66.613 ;
     RECT  36.432 66.613 36.456 66.661 ;
     RECT  27.264 66.229 27.912 66.709 ;
     RECT  24 65.797 24.936 66.755 ;
     RECT  26.736 66.709 27.912 66.755 ;
     RECT  16.512 65.795 16.536 66.851 ;
     RECT  29.4 66.613 30.312 67.237 ;
     RECT  2.4 65.797 3.384 67.283 ;
     RECT  29.088 67.237 30.312 67.285 ;
     RECT  18.384 64.645 21.048 67.477 ;
     RECT  13.2 66.179 13.512 67.669 ;
     RECT  14.496 66.469 15.384 67.669 ;
     RECT  28.464 67.285 30.312 67.669 ;
     RECT  34.656 20.243 35.112 67.669 ;
     RECT  17.424 67.477 21.048 67.715 ;
     RECT  28.464 67.669 30.744 67.715 ;
     RECT  39.6 66.085 40.512 67.715 ;
     RECT  6.768 63.349 8.112 67.717 ;
     RECT  26.736 66.755 27.288 67.765 ;
     RECT  36.432 66.661 37.32 67.811 ;
     RECT  6.144 67.717 8.112 67.859 ;
     RECT  26.736 67.765 27.384 68.099 ;
     RECT  2.4 67.283 2.712 68.245 ;
     RECT  28.464 67.715 29.712 68.339 ;
     RECT  13.2 67.669 15.384 68.341 ;
     RECT  27.264 68.099 27.384 68.341 ;
     RECT  24 66.755 24.312 68.389 ;
     RECT  34.656 67.669 35.352 68.435 ;
     RECT  7.8 67.859 8.112 68.629 ;
     RECT  13.008 68.341 15.384 68.629 ;
     RECT  13.008 68.629 15.72 68.771 ;
     RECT  29.088 68.339 29.712 68.771 ;
     RECT  10.56 67.813 10.584 68.915 ;
     RECT  13.008 68.771 14.904 68.917 ;
     RECT  23.712 68.389 24.312 68.917 ;
     RECT  37.296 67.811 37.32 68.917 ;
     RECT  34.8 68.435 35.352 69.107 ;
     RECT  23.712 68.917 24.936 69.203 ;
     RECT  40.2 67.715 40.512 69.205 ;
     RECT  18.048 67.715 21.048 69.301 ;
     RECT  39.84 69.205 40.512 69.349 ;
     RECT  30.72 67.715 30.744 69.587 ;
     RECT  7.8 68.629 8.568 69.637 ;
     RECT  7.8 69.637 9.48 69.683 ;
     RECT  42.72 68.341 42.744 69.779 ;
     RECT  37.296 68.917 37.752 69.827 ;
     RECT  37.728 69.827 37.752 70.019 ;
     RECT  6.144 67.859 6.264 70.163 ;
     RECT  12.528 68.917 14.904 70.163 ;
     RECT  24 69.203 24.936 70.259 ;
     RECT  39.312 69.349 40.512 70.643 ;
     RECT  2.4 68.245 3.432 70.645 ;
     RECT  17.664 69.301 21.048 70.645 ;
     RECT  36.672 70.501 36.696 70.645 ;
     RECT  12.528 70.163 14.376 70.691 ;
     RECT  17.664 70.645 22.008 70.739 ;
     RECT  42.096 69.781 42.12 70.739 ;
     RECT  2.4 70.645 3.96 71.123 ;
     RECT  7.8 69.683 8.112 71.221 ;
     RECT  9.456 69.683 9.48 71.315 ;
     RECT  18.384 70.739 22.008 71.315 ;
     RECT  31.296 70.693 31.32 71.315 ;
     RECT  39.84 70.643 40.512 71.315 ;
     RECT  36.432 70.645 36.696 71.363 ;
     RECT  18.384 71.315 19.368 71.701 ;
     RECT  42.576 71.077 42.6 71.747 ;
     RECT  24 70.259 24.888 71.797 ;
     RECT  2.4 71.123 3 71.843 ;
     RECT  11.376 72.133 11.4 72.419 ;
     RECT  17.856 71.701 19.368 72.659 ;
     RECT  24 71.797 25.128 72.661 ;
     RECT  17.856 72.659 19.128 72.707 ;
     RECT  24 72.661 26.04 72.707 ;
     RECT  7.44 71.221 8.112 72.755 ;
     RECT  12.768 70.691 14.376 72.853 ;
     RECT  12.768 72.853 14.856 72.901 ;
     RECT  27.264 68.341 27.816 72.995 ;
     RECT  36.672 71.363 36.696 73.189 ;
     RECT  26.016 72.707 26.04 73.235 ;
     RECT  20.496 71.315 22.008 73.237 ;
     RECT  18.24 72.707 19.128 73.379 ;
     RECT  34.8 69.107 35.112 73.477 ;
     RECT  20.496 73.237 22.92 73.765 ;
     RECT  20.448 73.765 22.92 73.811 ;
     RECT  36.576 73.189 36.696 73.861 ;
     RECT  12.672 72.901 14.856 73.955 ;
     RECT  31.632 73.477 31.656 74.147 ;
     RECT  29.4 68.771 29.712 74.581 ;
     RECT  27.456 72.995 27.816 74.627 ;
     RECT  5.136 73.477 5.16 74.723 ;
     RECT  22.896 73.811 22.92 74.867 ;
     RECT  12.768 73.955 14.856 75.107 ;
     RECT  34.176 73.477 35.112 75.109 ;
     RECT  24 72.707 24.312 75.493 ;
     RECT  12.768 75.107 14.328 75.827 ;
     RECT  20.448 73.811 21.048 75.875 ;
     RECT  29.088 74.581 29.712 75.875 ;
     RECT  31.872 74.629 31.896 75.923 ;
     RECT  34.176 75.109 35.496 75.971 ;
     RECT  10.272 73.909 10.296 76.115 ;
     RECT  34.176 75.971 35.112 76.259 ;
     RECT  18.6 73.379 19.128 76.739 ;
     RECT  30.72 75.877 30.744 76.739 ;
     RECT  20.448 75.875 20.472 76.885 ;
     RECT  23.088 75.493 24.312 76.885 ;
     RECT  36.576 73.861 37.56 76.979 ;
     RECT  29.4 75.875 29.712 77.317 ;
     RECT  17.424 76.021 17.448 77.411 ;
     RECT  11.376 76.069 11.4 77.413 ;
     RECT  6.24 70.163 6.264 77.555 ;
     RECT  13.104 75.827 14.328 77.555 ;
     RECT  23.04 76.885 24.312 77.555 ;
     RECT  27.792 74.627 27.816 77.891 ;
     RECT  37.056 76.979 37.56 77.891 ;
     RECT  25.536 75.253 25.56 77.941 ;
     RECT  11.376 77.413 12.12 78.037 ;
     RECT  29.4 77.317 29.832 78.131 ;
     RECT  20.448 76.885 20.52 78.179 ;
     RECT  25.536 77.941 26.472 78.419 ;
     RECT  26.448 78.419 26.472 78.613 ;
     RECT  11.28 78.037 12.12 78.707 ;
     RECT  26.448 78.613 26.952 78.707 ;
     RECT  34.8 76.259 35.112 79.093 ;
     RECT  37.056 77.891 37.08 79.139 ;
     RECT  26.928 78.707 26.952 79.475 ;
     RECT  20.448 78.179 20.472 79.571 ;
     RECT  22.752 78.133 22.776 79.571 ;
     RECT  9.648 77.461 9.672 79.763 ;
     RECT  29.4 78.131 29.712 79.765 ;
     RECT  13.2 77.555 14.328 79.813 ;
     RECT  11.28 78.707 11.304 80.003 ;
     RECT  33.648 77.029 33.672 80.051 ;
     RECT  13.056 79.813 14.328 80.387 ;
     RECT  34.8 79.093 35.736 80.771 ;
     RECT  18.6 76.739 18.912 80.869 ;
     RECT  32.352 80.341 32.376 80.963 ;
     RECT  13.2 80.387 14.328 81.539 ;
     RECT  30.96 79.045 30.984 81.635 ;
     RECT  28.464 79.765 29.712 81.731 ;
     RECT  21.648 80.341 21.672 82.211 ;
     RECT  25.632 79.477 25.656 82.211 ;
     RECT  18.6 80.869 19.416 82.259 ;
     RECT  2.4 71.843 2.712 84.249 ;
     RECT  7.8 72.755 8.112 84.249 ;
     RECT  13.2 81.539 13.512 84.249 ;
     RECT  18.6 82.259 18.912 84.249 ;
     RECT  24 77.555 24.312 84.249 ;
     RECT  29.4 81.731 29.712 84.249 ;
     RECT  34.8 80.771 35.112 84.249 ;
     RECT  40.2 71.315 40.512 84.249 ;
     RECT  45.6 13.139 45.912 84.249 ;
     RECT  51 14.243 51.312 84.249 ;
     RECT  56.4 7.907 56.712 84.249 ;
     RECT  61.8 6.371 62.112 84.249 ;
     RECT  67.2 2.151 67.512 84.249 ;
     RECT  72.6 12.851 72.912 84.249 ;
     RECT  78 2.151 78.312 84.249 ;
     RECT  83.4 2.151 83.712 84.249 ;
     RECT  88.8 2.151 89.112 84.249 ;
     RECT  94.2 2.151 94.512 84.249 ;
     RECT  99.6 2.151 99.912 84.249 ;
     RECT  105 2.151 105.312 84.249 ;
     RECT  110.4 2.151 110.712 84.249 ;
     RECT  115.8 22.403 116.112 84.249 ;
     RECT  121.2 2.151 121.512 84.249 ;
     RECT  126.6 2.151 126.912 84.249 ;
     RECT  132 2.151 132.312 84.249 ;
     RECT  137.4 2.151 137.712 84.249 ;
     RECT  2.4 84.249 2.52 84.263 ;
     RECT  7.8 84.249 7.92 84.263 ;
     RECT  13.2 84.249 13.32 84.263 ;
     RECT  18.6 84.249 18.72 84.263 ;
     RECT  24 84.249 24.12 84.263 ;
     RECT  29.4 84.249 29.52 84.263 ;
     RECT  34.8 84.249 34.92 84.263 ;
     RECT  40.2 84.249 40.32 84.263 ;
     RECT  45.6 84.249 45.72 84.263 ;
     RECT  51 84.249 51.12 84.263 ;
     RECT  56.4 84.249 56.52 84.263 ;
     RECT  61.8 84.249 61.92 84.263 ;
     RECT  67.2 84.249 67.32 84.263 ;
     RECT  72.6 84.249 72.72 84.263 ;
     RECT  78 84.249 78.12 84.263 ;
     RECT  83.4 84.249 83.52 84.263 ;
     RECT  88.8 84.249 88.92 84.263 ;
     RECT  94.2 84.249 94.32 84.263 ;
     RECT  99.6 84.249 99.72 84.263 ;
     RECT  105 84.249 105.12 84.263 ;
     RECT  110.4 84.249 110.52 84.263 ;
     RECT  115.8 84.249 115.92 84.263 ;
     RECT  121.2 84.249 121.32 84.263 ;
     RECT  126.6 84.249 126.72 84.263 ;
     RECT  132 84.249 132.12 84.263 ;
     RECT  137.4 84.249 137.52 84.263 ;
     RECT  46.56 0.851 46.992 2.137 ;
     RECT  24.552 1.235 25.536 1.427 ;
     RECT  52.056 1.235 53.328 5.413 ;
     RECT  24.528 1.427 25.536 2.137 ;
     RECT  38.088 1.475 39.216 2.003 ;
     RECT  29.88 1.811 31.296 2.291 ;
     RECT  24.312 2.137 25.536 3.059 ;
     RECT  45.72 2.137 46.992 2.151 ;
     RECT  45.912 2.151 46.992 6.805 ;
     RECT  39.648 2.339 39.792 2.387 ;
     RECT  39.648 2.387 39.936 2.531 ;
     RECT  39.648 2.531 39.984 2.627 ;
     RECT  39.648 2.627 40.2 3.829 ;
     RECT  31.464 2.915 32.88 6.755 ;
     RECT  36.456 2.963 37.632 5.171 ;
     RECT  37.8 3.299 38.088 3.829 ;
     RECT  37.8 3.829 38.784 5.171 ;
     RECT  38.808 3.829 40.2 6.517 ;
     RECT  35.112 3.971 36.144 4.595 ;
     RECT  53.88 4.453 54.912 4.885 ;
     RECT  54.936 4.453 56.4 6.565 ;
     RECT  35.112 4.595 36.384 6.659 ;
     RECT  52.248 5.413 53.328 5.555 ;
     RECT  52.056 5.555 53.328 6.805 ;
     RECT  53.88 6.035 54.912 6.947 ;
     RECT  47.016 6.229 48.096 6.851 ;
     RECT  38.808 6.517 40.08 6.563 ;
     RECT  50.016 6.707 51 6.805 ;
     RECT  28.392 6.805 29.4 8.723 ;
     RECT  48.12 6.805 49.536 6.851 ;
     RECT  49.56 6.805 51 10.069 ;
     RECT  47.016 6.851 49.536 7.333 ;
     RECT  32.904 6.899 33.888 13.139 ;
     RECT  53.88 6.947 54.168 7.333 ;
     RECT  22.536 7.189 24 9.683 ;
     RECT  47.016 7.333 48.24 9.781 ;
     RECT  48.264 7.333 49.536 10.019 ;
     RECT  52.776 7.475 53.856 9.779 ;
     RECT  51.312 8.147 52.752 9.779 ;
     RECT  26.472 8.677 27.936 9.107 ;
     RECT  27.96 8.723 29.4 10.549 ;
     RECT  47.16 9.781 48.24 10.019 ;
     RECT  40.728 9.829 42.144 10.643 ;
     RECT  49.56 10.069 50.88 10.595 ;
     RECT  27.96 10.549 28.992 10.595 ;
     RECT  50.64 10.595 50.88 11.749 ;
     RECT  40.512 10.643 42.168 11.365 ;
     RECT  20.76 11.317 21.792 12.035 ;
     RECT  35.88 11.317 37.152 11.363 ;
     RECT  36.96 11.363 37.152 11.365 ;
     RECT  40.512 11.365 42.192 11.941 ;
     RECT  18.24 11.699 18.6 12.325 ;
     RECT  77.016 11.701 78 20.003 ;
     RECT  22.536 11.941 24 19.813 ;
     RECT  40.68 11.941 42.192 13.571 ;
     RECT  20.76 12.035 22.032 12.083 ;
     RECT  21.456 12.083 22.032 12.997 ;
     RECT  17.592 12.325 18.6 17.125 ;
     RECT  72.912 12.853 74.208 13.571 ;
     RECT  33.408 13.139 33.888 13.621 ;
     RECT  28.992 13.283 29.4 14.533 ;
     RECT  24.312 13.331 25.536 17.845 ;
     RECT  72.912 13.571 74.352 20.003 ;
     RECT  119.88 13.669 121.2 16.213 ;
     RECT  35.112 13.765 36.48 14.963 ;
     RECT  19.512 14.341 20.544 15.733 ;
     RECT  33.432 14.867 34.8 16.259 ;
     RECT  40.872 15.253 42.192 17.123 ;
     RECT  19.512 15.733 20.496 15.973 ;
     RECT  119.976 16.213 121.2 32.531 ;
     RECT  15.864 17.557 16.944 17.941 ;
     RECT  33.096 17.893 34.464 18.707 ;
     RECT  22.536 19.813 23.904 19.955 ;
     RECT  22.536 19.955 24 20.195 ;
     RECT  116.112 22.403 117.312 23.795 ;
     RECT  116.112 23.795 117.408 24.227 ;
     RECT  116.112 24.227 117.456 25.477 ;
     RECT  116.112 25.477 117.36 31.331 ;
     RECT  8.112 30.325 9.36 35.363 ;
     RECT  15.12 30.371 15.744 30.613 ;
     RECT  14.424 30.613 15.744 32.291 ;
     RECT  117.384 30.899 118.368 31.331 ;
     RECT  118.392 32.435 119.52 33.107 ;
     RECT  119.832 32.531 121.2 33.107 ;
     RECT  5.112 39.877 6.144 39.923 ;
     RECT  13.512 41.411 13.608 42.421 ;
     RECT  116.112 44.389 117.36 65.699 ;
     RECT  13.512 50.725 14.784 52.403 ;
     RECT  13.512 52.403 15.552 52.405 ;
     RECT  14.136 52.405 15.552 57.347 ;
     RECT  6.408 53.557 7.488 54.851 ;
     RECT  8.112 54.515 8.232 54.661 ;
     RECT  8.112 54.661 9.216 55.571 ;
     RECT  6.792 57.875 7.8 59.749 ;
     RECT  5.256 58.693 6.768 61.043 ;
     RECT  20.856 59.315 22.128 59.891 ;
     RECT  20.808 59.891 22.128 60.467 ;
     RECT  6.792 60.419 7.8 63.349 ;
     RECT  15.36 60.515 15.552 60.997 ;
     RECT  14.28 60.997 15.552 61.619 ;
     RECT  16.536 61.379 17.664 62.243 ;
     RECT  13.608 61.619 15.552 62.677 ;
     RECT  22.128 62.051 22.32 62.437 ;
     RECT  8.112 62.195 9.096 62.677 ;
     RECT  15.576 62.243 17.664 63.203 ;
     RECT  21.048 62.437 22.32 63.875 ;
     RECT  5.4 62.629 6.768 63.491 ;
     RECT  8.112 62.677 9.36 64.355 ;
     RECT  14.28 62.677 15.552 64.789 ;
     RECT  15.576 63.203 16.152 63.205 ;
     RECT  19.992 63.781 21.024 64.645 ;
     RECT  18.24 64.355 18.384 64.981 ;
     RECT  14.52 64.789 15.552 65.795 ;
     RECT  16.92 64.981 18.384 65.747 ;
     RECT  14.52 65.795 16.512 66.469 ;
     RECT  27.912 65.941 29.4 66.755 ;
     RECT  13.512 66.179 14.496 67.669 ;
     RECT  15.384 66.469 16.512 66.851 ;
     RECT  35.112 66.613 36.432 67.669 ;
     RECT  27.288 66.755 29.4 67.237 ;
     RECT  27.288 67.237 29.088 67.285 ;
     RECT  2.712 67.283 3.384 68.245 ;
     RECT  27.288 67.285 28.464 67.765 ;
     RECT  35.352 67.669 36.432 67.811 ;
     RECT  29.712 67.715 30.72 69.587 ;
     RECT  39.84 67.715 40.2 69.205 ;
     RECT  27.384 67.765 28.464 68.339 ;
     RECT  27.384 68.339 29.088 68.341 ;
     RECT  27.816 68.341 29.088 68.771 ;
     RECT  8.112 69.683 9.456 71.315 ;
     RECT  35.112 70.645 36.432 71.363 ;
     RECT  12.528 70.691 12.768 72.133 ;
     RECT  17.856 70.739 18.384 71.701 ;
     RECT  6.264 71.221 7.44 72.755 ;
     RECT  19.368 71.315 20.496 72.659 ;
     RECT  11.4 72.133 12.768 72.419 ;
     RECT  12.672 72.419 12.768 72.901 ;
     RECT  19.128 72.659 20.496 73.765 ;
     RECT  26.04 72.661 27.264 72.995 ;
     RECT  26.04 72.995 27.456 73.235 ;
     RECT  35.112 73.189 36.576 75.109 ;
     RECT  22.92 73.237 24 74.867 ;
     RECT  5.16 73.477 6.24 74.723 ;
     RECT  19.128 73.765 20.448 76.739 ;
     RECT  27.816 74.581 29.088 75.875 ;
     RECT  23.088 74.867 24 75.493 ;
     RECT  35.496 75.109 36.576 75.971 ;
     RECT  24.312 75.253 25.536 78.419 ;
     RECT  20.472 75.875 20.52 76.885 ;
     RECT  29.712 75.877 30.72 76.739 ;
     RECT  30.744 75.877 31.872 75.923 ;
     RECT  35.112 75.971 36.576 76.979 ;
     RECT  17.448 76.021 18.6 77.411 ;
     RECT  10.296 76.069 11.376 76.115 ;
     RECT  34.176 76.259 34.8 77.029 ;
     RECT  29.712 76.739 29.832 77.317 ;
     RECT  33.672 77.029 34.8 80.051 ;
     RECT  12.12 77.413 13.104 77.555 ;
     RECT  12.12 77.555 13.2 78.707 ;
     RECT  23.04 77.555 24 78.133 ;
     RECT  29.712 78.131 29.832 79.045 ;
     RECT  22.776 78.133 24 79.571 ;
     RECT  24.312 78.419 26.448 78.707 ;
     RECT  13.056 78.707 13.2 79.813 ;
     RECT  24.312 78.707 26.928 79.475 ;
     RECT  29.712 79.045 30.96 81.635 ;
     RECT  35.736 79.093 37.056 79.139 ;
     RECT  24.312 79.475 25.656 79.477 ;
     RECT  24.312 79.477 25.632 82.211 ;
     RECT  30.984 80.341 32.352 80.963 ;
  END
END ot_s81_pq_ix_rb_native
END LIBRARY
